VERSION 5.8 ;
BUSBITCHARS "[]" ;
DIVIDERCHAR "/" ;
MANUFACTURINGGRID 0.05 ;

UNITS
    DATABASE MICRONS 1000 ;
END UNITS

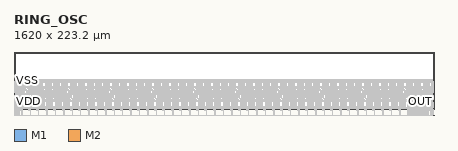
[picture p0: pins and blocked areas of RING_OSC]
MACRO RING_OSC
    CLASS BLOCK ;
    FOREIGN RING_OSC 0.0 0.0 ;
    ORIGIN 0.0 0.0 ;
    SIZE 1620.000 BY 223.200 ;

    PIN OUT
        DIRECTION OUTPUT ;
        USE SIGNAL ;
        PORT
            LAYER M1 ;
                RECT 1616.600 28.000 1620.000 31.400 ;
        END
    END OUT

    PIN OUTD
        DIRECTION OUTPUT ;
        USE SIGNAL ;
        PORT
            LAYER M1 ;
                RECT 1616.600 -26.600 1620.000 -23.200 ;
        END
    END OUTD

    PIN ENB
        DIRECTION INPUT ;
        USE SIGNAL ;
        PORT
            LAYER M2 ;
                RECT 11.800 -108.100 15.200 -104.700 ;
        END
    END ENB

    PIN VDD
        DIRECTION INOUT ;
        USE POWER ;
        PORT
            LAYER M1 ;
                RECT 0.000 -53.500 2.600 -50.900 ;
            LAYER M1 ;
                RECT 1617.400 -53.500 1620.000 -50.900 ;
            LAYER M1 ;
                RECT 0.000 55.700 2.600 58.300 ;
            LAYER M1 ;
                RECT 1617.400 55.700 1620.000 58.300 ;
        END
    END VDD

    PIN VSS
        DIRECTION INOUT ;
        USE GROUND ;
        PORT
            LAYER M1 ;
                RECT 0.000 -108.100 2.600 -105.500 ;
            LAYER M1 ;
                RECT 1617.400 -108.100 1620.000 -105.500 ;
            LAYER M1 ;
                RECT 0.000 1.100 2.600 3.700 ;
            LAYER M1 ;
                RECT 1617.400 1.100 1620.000 3.700 ;
            LAYER M1 ;
                RECT 0.000 110.300 2.600 112.900 ;
            LAYER M1 ;
                RECT 1617.400 110.300 1620.000 112.900 ;
        END
    END VSS

    OBS
        LAYER M1 ;
            POLYGON 2.600 -108.100  2.600 -105.500  1.000 -105.500  1.000 -102.900  4.400 -102.900  4.400 -105.500  11.800 -105.500  11.800 -90.100  14.400 -90.100  14.400 -105.500  18.000 -105.500  18.000 -73.100  20.600 -73.100  20.600 -105.500  49.300 -105.500  49.300 -99.300  51.900 -99.300  51.900 -105.500  81.700 -105.500  81.700 -99.300  84.300 -99.300  84.300 -105.500  114.100 -105.500  114.100 -99.300  116.700 -99.300  116.700 -105.500  146.500 -105.500  146.500 -99.300  149.100 -99.300  149.100 -105.500  178.900 -105.500  178.900 -99.300  181.500 -99.300  181.500 -105.500  211.300 -105.500  211.300 -99.300  213.900 -99.300  213.900 -105.500  243.700 -105.500  243.700 -99.300  246.300 -99.300  246.300 -105.500  276.100 -105.500  276.100 -99.300  278.700 -99.300  278.700 -105.500  308.500 -105.500  308.500 -99.300  311.100 -99.300  311.100 -105.500  340.900 -105.500  340.900 -99.300  343.500 -99.300  343.500 -105.500  373.300 -105.500  373.300 -99.300  375.900 -99.300  375.900 -105.500  405.700 -105.500  405.700 -99.300  408.300 -99.300  408.300 -105.500  438.100 -105.500  438.100 -99.300  440.700 -99.300  440.700 -105.500  470.500 -105.500  470.500 -99.300  473.100 -99.300  473.100 -105.500  502.900 -105.500  502.900 -99.300  505.500 -99.300  505.500 -105.500  535.300 -105.500  535.300 -99.300  537.900 -99.300  537.900 -105.500  567.700 -105.500  567.700 -99.300  570.300 -99.300  570.300 -105.500  600.100 -105.500  600.100 -99.300  602.700 -99.300  602.700 -105.500  632.500 -105.500  632.500 -99.300  635.100 -99.300  635.100 -105.500  664.900 -105.500  664.900 -99.300  667.500 -99.300  667.500 -105.500  697.300 -105.500  697.300 -99.300  699.900 -99.300  699.900 -105.500  729.700 -105.500  729.700 -99.300  732.300 -99.300  732.300 -105.500  762.100 -105.500  762.100 -99.300  764.700 -99.300  764.700 -105.500  794.500 -105.500  794.500 -99.300  797.100 -99.300  797.100 -105.500  826.900 -105.500  826.900 -99.300  829.500 -99.300  829.500 -105.500  859.300 -105.500  859.300 -99.300  861.900 -99.300  861.900 -105.500  891.700 -105.500  891.700 -99.300  894.300 -99.300  894.300 -105.500  924.100 -105.500  924.100 -99.300  926.700 -99.300  926.700 -105.500  956.500 -105.500  956.500 -99.300  959.100 -99.300  959.100 -105.500  988.900 -105.500  988.900 -99.300  991.500 -99.300  991.500 -105.500  1021.300 -105.500  1021.300 -99.300  1023.900 -99.300  1023.900 -105.500  1053.700 -105.500  1053.700 -99.300  1056.300 -99.300  1056.300 -105.500  1086.100 -105.500  1086.100 -99.300  1088.700 -99.300  1088.700 -105.500  1118.500 -105.500  1118.500 -99.300  1121.100 -99.300  1121.100 -105.500  1150.900 -105.500  1150.900 -99.300  1153.500 -99.300  1153.500 -105.500  1183.300 -105.500  1183.300 -99.300  1185.900 -99.300  1185.900 -105.500  1215.700 -105.500  1215.700 -99.300  1218.300 -99.300  1218.300 -105.500  1248.100 -105.500  1248.100 -99.300  1250.700 -99.300  1250.700 -105.500  1280.500 -105.500  1280.500 -99.300  1283.100 -99.300  1283.100 -105.500  1312.900 -105.500  1312.900 -99.300  1315.500 -99.300  1315.500 -105.500  1345.300 -105.500  1345.300 -99.300  1347.900 -99.300  1347.900 -105.500  1377.700 -105.500  1377.700 -99.300  1380.300 -99.300  1380.300 -105.500  1410.100 -105.500  1410.100 -99.300  1412.700 -99.300  1412.700 -105.500  1442.500 -105.500  1442.500 -99.300  1445.100 -99.300  1445.100 -105.500  1474.900 -105.500  1474.900 -99.300  1477.500 -99.300  1477.500 -105.500  1507.300 -105.500  1507.300 -99.300  1509.900 -99.300  1509.900 -105.500  1539.700 -105.500  1539.700 -99.300  1542.300 -99.300  1542.300 -105.500  1572.100 -105.500  1572.100 -99.300  1574.700 -99.300  1574.700 -105.500  1604.500 -105.500  1604.500 -99.300  1607.100 -99.300  1607.100 -105.500  1610.200 -105.500  1610.200 -102.900  1613.600 -102.900  1613.600 -105.500  1617.400 -105.500  1617.400 -108.100 ;
            POLYGON 11.800 -88.500  11.800 -53.500  9.800 -53.500  9.800 -56.100  6.400 -56.100  6.400 -53.500  2.600 -53.500  2.600 -50.900  6.400 -50.900  6.400 -48.300  9.800 -48.300  9.800 -50.900  11.800 -50.900  11.800 -32.900  14.400 -32.900  14.400 -50.900  18.000 -50.900  18.000 -15.900  20.600 -15.900  20.600 -50.900  22.300 -50.900  22.300 -37.900  24.900 -37.900  24.900 -50.900  54.700 -50.900  54.700 -37.900  57.300 -37.900  57.300 -50.900  87.100 -50.900  87.100 -37.900  89.700 -37.900  89.700 -50.900  119.500 -50.900  119.500 -37.900  122.100 -37.900  122.100 -50.900  151.900 -50.900  151.900 -37.900  154.500 -37.900  154.500 -50.900  184.300 -50.900  184.300 -37.900  186.900 -37.900  186.900 -50.900  216.700 -50.900  216.700 -37.900  219.300 -37.900  219.300 -50.900  249.100 -50.900  249.100 -37.900  251.700 -37.900  251.700 -50.900  281.500 -50.900  281.500 -37.900  284.100 -37.900  284.100 -50.900  313.900 -50.900  313.900 -37.900  316.500 -37.900  316.500 -50.900  346.300 -50.900  346.300 -37.900  348.900 -37.900  348.900 -50.900  378.700 -50.900  378.700 -37.900  381.300 -37.900  381.300 -50.900  411.100 -50.900  411.100 -37.900  413.700 -37.900  413.700 -50.900  443.500 -50.900  443.500 -37.900  446.100 -37.900  446.100 -50.900  475.900 -50.900  475.900 -37.900  478.500 -37.900  478.500 -50.900  508.300 -50.900  508.300 -37.900  510.900 -37.900  510.900 -50.900  540.700 -50.900  540.700 -37.900  543.300 -37.900  543.300 -50.900  573.100 -50.900  573.100 -37.900  575.700 -37.900  575.700 -50.900  605.500 -50.900  605.500 -37.900  608.100 -37.900  608.100 -50.900  637.900 -50.900  637.900 -37.900  640.500 -37.900  640.500 -50.900  670.300 -50.900  670.300 -37.900  672.900 -37.900  672.900 -50.900  702.700 -50.900  702.700 -37.900  705.300 -37.900  705.300 -50.900  735.100 -50.900  735.100 -37.900  737.700 -37.900  737.700 -50.900  767.500 -50.900  767.500 -37.900  770.100 -37.900  770.100 -50.900  799.900 -50.900  799.900 -37.900  802.500 -37.900  802.500 -50.900  832.300 -50.900  832.300 -37.900  834.900 -37.900  834.900 -50.900  864.700 -50.900  864.700 -37.900  867.300 -37.900  867.300 -50.900  897.100 -50.900  897.100 -37.900  899.700 -37.900  899.700 -50.900  929.500 -50.900  929.500 -37.900  932.100 -37.900  932.100 -50.900  961.900 -50.900  961.900 -37.900  964.500 -37.900  964.500 -50.900  994.300 -50.900  994.300 -37.900  996.900 -37.900  996.900 -50.900  1026.700 -50.900  1026.700 -37.900  1029.300 -37.900  1029.300 -50.900  1059.100 -50.900  1059.100 -37.900  1061.700 -37.900  1061.700 -50.900  1091.500 -50.900  1091.500 -37.900  1094.100 -37.900  1094.100 -50.900  1123.900 -50.900  1123.900 -37.900  1126.500 -37.900  1126.500 -50.900  1156.300 -50.900  1156.300 -37.900  1158.900 -37.900  1158.900 -50.900  1188.700 -50.900  1188.700 -37.900  1191.300 -37.900  1191.300 -50.900  1221.100 -50.900  1221.100 -37.900  1223.700 -37.900  1223.700 -50.900  1253.500 -50.900  1253.500 -37.900  1256.100 -37.900  1256.100 -50.900  1285.900 -50.900  1285.900 -37.900  1288.500 -37.900  1288.500 -50.900  1318.300 -50.900  1318.300 -37.900  1320.900 -37.900  1320.900 -50.900  1350.700 -50.900  1350.700 -37.900  1353.300 -37.900  1353.300 -50.900  1383.100 -50.900  1383.100 -37.900  1385.700 -37.900  1385.700 -50.900  1415.500 -50.900  1415.500 -37.900  1418.100 -37.900  1418.100 -50.900  1447.900 -50.900  1447.900 -37.900  1450.500 -37.900  1450.500 -50.900  1480.300 -50.900  1480.300 -37.900  1482.900 -37.900  1482.900 -50.900  1512.700 -50.900  1512.700 -37.900  1515.300 -37.900  1515.300 -50.900  1520.700 -50.900  1520.700 -37.900  1523.300 -37.900  1523.300 -50.900  1534.600 -50.900  1534.600 -32.900  1537.200 -32.900  1537.200 -50.900  1540.800 -50.900  1540.800 -15.900  1543.400 -15.900  1543.400 -50.900  1545.400 -50.900  1545.400 -32.900  1548.000 -32.900  1548.000 -50.900  1551.600 -50.900  1551.600 -15.900  1554.200 -15.900  1554.200 -50.900  1556.200 -50.900  1556.200 -32.900  1558.800 -32.900  1558.800 -50.900  1562.400 -50.900  1562.400 -15.900  1565.000 -15.900  1565.000 -50.900  1567.000 -50.900  1567.000 -32.900  1569.600 -32.900  1569.600 -50.900  1573.200 -50.900  1573.200 -15.900  1575.800 -15.900  1575.800 -50.900  1577.800 -50.900  1577.800 -32.900  1580.400 -32.900  1580.400 -50.900  1584.000 -50.900  1584.000 -15.900  1586.600 -15.900  1586.600 -50.900  1588.600 -50.900  1588.600 -32.900  1591.200 -32.900  1591.200 -50.900  1594.800 -50.900  1594.800 -15.900  1597.400 -15.900  1597.400 -50.900  1599.100 -50.900  1599.100 -37.900  1601.700 -37.900  1601.700 -50.900  1615.600 -50.900  1615.600 -48.300  1619.000 -48.300  1619.000 -50.900  1617.400 -50.900  1617.400 -53.500  1619.000 -53.500  1619.000 -56.100  1615.600 -56.100  1615.600 -53.500  1608.500 -53.500  1608.500 -66.500  1605.900 -66.500  1605.900 -53.500  1576.100 -53.500  1576.100 -66.500  1573.500 -66.500  1573.500 -53.500  1543.700 -53.500  1543.700 -66.500  1541.100 -66.500  1541.100 -53.500  1511.300 -53.500  1511.300 -66.500  1508.700 -66.500  1508.700 -53.500  1478.900 -53.500  1478.900 -66.500  1476.300 -66.500  1476.300 -53.500  1446.500 -53.500  1446.500 -66.500  1443.900 -66.500  1443.900 -53.500  1414.100 -53.500  1414.100 -66.500  1411.500 -66.500  1411.500 -53.500  1381.700 -53.500  1381.700 -66.500  1379.100 -66.500  1379.100 -53.500  1349.300 -53.500  1349.300 -66.500  1346.700 -66.500  1346.700 -53.500  1316.900 -53.500  1316.900 -66.500  1314.300 -66.500  1314.300 -53.500  1284.500 -53.500  1284.500 -66.500  1281.900 -66.500  1281.900 -53.500  1252.100 -53.500  1252.100 -66.500  1249.500 -66.500  1249.500 -53.500  1219.700 -53.500  1219.700 -66.500  1217.100 -66.500  1217.100 -53.500  1187.300 -53.500  1187.300 -66.500  1184.700 -66.500  1184.700 -53.500  1154.900 -53.500  1154.900 -66.500  1152.300 -66.500  1152.300 -53.500  1122.500 -53.500  1122.500 -66.500  1119.900 -66.500  1119.900 -53.500  1090.100 -53.500  1090.100 -66.500  1087.500 -66.500  1087.500 -53.500  1057.700 -53.500  1057.700 -66.500  1055.100 -66.500  1055.100 -53.500  1025.300 -53.500  1025.300 -66.500  1022.700 -66.500  1022.700 -53.500  992.900 -53.500  992.900 -66.500  990.300 -66.500  990.300 -53.500  960.500 -53.500  960.500 -66.500  957.900 -66.500  957.900 -53.500  928.100 -53.500  928.100 -66.500  925.500 -66.500  925.500 -53.500  895.700 -53.500  895.700 -66.500  893.100 -66.500  893.100 -53.500  863.300 -53.500  863.300 -66.500  860.700 -66.500  860.700 -53.500  830.900 -53.500  830.900 -66.500  828.300 -66.500  828.300 -53.500  798.500 -53.500  798.500 -66.500  795.900 -66.500  795.900 -53.500  766.100 -53.500  766.100 -66.500  763.500 -66.500  763.500 -53.500  733.700 -53.500  733.700 -66.500  731.100 -66.500  731.100 -53.500  701.300 -53.500  701.300 -66.500  698.700 -66.500  698.700 -53.500  668.900 -53.500  668.900 -66.500  666.300 -66.500  666.300 -53.500  636.500 -53.500  636.500 -66.500  633.900 -66.500  633.900 -53.500  604.100 -53.500  604.100 -66.500  601.500 -66.500  601.500 -53.500  571.700 -53.500  571.700 -66.500  569.100 -66.500  569.100 -53.500  539.300 -53.500  539.300 -66.500  536.700 -66.500  536.700 -53.500  506.900 -53.500  506.900 -66.500  504.300 -66.500  504.300 -53.500  474.500 -53.500  474.500 -66.500  471.900 -66.500  471.900 -53.500  442.100 -53.500  442.100 -66.500  439.500 -66.500  439.500 -53.500  409.700 -53.500  409.700 -66.500  407.100 -66.500  407.100 -53.500  377.300 -53.500  377.300 -66.500  374.700 -66.500  374.700 -53.500  344.900 -53.500  344.900 -66.500  342.300 -66.500  342.300 -53.500  312.500 -53.500  312.500 -66.500  309.900 -66.500  309.900 -53.500  280.100 -53.500  280.100 -66.500  277.500 -66.500  277.500 -53.500  247.700 -53.500  247.700 -66.500  245.100 -66.500  245.100 -53.500  215.300 -53.500  215.300 -66.500  212.700 -66.500  212.700 -53.500  182.900 -53.500  182.900 -66.500  180.300 -66.500  180.300 -53.500  150.500 -53.500  150.500 -66.500  147.900 -66.500  147.900 -53.500  118.100 -53.500  118.100 -66.500  115.500 -66.500  115.500 -53.500  85.700 -53.500  85.700 -66.500  83.100 -66.500  83.100 -53.500  53.300 -53.500  53.300 -66.500  50.700 -66.500  50.700 -53.500  20.600 -53.500  20.600 -71.500  18.000 -71.500  18.000 -53.500  14.400 -53.500  14.400 -88.500 ;
            POLYGON 11.800 -31.300  11.800 1.100  4.400 1.100  4.400 -1.500  1.000 -1.500  1.000 1.100  2.600 1.100  2.600 3.700  1.000 3.700  1.000 6.300  4.400 6.300  4.400 3.700  11.800 3.700  11.800 36.100  14.400 36.100  14.400 3.700  18.000 3.700  18.000 19.100  20.600 19.100  20.600 3.700  23.700 3.700  23.700 9.900  26.300 9.900  26.300 3.700  33.400 3.700  33.400 36.100  36.000 36.100  36.000 3.700  39.600 3.700  39.600 19.100  42.200 19.100  42.200 3.700  44.200 3.700  44.200 36.100  46.800 36.100  46.800 3.700  50.400 3.700  50.400 19.100  53.000 19.100  53.000 3.700  56.100 3.700  56.100 9.900  58.700 9.900  58.700 3.700  65.800 3.700  65.800 36.100  68.400 36.100  68.400 3.700  72.000 3.700  72.000 19.100  74.600 19.100  74.600 3.700  76.600 3.700  76.600 36.100  79.200 36.100  79.200 3.700  82.800 3.700  82.800 19.100  85.400 19.100  85.400 3.700  88.500 3.700  88.500 9.900  91.100 9.900  91.100 3.700  98.200 3.700  98.200 36.100  100.800 36.100  100.800 3.700  104.400 3.700  104.400 19.100  107.000 19.100  107.000 3.700  109.000 3.700  109.000 36.100  111.600 36.100  111.600 3.700  115.200 3.700  115.200 19.100  117.800 19.100  117.800 3.700  120.900 3.700  120.900 9.900  123.500 9.900  123.500 3.700  130.600 3.700  130.600 36.100  133.200 36.100  133.200 3.700  136.800 3.700  136.800 19.100  139.400 19.100  139.400 3.700  141.400 3.700  141.400 36.100  144.000 36.100  144.000 3.700  147.600 3.700  147.600 19.100  150.200 19.100  150.200 3.700  153.300 3.700  153.300 9.900  155.900 9.900  155.900 3.700  163.000 3.700  163.000 36.100  165.600 36.100  165.600 3.700  169.200 3.700  169.200 19.100  171.800 19.100  171.800 3.700  173.800 3.700  173.800 36.100  176.400 36.100  176.400 3.700  180.000 3.700  180.000 19.100  182.600 19.100  182.600 3.700  185.700 3.700  185.700 9.900  188.300 9.900  188.300 3.700  195.400 3.700  195.400 36.100  198.000 36.100  198.000 3.700  201.600 3.700  201.600 19.100  204.200 19.100  204.200 3.700  206.200 3.700  206.200 36.100  208.800 36.100  208.800 3.700  212.400 3.700  212.400 19.100  215.000 19.100  215.000 3.700  218.100 3.700  218.100 9.900  220.700 9.900  220.700 3.700  227.800 3.700  227.800 36.100  230.400 36.100  230.400 3.700  234.000 3.700  234.000 19.100  236.600 19.100  236.600 3.700  238.600 3.700  238.600 36.100  241.200 36.100  241.200 3.700  244.800 3.700  244.800 19.100  247.400 19.100  247.400 3.700  250.500 3.700  250.500 9.900  253.100 9.900  253.100 3.700  260.200 3.700  260.200 36.100  262.800 36.100  262.800 3.700  266.400 3.700  266.400 19.100  269.000 19.100  269.000 3.700  271.000 3.700  271.000 36.100  273.600 36.100  273.600 3.700  277.200 3.700  277.200 19.100  279.800 19.100  279.800 3.700  282.900 3.700  282.900 9.900  285.500 9.900  285.500 3.700  292.600 3.700  292.600 36.100  295.200 36.100  295.200 3.700  298.800 3.700  298.800 19.100  301.400 19.100  301.400 3.700  303.400 3.700  303.400 36.100  306.000 36.100  306.000 3.700  309.600 3.700  309.600 19.100  312.200 19.100  312.200 3.700  315.300 3.700  315.300 9.900  317.900 9.900  317.900 3.700  325.000 3.700  325.000 36.100  327.600 36.100  327.600 3.700  331.200 3.700  331.200 19.100  333.800 19.100  333.800 3.700  335.800 3.700  335.800 36.100  338.400 36.100  338.400 3.700  342.000 3.700  342.000 19.100  344.600 19.100  344.600 3.700  347.700 3.700  347.700 9.900  350.300 9.900  350.300 3.700  357.400 3.700  357.400 36.100  360.000 36.100  360.000 3.700  363.600 3.700  363.600 19.100  366.200 19.100  366.200 3.700  368.200 3.700  368.200 36.100  370.800 36.100  370.800 3.700  374.400 3.700  374.400 19.100  377.000 19.100  377.000 3.700  380.100 3.700  380.100 9.900  382.700 9.900  382.700 3.700  389.800 3.700  389.800 36.100  392.400 36.100  392.400 3.700  396.000 3.700  396.000 19.100  398.600 19.100  398.600 3.700  400.600 3.700  400.600 36.100  403.200 36.100  403.200 3.700  406.800 3.700  406.800 19.100  409.400 19.100  409.400 3.700  412.500 3.700  412.500 9.900  415.100 9.900  415.100 3.700  422.200 3.700  422.200 36.100  424.800 36.100  424.800 3.700  428.400 3.700  428.400 19.100  431.000 19.100  431.000 3.700  433.000 3.700  433.000 36.100  435.600 36.100  435.600 3.700  439.200 3.700  439.200 19.100  441.800 19.100  441.800 3.700  444.900 3.700  444.900 9.900  447.500 9.900  447.500 3.700  454.600 3.700  454.600 36.100  457.200 36.100  457.200 3.700  460.800 3.700  460.800 19.100  463.400 19.100  463.400 3.700  465.400 3.700  465.400 36.100  468.000 36.100  468.000 3.700  471.600 3.700  471.600 19.100  474.200 19.100  474.200 3.700  477.300 3.700  477.300 9.900  479.900 9.900  479.900 3.700  487.000 3.700  487.000 36.100  489.600 36.100  489.600 3.700  493.200 3.700  493.200 19.100  495.800 19.100  495.800 3.700  497.800 3.700  497.800 36.100  500.400 36.100  500.400 3.700  504.000 3.700  504.000 19.100  506.600 19.100  506.600 3.700  509.700 3.700  509.700 9.900  512.300 9.900  512.300 3.700  519.400 3.700  519.400 36.100  522.000 36.100  522.000 3.700  525.600 3.700  525.600 19.100  528.200 19.100  528.200 3.700  530.200 3.700  530.200 36.100  532.800 36.100  532.800 3.700  536.400 3.700  536.400 19.100  539.000 19.100  539.000 3.700  542.100 3.700  542.100 9.900  544.700 9.900  544.700 3.700  551.800 3.700  551.800 36.100  554.400 36.100  554.400 3.700  558.000 3.700  558.000 19.100  560.600 19.100  560.600 3.700  562.600 3.700  562.600 36.100  565.200 36.100  565.200 3.700  568.800 3.700  568.800 19.100  571.400 19.100  571.400 3.700  574.500 3.700  574.500 9.900  577.100 9.900  577.100 3.700  584.200 3.700  584.200 36.100  586.800 36.100  586.800 3.700  590.400 3.700  590.400 19.100  593.000 19.100  593.000 3.700  595.000 3.700  595.000 36.100  597.600 36.100  597.600 3.700  601.200 3.700  601.200 19.100  603.800 19.100  603.800 3.700  606.900 3.700  606.900 9.900  609.500 9.900  609.500 3.700  616.600 3.700  616.600 36.100  619.200 36.100  619.200 3.700  622.800 3.700  622.800 19.100  625.400 19.100  625.400 3.700  627.400 3.700  627.400 36.100  630.000 36.100  630.000 3.700  633.600 3.700  633.600 19.100  636.200 19.100  636.200 3.700  639.300 3.700  639.300 9.900  641.900 9.900  641.900 3.700  649.000 3.700  649.000 36.100  651.600 36.100  651.600 3.700  655.200 3.700  655.200 19.100  657.800 19.100  657.800 3.700  659.800 3.700  659.800 36.100  662.400 36.100  662.400 3.700  666.000 3.700  666.000 19.100  668.600 19.100  668.600 3.700  671.700 3.700  671.700 9.900  674.300 9.900  674.300 3.700  681.400 3.700  681.400 36.100  684.000 36.100  684.000 3.700  687.600 3.700  687.600 19.100  690.200 19.100  690.200 3.700  692.200 3.700  692.200 36.100  694.800 36.100  694.800 3.700  698.400 3.700  698.400 19.100  701.000 19.100  701.000 3.700  704.100 3.700  704.100 9.900  706.700 9.900  706.700 3.700  713.800 3.700  713.800 36.100  716.400 36.100  716.400 3.700  720.000 3.700  720.000 19.100  722.600 19.100  722.600 3.700  724.600 3.700  724.600 36.100  727.200 36.100  727.200 3.700  730.800 3.700  730.800 19.100  733.400 19.100  733.400 3.700  736.500 3.700  736.500 9.900  739.100 9.900  739.100 3.700  746.200 3.700  746.200 36.100  748.800 36.100  748.800 3.700  752.400 3.700  752.400 19.100  755.000 19.100  755.000 3.700  757.000 3.700  757.000 36.100  759.600 36.100  759.600 3.700  763.200 3.700  763.200 19.100  765.800 19.100  765.800 3.700  768.900 3.700  768.900 9.900  771.500 9.900  771.500 3.700  778.600 3.700  778.600 36.100  781.200 36.100  781.200 3.700  784.800 3.700  784.800 19.100  787.400 19.100  787.400 3.700  789.400 3.700  789.400 36.100  792.000 36.100  792.000 3.700  795.600 3.700  795.600 19.100  798.200 19.100  798.200 3.700  801.300 3.700  801.300 9.900  803.900 9.900  803.900 3.700  811.000 3.700  811.000 36.100  813.600 36.100  813.600 3.700  817.200 3.700  817.200 19.100  819.800 19.100  819.800 3.700  821.800 3.700  821.800 36.100  824.400 36.100  824.400 3.700  828.000 3.700  828.000 19.100  830.600 19.100  830.600 3.700  833.700 3.700  833.700 9.900  836.300 9.900  836.300 3.700  843.400 3.700  843.400 36.100  846.000 36.100  846.000 3.700  849.600 3.700  849.600 19.100  852.200 19.100  852.200 3.700  854.200 3.700  854.200 36.100  856.800 36.100  856.800 3.700  860.400 3.700  860.400 19.100  863.000 19.100  863.000 3.700  866.100 3.700  866.100 9.900  868.700 9.900  868.700 3.700  875.800 3.700  875.800 36.100  878.400 36.100  878.400 3.700  882.000 3.700  882.000 19.100  884.600 19.100  884.600 3.700  886.600 3.700  886.600 36.100  889.200 36.100  889.200 3.700  892.800 3.700  892.800 19.100  895.400 19.100  895.400 3.700  898.500 3.700  898.500 9.900  901.100 9.900  901.100 3.700  908.200 3.700  908.200 36.100  910.800 36.100  910.800 3.700  914.400 3.700  914.400 19.100  917.000 19.100  917.000 3.700  919.000 3.700  919.000 36.100  921.600 36.100  921.600 3.700  925.200 3.700  925.200 19.100  927.800 19.100  927.800 3.700  930.900 3.700  930.900 9.900  933.500 9.900  933.500 3.700  940.600 3.700  940.600 36.100  943.200 36.100  943.200 3.700  946.800 3.700  946.800 19.100  949.400 19.100  949.400 3.700  951.400 3.700  951.400 36.100  954.000 36.100  954.000 3.700  957.600 3.700  957.600 19.100  960.200 19.100  960.200 3.700  963.300 3.700  963.300 9.900  965.900 9.900  965.900 3.700  973.000 3.700  973.000 36.100  975.600 36.100  975.600 3.700  979.200 3.700  979.200 19.100  981.800 19.100  981.800 3.700  983.800 3.700  983.800 36.100  986.400 36.100  986.400 3.700  990.000 3.700  990.000 19.100  992.600 19.100  992.600 3.700  995.700 3.700  995.700 9.900  998.300 9.900  998.300 3.700  1005.400 3.700  1005.400 36.100  1008.000 36.100  1008.000 3.700  1011.600 3.700  1011.600 19.100  1014.200 19.100  1014.200 3.700  1016.200 3.700  1016.200 36.100  1018.800 36.100  1018.800 3.700  1022.400 3.700  1022.400 19.100  1025.000 19.100  1025.000 3.700  1028.100 3.700  1028.100 9.900  1030.700 9.900  1030.700 3.700  1037.800 3.700  1037.800 36.100  1040.400 36.100  1040.400 3.700  1044.000 3.700  1044.000 19.100  1046.600 19.100  1046.600 3.700  1048.600 3.700  1048.600 36.100  1051.200 36.100  1051.200 3.700  1054.800 3.700  1054.800 19.100  1057.400 19.100  1057.400 3.700  1060.500 3.700  1060.500 9.900  1063.100 9.900  1063.100 3.700  1070.200 3.700  1070.200 36.100  1072.800 36.100  1072.800 3.700  1076.400 3.700  1076.400 19.100  1079.000 19.100  1079.000 3.700  1081.000 3.700  1081.000 36.100  1083.600 36.100  1083.600 3.700  1087.200 3.700  1087.200 19.100  1089.800 19.100  1089.800 3.700  1092.900 3.700  1092.900 9.900  1095.500 9.900  1095.500 3.700  1102.600 3.700  1102.600 36.100  1105.200 36.100  1105.200 3.700  1108.800 3.700  1108.800 19.100  1111.400 19.100  1111.400 3.700  1113.400 3.700  1113.400 36.100  1116.000 36.100  1116.000 3.700  1119.600 3.700  1119.600 19.100  1122.200 19.100  1122.200 3.700  1125.300 3.700  1125.300 9.900  1127.900 9.900  1127.900 3.700  1135.000 3.700  1135.000 36.100  1137.600 36.100  1137.600 3.700  1141.200 3.700  1141.200 19.100  1143.800 19.100  1143.800 3.700  1145.800 3.700  1145.800 36.100  1148.400 36.100  1148.400 3.700  1152.000 3.700  1152.000 19.100  1154.600 19.100  1154.600 3.700  1157.700 3.700  1157.700 9.900  1160.300 9.900  1160.300 3.700  1167.400 3.700  1167.400 36.100  1170.000 36.100  1170.000 3.700  1173.600 3.700  1173.600 19.100  1176.200 19.100  1176.200 3.700  1178.200 3.700  1178.200 36.100  1180.800 36.100  1180.800 3.700  1184.400 3.700  1184.400 19.100  1187.000 19.100  1187.000 3.700  1190.100 3.700  1190.100 9.900  1192.700 9.900  1192.700 3.700  1199.800 3.700  1199.800 36.100  1202.400 36.100  1202.400 3.700  1206.000 3.700  1206.000 19.100  1208.600 19.100  1208.600 3.700  1210.600 3.700  1210.600 36.100  1213.200 36.100  1213.200 3.700  1216.800 3.700  1216.800 19.100  1219.400 19.100  1219.400 3.700  1222.500 3.700  1222.500 9.900  1225.100 9.900  1225.100 3.700  1232.200 3.700  1232.200 36.100  1234.800 36.100  1234.800 3.700  1238.400 3.700  1238.400 19.100  1241.000 19.100  1241.000 3.700  1243.000 3.700  1243.000 36.100  1245.600 36.100  1245.600 3.700  1249.200 3.700  1249.200 19.100  1251.800 19.100  1251.800 3.700  1254.900 3.700  1254.900 9.900  1257.500 9.900  1257.500 3.700  1264.600 3.700  1264.600 36.100  1267.200 36.100  1267.200 3.700  1270.800 3.700  1270.800 19.100  1273.400 19.100  1273.400 3.700  1275.400 3.700  1275.400 36.100  1278.000 36.100  1278.000 3.700  1281.600 3.700  1281.600 19.100  1284.200 19.100  1284.200 3.700  1287.300 3.700  1287.300 9.900  1289.900 9.900  1289.900 3.700  1297.000 3.700  1297.000 36.100  1299.600 36.100  1299.600 3.700  1303.200 3.700  1303.200 19.100  1305.800 19.100  1305.800 3.700  1307.800 3.700  1307.800 36.100  1310.400 36.100  1310.400 3.700  1314.000 3.700  1314.000 19.100  1316.600 19.100  1316.600 3.700  1319.700 3.700  1319.700 9.900  1322.300 9.900  1322.300 3.700  1329.400 3.700  1329.400 36.100  1332.000 36.100  1332.000 3.700  1335.600 3.700  1335.600 19.100  1338.200 19.100  1338.200 3.700  1340.200 3.700  1340.200 36.100  1342.800 36.100  1342.800 3.700  1346.400 3.700  1346.400 19.100  1349.000 19.100  1349.000 3.700  1352.100 3.700  1352.100 9.900  1354.700 9.900  1354.700 3.700  1361.800 3.700  1361.800 36.100  1364.400 36.100  1364.400 3.700  1368.000 3.700  1368.000 19.100  1370.600 19.100  1370.600 3.700  1372.600 3.700  1372.600 36.100  1375.200 36.100  1375.200 3.700  1378.800 3.700  1378.800 19.100  1381.400 19.100  1381.400 3.700  1384.500 3.700  1384.500 9.900  1387.100 9.900  1387.100 3.700  1394.200 3.700  1394.200 36.100  1396.800 36.100  1396.800 3.700  1400.400 3.700  1400.400 19.100  1403.000 19.100  1403.000 3.700  1405.000 3.700  1405.000 36.100  1407.600 36.100  1407.600 3.700  1411.200 3.700  1411.200 19.100  1413.800 19.100  1413.800 3.700  1416.900 3.700  1416.900 9.900  1419.500 9.900  1419.500 3.700  1426.600 3.700  1426.600 36.100  1429.200 36.100  1429.200 3.700  1432.800 3.700  1432.800 19.100  1435.400 19.100  1435.400 3.700  1437.400 3.700  1437.400 36.100  1440.000 36.100  1440.000 3.700  1443.600 3.700  1443.600 19.100  1446.200 19.100  1446.200 3.700  1449.300 3.700  1449.300 9.900  1451.900 9.900  1451.900 3.700  1459.000 3.700  1459.000 36.100  1461.600 36.100  1461.600 3.700  1465.200 3.700  1465.200 19.100  1467.800 19.100  1467.800 3.700  1469.800 3.700  1469.800 36.100  1472.400 36.100  1472.400 3.700  1476.000 3.700  1476.000 19.100  1478.600 19.100  1478.600 3.700  1481.700 3.700  1481.700 9.900  1484.300 9.900  1484.300 3.700  1491.400 3.700  1491.400 36.100  1494.000 36.100  1494.000 3.700  1497.600 3.700  1497.600 19.100  1500.200 19.100  1500.200 3.700  1502.200 3.700  1502.200 36.100  1504.800 36.100  1504.800 3.700  1508.400 3.700  1508.400 19.100  1511.000 19.100  1511.000 3.700  1517.300 3.700  1517.300 19.600  1519.900 19.600  1519.900 11.100  1527.500 11.100  1527.500 7.700  1519.900 7.700  1519.900 3.700  1534.600 3.700  1534.600 36.100  1537.200 36.100  1537.200 3.700  1540.800 3.700  1540.800 19.100  1543.400 19.100  1543.400 3.700  1545.400 3.700  1545.400 36.100  1548.000 36.100  1548.000 3.700  1551.600 3.700  1551.600 19.100  1554.200 19.100  1554.200 3.700  1556.200 3.700  1556.200 36.100  1558.800 36.100  1558.800 3.700  1562.400 3.700  1562.400 19.100  1565.000 19.100  1565.000 3.700  1567.000 3.700  1567.000 36.100  1569.600 36.100  1569.600 3.700  1573.200 3.700  1573.200 19.100  1575.800 19.100  1575.800 3.700  1577.800 3.700  1577.800 36.100  1580.400 36.100  1580.400 3.700  1584.000 3.700  1584.000 19.100  1586.600 19.100  1586.600 3.700  1588.600 3.700  1588.600 36.100  1591.200 36.100  1591.200 3.700  1594.800 3.700  1594.800 19.100  1597.400 19.100  1597.400 3.700  1600.500 3.700  1600.500 9.900  1603.100 9.900  1603.100 3.700  1610.200 3.700  1610.200 6.300  1613.600 6.300  1613.600 3.700  1617.400 3.700  1617.400 1.100  1613.600 1.100  1613.600 -1.500  1610.200 -1.500  1610.200 1.100  1603.100 1.100  1603.100 -5.100  1600.500 -5.100  1600.500 1.100  1597.400 1.100  1597.400 -14.300  1594.800 -14.300  1594.800 1.100  1591.200 1.100  1591.200 -31.300  1588.600 -31.300  1588.600 1.100  1586.600 1.100  1586.600 -14.300  1584.000 -14.300  1584.000 1.100  1580.400 1.100  1580.400 -31.300  1577.800 -31.300  1577.800 1.100  1575.800 1.100  1575.800 -14.300  1573.200 -14.300  1573.200 1.100  1569.600 1.100  1569.600 -31.300  1567.000 -31.300  1567.000 1.100  1565.000 1.100  1565.000 -14.300  1562.400 -14.300  1562.400 1.100  1558.800 1.100  1558.800 -31.300  1556.200 -31.300  1556.200 1.100  1554.200 1.100  1554.200 -14.300  1551.600 -14.300  1551.600 1.100  1548.000 1.100  1548.000 -31.300  1545.400 -31.300  1545.400 1.100  1543.400 1.100  1543.400 -14.300  1540.800 -14.300  1540.800 1.100  1537.200 1.100  1537.200 -31.300  1534.600 -31.300  1534.600 1.100  1519.900 1.100  1519.900 -2.900  1527.500 -2.900  1527.500 -6.300  1519.900 -6.300  1519.900 -14.800  1517.300 -14.800  1517.300 1.100  1484.300 1.100  1484.300 -5.100  1481.700 -5.100  1481.700 1.100  1451.900 1.100  1451.900 -5.100  1449.300 -5.100  1449.300 1.100  1419.500 1.100  1419.500 -5.100  1416.900 -5.100  1416.900 1.100  1387.100 1.100  1387.100 -5.100  1384.500 -5.100  1384.500 1.100  1354.700 1.100  1354.700 -5.100  1352.100 -5.100  1352.100 1.100  1322.300 1.100  1322.300 -5.100  1319.700 -5.100  1319.700 1.100  1289.900 1.100  1289.900 -5.100  1287.300 -5.100  1287.300 1.100  1257.500 1.100  1257.500 -5.100  1254.900 -5.100  1254.900 1.100  1225.100 1.100  1225.100 -5.100  1222.500 -5.100  1222.500 1.100  1192.700 1.100  1192.700 -5.100  1190.100 -5.100  1190.100 1.100  1160.300 1.100  1160.300 -5.100  1157.700 -5.100  1157.700 1.100  1127.900 1.100  1127.900 -5.100  1125.300 -5.100  1125.300 1.100  1095.500 1.100  1095.500 -5.100  1092.900 -5.100  1092.900 1.100  1063.100 1.100  1063.100 -5.100  1060.500 -5.100  1060.500 1.100  1030.700 1.100  1030.700 -5.100  1028.100 -5.100  1028.100 1.100  998.300 1.100  998.300 -5.100  995.700 -5.100  995.700 1.100  965.900 1.100  965.900 -5.100  963.300 -5.100  963.300 1.100  933.500 1.100  933.500 -5.100  930.900 -5.100  930.900 1.100  901.100 1.100  901.100 -5.100  898.500 -5.100  898.500 1.100  868.700 1.100  868.700 -5.100  866.100 -5.100  866.100 1.100  836.300 1.100  836.300 -5.100  833.700 -5.100  833.700 1.100  803.900 1.100  803.900 -5.100  801.300 -5.100  801.300 1.100  771.500 1.100  771.500 -5.100  768.900 -5.100  768.900 1.100  739.100 1.100  739.100 -5.100  736.500 -5.100  736.500 1.100  706.700 1.100  706.700 -5.100  704.100 -5.100  704.100 1.100  674.300 1.100  674.300 -5.100  671.700 -5.100  671.700 1.100  641.900 1.100  641.900 -5.100  639.300 -5.100  639.300 1.100  609.500 1.100  609.500 -5.100  606.900 -5.100  606.900 1.100  577.100 1.100  577.100 -5.100  574.500 -5.100  574.500 1.100  544.700 1.100  544.700 -5.100  542.100 -5.100  542.100 1.100  512.300 1.100  512.300 -5.100  509.700 -5.100  509.700 1.100  479.900 1.100  479.900 -5.100  477.300 -5.100  477.300 1.100  447.500 1.100  447.500 -5.100  444.900 -5.100  444.900 1.100  415.100 1.100  415.100 -5.100  412.500 -5.100  412.500 1.100  382.700 1.100  382.700 -5.100  380.100 -5.100  380.100 1.100  350.300 1.100  350.300 -5.100  347.700 -5.100  347.700 1.100  317.900 1.100  317.900 -5.100  315.300 -5.100  315.300 1.100  285.500 1.100  285.500 -5.100  282.900 -5.100  282.900 1.100  253.100 1.100  253.100 -5.100  250.500 -5.100  250.500 1.100  220.700 1.100  220.700 -5.100  218.100 -5.100  218.100 1.100  188.300 1.100  188.300 -5.100  185.700 -5.100  185.700 1.100  155.900 1.100  155.900 -5.100  153.300 -5.100  153.300 1.100  123.500 1.100  123.500 -5.100  120.900 -5.100  120.900 1.100  91.100 1.100  91.100 -5.100  88.500 -5.100  88.500 1.100  58.700 1.100  58.700 -5.100  56.100 -5.100  56.100 1.100  26.300 1.100  26.300 -5.100  23.700 -5.100  23.700 1.100  20.600 1.100  20.600 -14.300  18.000 -14.300  18.000 1.100  14.400 1.100  14.400 -31.300 ;
            POLYGON 18.000 20.700  18.000 55.700  14.400 55.700  14.400 37.700  11.800 37.700  11.800 55.700  9.800 55.700  9.800 53.100  6.400 53.100  6.400 55.700  2.600 55.700  2.600 58.300  6.400 58.300  6.400 60.900  9.800 60.900  9.800 58.300  11.800 58.300  11.800 93.300  14.400 93.300  14.400 58.300  18.000 58.300  18.000 76.300  20.600 76.300  20.600 58.300  22.600 58.300  22.600 93.300  25.200 93.300  25.200 58.300  28.800 58.300  28.800 76.300  31.400 76.300  31.400 58.300  33.400 58.300  33.400 93.300  36.000 93.300  36.000 58.300  39.600 58.300  39.600 76.300  42.200 76.300  42.200 58.300  50.700 58.300  50.700 71.300  53.300 71.300  53.300 58.300  55.000 58.300  55.000 93.300  57.600 93.300  57.600 58.300  61.200 58.300  61.200 76.300  63.800 76.300  63.800 58.300  65.800 58.300  65.800 93.300  68.400 93.300  68.400 58.300  72.000 58.300  72.000 76.300  74.600 76.300  74.600 58.300  83.100 58.300  83.100 71.300  85.700 71.300  85.700 58.300  87.400 58.300  87.400 93.300  90.000 93.300  90.000 58.300  93.600 58.300  93.600 76.300  96.200 76.300  96.200 58.300  98.200 58.300  98.200 93.300  100.800 93.300  100.800 58.300  104.400 58.300  104.400 76.300  107.000 76.300  107.000 58.300  115.500 58.300  115.500 71.300  118.100 71.300  118.100 58.300  119.800 58.300  119.800 93.300  122.400 93.300  122.400 58.300  126.000 58.300  126.000 76.300  128.600 76.300  128.600 58.300  130.600 58.300  130.600 93.300  133.200 93.300  133.200 58.300  136.800 58.300  136.800 76.300  139.400 76.300  139.400 58.300  147.900 58.300  147.900 71.300  150.500 71.300  150.500 58.300  152.200 58.300  152.200 93.300  154.800 93.300  154.800 58.300  158.400 58.300  158.400 76.300  161.000 76.300  161.000 58.300  163.000 58.300  163.000 93.300  165.600 93.300  165.600 58.300  169.200 58.300  169.200 76.300  171.800 76.300  171.800 58.300  180.300 58.300  180.300 71.300  182.900 71.300  182.900 58.300  184.600 58.300  184.600 93.300  187.200 93.300  187.200 58.300  190.800 58.300  190.800 76.300  193.400 76.300  193.400 58.300  195.400 58.300  195.400 93.300  198.000 93.300  198.000 58.300  201.600 58.300  201.600 76.300  204.200 76.300  204.200 58.300  212.700 58.300  212.700 71.300  215.300 71.300  215.300 58.300  217.000 58.300  217.000 93.300  219.600 93.300  219.600 58.300  223.200 58.300  223.200 76.300  225.800 76.300  225.800 58.300  227.800 58.300  227.800 93.300  230.400 93.300  230.400 58.300  234.000 58.300  234.000 76.300  236.600 76.300  236.600 58.300  245.100 58.300  245.100 71.300  247.700 71.300  247.700 58.300  249.400 58.300  249.400 93.300  252.000 93.300  252.000 58.300  255.600 58.300  255.600 76.300  258.200 76.300  258.200 58.300  260.200 58.300  260.200 93.300  262.800 93.300  262.800 58.300  266.400 58.300  266.400 76.300  269.000 76.300  269.000 58.300  277.500 58.300  277.500 71.300  280.100 71.300  280.100 58.300  281.800 58.300  281.800 93.300  284.400 93.300  284.400 58.300  288.000 58.300  288.000 76.300  290.600 76.300  290.600 58.300  292.600 58.300  292.600 93.300  295.200 93.300  295.200 58.300  298.800 58.300  298.800 76.300  301.400 76.300  301.400 58.300  309.900 58.300  309.900 71.300  312.500 71.300  312.500 58.300  314.200 58.300  314.200 93.300  316.800 93.300  316.800 58.300  320.400 58.300  320.400 76.300  323.000 76.300  323.000 58.300  325.000 58.300  325.000 93.300  327.600 93.300  327.600 58.300  331.200 58.300  331.200 76.300  333.800 76.300  333.800 58.300  342.300 58.300  342.300 71.300  344.900 71.300  344.900 58.300  346.600 58.300  346.600 93.300  349.200 93.300  349.200 58.300  352.800 58.300  352.800 76.300  355.400 76.300  355.400 58.300  357.400 58.300  357.400 93.300  360.000 93.300  360.000 58.300  363.600 58.300  363.600 76.300  366.200 76.300  366.200 58.300  374.700 58.300  374.700 71.300  377.300 71.300  377.300 58.300  379.000 58.300  379.000 93.300  381.600 93.300  381.600 58.300  385.200 58.300  385.200 76.300  387.800 76.300  387.800 58.300  389.800 58.300  389.800 93.300  392.400 93.300  392.400 58.300  396.000 58.300  396.000 76.300  398.600 76.300  398.600 58.300  407.100 58.300  407.100 71.300  409.700 71.300  409.700 58.300  411.400 58.300  411.400 93.300  414.000 93.300  414.000 58.300  417.600 58.300  417.600 76.300  420.200 76.300  420.200 58.300  422.200 58.300  422.200 93.300  424.800 93.300  424.800 58.300  428.400 58.300  428.400 76.300  431.000 76.300  431.000 58.300  439.500 58.300  439.500 71.300  442.100 71.300  442.100 58.300  443.800 58.300  443.800 93.300  446.400 93.300  446.400 58.300  450.000 58.300  450.000 76.300  452.600 76.300  452.600 58.300  454.600 58.300  454.600 93.300  457.200 93.300  457.200 58.300  460.800 58.300  460.800 76.300  463.400 76.300  463.400 58.300  471.900 58.300  471.900 71.300  474.500 71.300  474.500 58.300  476.200 58.300  476.200 93.300  478.800 93.300  478.800 58.300  482.400 58.300  482.400 76.300  485.000 76.300  485.000 58.300  487.000 58.300  487.000 93.300  489.600 93.300  489.600 58.300  493.200 58.300  493.200 76.300  495.800 76.300  495.800 58.300  504.300 58.300  504.300 71.300  506.900 71.300  506.900 58.300  508.600 58.300  508.600 93.300  511.200 93.300  511.200 58.300  514.800 58.300  514.800 76.300  517.400 76.300  517.400 58.300  519.400 58.300  519.400 93.300  522.000 93.300  522.000 58.300  525.600 58.300  525.600 76.300  528.200 76.300  528.200 58.300  536.700 58.300  536.700 71.300  539.300 71.300  539.300 58.300  541.000 58.300  541.000 93.300  543.600 93.300  543.600 58.300  547.200 58.300  547.200 76.300  549.800 76.300  549.800 58.300  551.800 58.300  551.800 93.300  554.400 93.300  554.400 58.300  558.000 58.300  558.000 76.300  560.600 76.300  560.600 58.300  569.100 58.300  569.100 71.300  571.700 71.300  571.700 58.300  573.400 58.300  573.400 93.300  576.000 93.300  576.000 58.300  579.600 58.300  579.600 76.300  582.200 76.300  582.200 58.300  584.200 58.300  584.200 93.300  586.800 93.300  586.800 58.300  590.400 58.300  590.400 76.300  593.000 76.300  593.000 58.300  601.500 58.300  601.500 71.300  604.100 71.300  604.100 58.300  605.800 58.300  605.800 93.300  608.400 93.300  608.400 58.300  612.000 58.300  612.000 76.300  614.600 76.300  614.600 58.300  616.600 58.300  616.600 93.300  619.200 93.300  619.200 58.300  622.800 58.300  622.800 76.300  625.400 76.300  625.400 58.300  633.900 58.300  633.900 71.300  636.500 71.300  636.500 58.300  638.200 58.300  638.200 93.300  640.800 93.300  640.800 58.300  644.400 58.300  644.400 76.300  647.000 76.300  647.000 58.300  649.000 58.300  649.000 93.300  651.600 93.300  651.600 58.300  655.200 58.300  655.200 76.300  657.800 76.300  657.800 58.300  666.300 58.300  666.300 71.300  668.900 71.300  668.900 58.300  670.600 58.300  670.600 93.300  673.200 93.300  673.200 58.300  676.800 58.300  676.800 76.300  679.400 76.300  679.400 58.300  681.400 58.300  681.400 93.300  684.000 93.300  684.000 58.300  687.600 58.300  687.600 76.300  690.200 76.300  690.200 58.300  698.700 58.300  698.700 71.300  701.300 71.300  701.300 58.300  703.000 58.300  703.000 93.300  705.600 93.300  705.600 58.300  709.200 58.300  709.200 76.300  711.800 76.300  711.800 58.300  713.800 58.300  713.800 93.300  716.400 93.300  716.400 58.300  720.000 58.300  720.000 76.300  722.600 76.300  722.600 58.300  731.100 58.300  731.100 71.300  733.700 71.300  733.700 58.300  735.400 58.300  735.400 93.300  738.000 93.300  738.000 58.300  741.600 58.300  741.600 76.300  744.200 76.300  744.200 58.300  746.200 58.300  746.200 93.300  748.800 93.300  748.800 58.300  752.400 58.300  752.400 76.300  755.000 76.300  755.000 58.300  763.500 58.300  763.500 71.300  766.100 71.300  766.100 58.300  767.800 58.300  767.800 93.300  770.400 93.300  770.400 58.300  774.000 58.300  774.000 76.300  776.600 76.300  776.600 58.300  778.600 58.300  778.600 93.300  781.200 93.300  781.200 58.300  784.800 58.300  784.800 76.300  787.400 76.300  787.400 58.300  795.900 58.300  795.900 71.300  798.500 71.300  798.500 58.300  800.200 58.300  800.200 93.300  802.800 93.300  802.800 58.300  806.400 58.300  806.400 76.300  809.000 76.300  809.000 58.300  811.000 58.300  811.000 93.300  813.600 93.300  813.600 58.300  817.200 58.300  817.200 76.300  819.800 76.300  819.800 58.300  828.300 58.300  828.300 71.300  830.900 71.300  830.900 58.300  832.600 58.300  832.600 93.300  835.200 93.300  835.200 58.300  838.800 58.300  838.800 76.300  841.400 76.300  841.400 58.300  843.400 58.300  843.400 93.300  846.000 93.300  846.000 58.300  849.600 58.300  849.600 76.300  852.200 76.300  852.200 58.300  860.700 58.300  860.700 71.300  863.300 71.300  863.300 58.300  865.000 58.300  865.000 93.300  867.600 93.300  867.600 58.300  871.200 58.300  871.200 76.300  873.800 76.300  873.800 58.300  875.800 58.300  875.800 93.300  878.400 93.300  878.400 58.300  882.000 58.300  882.000 76.300  884.600 76.300  884.600 58.300  893.100 58.300  893.100 71.300  895.700 71.300  895.700 58.300  897.400 58.300  897.400 93.300  900.000 93.300  900.000 58.300  903.600 58.300  903.600 76.300  906.200 76.300  906.200 58.300  908.200 58.300  908.200 93.300  910.800 93.300  910.800 58.300  914.400 58.300  914.400 76.300  917.000 76.300  917.000 58.300  925.500 58.300  925.500 71.300  928.100 71.300  928.100 58.300  929.800 58.300  929.800 93.300  932.400 93.300  932.400 58.300  936.000 58.300  936.000 76.300  938.600 76.300  938.600 58.300  940.600 58.300  940.600 93.300  943.200 93.300  943.200 58.300  946.800 58.300  946.800 76.300  949.400 76.300  949.400 58.300  957.900 58.300  957.900 71.300  960.500 71.300  960.500 58.300  962.200 58.300  962.200 93.300  964.800 93.300  964.800 58.300  968.400 58.300  968.400 76.300  971.000 76.300  971.000 58.300  973.000 58.300  973.000 93.300  975.600 93.300  975.600 58.300  979.200 58.300  979.200 76.300  981.800 76.300  981.800 58.300  990.300 58.300  990.300 71.300  992.900 71.300  992.900 58.300  994.600 58.300  994.600 93.300  997.200 93.300  997.200 58.300  1000.800 58.300  1000.800 76.300  1003.400 76.300  1003.400 58.300  1005.400 58.300  1005.400 93.300  1008.000 93.300  1008.000 58.300  1011.600 58.300  1011.600 76.300  1014.200 76.300  1014.200 58.300  1022.700 58.300  1022.700 71.300  1025.300 71.300  1025.300 58.300  1027.000 58.300  1027.000 93.300  1029.600 93.300  1029.600 58.300  1033.200 58.300  1033.200 76.300  1035.800 76.300  1035.800 58.300  1037.800 58.300  1037.800 93.300  1040.400 93.300  1040.400 58.300  1044.000 58.300  1044.000 76.300  1046.600 76.300  1046.600 58.300  1055.100 58.300  1055.100 71.300  1057.700 71.300  1057.700 58.300  1059.400 58.300  1059.400 93.300  1062.000 93.300  1062.000 58.300  1065.600 58.300  1065.600 76.300  1068.200 76.300  1068.200 58.300  1070.200 58.300  1070.200 93.300  1072.800 93.300  1072.800 58.300  1076.400 58.300  1076.400 76.300  1079.000 76.300  1079.000 58.300  1087.500 58.300  1087.500 71.300  1090.100 71.300  1090.100 58.300  1091.800 58.300  1091.800 93.300  1094.400 93.300  1094.400 58.300  1098.000 58.300  1098.000 76.300  1100.600 76.300  1100.600 58.300  1102.600 58.300  1102.600 93.300  1105.200 93.300  1105.200 58.300  1108.800 58.300  1108.800 76.300  1111.400 76.300  1111.400 58.300  1119.900 58.300  1119.900 71.300  1122.500 71.300  1122.500 58.300  1124.200 58.300  1124.200 93.300  1126.800 93.300  1126.800 58.300  1130.400 58.300  1130.400 76.300  1133.000 76.300  1133.000 58.300  1135.000 58.300  1135.000 93.300  1137.600 93.300  1137.600 58.300  1141.200 58.300  1141.200 76.300  1143.800 76.300  1143.800 58.300  1152.300 58.300  1152.300 71.300  1154.900 71.300  1154.900 58.300  1156.600 58.300  1156.600 93.300  1159.200 93.300  1159.200 58.300  1162.800 58.300  1162.800 76.300  1165.400 76.300  1165.400 58.300  1167.400 58.300  1167.400 93.300  1170.000 93.300  1170.000 58.300  1173.600 58.300  1173.600 76.300  1176.200 76.300  1176.200 58.300  1184.700 58.300  1184.700 71.300  1187.300 71.300  1187.300 58.300  1189.000 58.300  1189.000 93.300  1191.600 93.300  1191.600 58.300  1195.200 58.300  1195.200 76.300  1197.800 76.300  1197.800 58.300  1199.800 58.300  1199.800 93.300  1202.400 93.300  1202.400 58.300  1206.000 58.300  1206.000 76.300  1208.600 76.300  1208.600 58.300  1217.100 58.300  1217.100 71.300  1219.700 71.300  1219.700 58.300  1221.400 58.300  1221.400 93.300  1224.000 93.300  1224.000 58.300  1227.600 58.300  1227.600 76.300  1230.200 76.300  1230.200 58.300  1232.200 58.300  1232.200 93.300  1234.800 93.300  1234.800 58.300  1238.400 58.300  1238.400 76.300  1241.000 76.300  1241.000 58.300  1249.500 58.300  1249.500 71.300  1252.100 71.300  1252.100 58.300  1253.800 58.300  1253.800 93.300  1256.400 93.300  1256.400 58.300  1260.000 58.300  1260.000 76.300  1262.600 76.300  1262.600 58.300  1264.600 58.300  1264.600 93.300  1267.200 93.300  1267.200 58.300  1270.800 58.300  1270.800 76.300  1273.400 76.300  1273.400 58.300  1281.900 58.300  1281.900 71.300  1284.500 71.300  1284.500 58.300  1286.200 58.300  1286.200 93.300  1288.800 93.300  1288.800 58.300  1292.400 58.300  1292.400 76.300  1295.000 76.300  1295.000 58.300  1297.000 58.300  1297.000 93.300  1299.600 93.300  1299.600 58.300  1303.200 58.300  1303.200 76.300  1305.800 76.300  1305.800 58.300  1314.300 58.300  1314.300 71.300  1316.900 71.300  1316.900 58.300  1318.600 58.300  1318.600 93.300  1321.200 93.300  1321.200 58.300  1324.800 58.300  1324.800 76.300  1327.400 76.300  1327.400 58.300  1329.400 58.300  1329.400 93.300  1332.000 93.300  1332.000 58.300  1335.600 58.300  1335.600 76.300  1338.200 76.300  1338.200 58.300  1346.700 58.300  1346.700 71.300  1349.300 71.300  1349.300 58.300  1351.000 58.300  1351.000 93.300  1353.600 93.300  1353.600 58.300  1357.200 58.300  1357.200 76.300  1359.800 76.300  1359.800 58.300  1361.800 58.300  1361.800 93.300  1364.400 93.300  1364.400 58.300  1368.000 58.300  1368.000 76.300  1370.600 76.300  1370.600 58.300  1379.100 58.300  1379.100 71.300  1381.700 71.300  1381.700 58.300  1383.400 58.300  1383.400 93.300  1386.000 93.300  1386.000 58.300  1389.600 58.300  1389.600 76.300  1392.200 76.300  1392.200 58.300  1394.200 58.300  1394.200 93.300  1396.800 93.300  1396.800 58.300  1400.400 58.300  1400.400 76.300  1403.000 76.300  1403.000 58.300  1411.500 58.300  1411.500 71.300  1414.100 71.300  1414.100 58.300  1415.800 58.300  1415.800 93.300  1418.400 93.300  1418.400 58.300  1422.000 58.300  1422.000 76.300  1424.600 76.300  1424.600 58.300  1426.600 58.300  1426.600 93.300  1429.200 93.300  1429.200 58.300  1432.800 58.300  1432.800 76.300  1435.400 76.300  1435.400 58.300  1443.900 58.300  1443.900 71.300  1446.500 71.300  1446.500 58.300  1448.200 58.300  1448.200 93.300  1450.800 93.300  1450.800 58.300  1454.400 58.300  1454.400 76.300  1457.000 76.300  1457.000 58.300  1459.000 58.300  1459.000 93.300  1461.600 93.300  1461.600 58.300  1465.200 58.300  1465.200 76.300  1467.800 76.300  1467.800 58.300  1476.300 58.300  1476.300 71.300  1478.900 71.300  1478.900 58.300  1480.600 58.300  1480.600 93.300  1483.200 93.300  1483.200 58.300  1486.800 58.300  1486.800 76.300  1489.400 76.300  1489.400 58.300  1491.400 58.300  1491.400 93.300  1494.000 93.300  1494.000 58.300  1497.600 58.300  1497.600 76.300  1500.200 76.300  1500.200 58.300  1508.700 58.300  1508.700 71.300  1511.300 71.300  1511.300 58.300  1513.000 58.300  1513.000 93.300  1515.600 93.300  1515.600 58.300  1519.200 58.300  1519.200 76.300  1521.800 76.300  1521.800 58.300  1523.800 58.300  1523.800 93.300  1526.400 93.300  1526.400 58.300  1530.000 58.300  1530.000 76.300  1532.600 76.300  1532.600 58.300  1541.100 58.300  1541.100 71.300  1543.700 71.300  1543.700 58.300  1545.400 58.300  1545.400 93.300  1548.000 93.300  1548.000 58.300  1551.600 58.300  1551.600 76.300  1554.200 76.300  1554.200 58.300  1556.200 58.300  1556.200 93.300  1558.800 93.300  1558.800 58.300  1562.400 58.300  1562.400 76.300  1565.000 76.300  1565.000 58.300  1573.500 58.300  1573.500 71.300  1576.100 71.300  1576.100 58.300  1577.800 58.300  1577.800 93.300  1580.400 93.300  1580.400 58.300  1584.000 58.300  1584.000 76.300  1586.600 76.300  1586.600 58.300  1588.600 58.300  1588.600 93.300  1591.200 93.300  1591.200 58.300  1594.800 58.300  1594.800 76.300  1597.400 76.300  1597.400 58.300  1605.900 58.300  1605.900 71.300  1608.500 71.300  1608.500 58.300  1615.600 58.300  1615.600 60.900  1619.000 60.900  1619.000 58.300  1617.400 58.300  1617.400 55.700  1619.000 55.700  1619.000 53.100  1615.600 53.100  1615.600 55.700  1601.700 55.700  1601.700 42.700  1599.100 42.700  1599.100 55.700  1597.400 55.700  1597.400 20.700  1594.800 20.700  1594.800 55.700  1591.200 55.700  1591.200 37.700  1588.600 37.700  1588.600 55.700  1586.600 55.700  1586.600 20.700  1584.000 20.700  1584.000 55.700  1580.400 55.700  1580.400 37.700  1577.800 37.700  1577.800 55.700  1575.800 55.700  1575.800 20.700  1573.200 20.700  1573.200 55.700  1569.600 55.700  1569.600 37.700  1567.000 37.700  1567.000 55.700  1565.000 55.700  1565.000 20.700  1562.400 20.700  1562.400 55.700  1558.800 55.700  1558.800 37.700  1556.200 37.700  1556.200 55.700  1554.200 55.700  1554.200 20.700  1551.600 20.700  1551.600 55.700  1548.000 55.700  1548.000 37.700  1545.400 37.700  1545.400 55.700  1543.400 55.700  1543.400 20.700  1540.800 20.700  1540.800 55.700  1537.200 55.700  1537.200 37.700  1534.600 37.700  1534.600 55.700  1523.300 55.700  1523.300 42.700  1520.700 42.700  1520.700 55.700  1515.300 55.700  1515.300 42.700  1512.700 42.700  1512.700 55.700  1511.000 55.700  1511.000 20.700  1508.400 20.700  1508.400 55.700  1504.800 55.700  1504.800 37.700  1502.200 37.700  1502.200 55.700  1500.200 55.700  1500.200 20.700  1497.600 20.700  1497.600 55.700  1494.000 55.700  1494.000 37.700  1491.400 37.700  1491.400 55.700  1482.900 55.700  1482.900 42.700  1480.300 42.700  1480.300 55.700  1478.600 55.700  1478.600 20.700  1476.000 20.700  1476.000 55.700  1472.400 55.700  1472.400 37.700  1469.800 37.700  1469.800 55.700  1467.800 55.700  1467.800 20.700  1465.200 20.700  1465.200 55.700  1461.600 55.700  1461.600 37.700  1459.000 37.700  1459.000 55.700  1450.500 55.700  1450.500 42.700  1447.900 42.700  1447.900 55.700  1446.200 55.700  1446.200 20.700  1443.600 20.700  1443.600 55.700  1440.000 55.700  1440.000 37.700  1437.400 37.700  1437.400 55.700  1435.400 55.700  1435.400 20.700  1432.800 20.700  1432.800 55.700  1429.200 55.700  1429.200 37.700  1426.600 37.700  1426.600 55.700  1418.100 55.700  1418.100 42.700  1415.500 42.700  1415.500 55.700  1413.800 55.700  1413.800 20.700  1411.200 20.700  1411.200 55.700  1407.600 55.700  1407.600 37.700  1405.000 37.700  1405.000 55.700  1403.000 55.700  1403.000 20.700  1400.400 20.700  1400.400 55.700  1396.800 55.700  1396.800 37.700  1394.200 37.700  1394.200 55.700  1385.700 55.700  1385.700 42.700  1383.100 42.700  1383.100 55.700  1381.400 55.700  1381.400 20.700  1378.800 20.700  1378.800 55.700  1375.200 55.700  1375.200 37.700  1372.600 37.700  1372.600 55.700  1370.600 55.700  1370.600 20.700  1368.000 20.700  1368.000 55.700  1364.400 55.700  1364.400 37.700  1361.800 37.700  1361.800 55.700  1353.300 55.700  1353.300 42.700  1350.700 42.700  1350.700 55.700  1349.000 55.700  1349.000 20.700  1346.400 20.700  1346.400 55.700  1342.800 55.700  1342.800 37.700  1340.200 37.700  1340.200 55.700  1338.200 55.700  1338.200 20.700  1335.600 20.700  1335.600 55.700  1332.000 55.700  1332.000 37.700  1329.400 37.700  1329.400 55.700  1320.900 55.700  1320.900 42.700  1318.300 42.700  1318.300 55.700  1316.600 55.700  1316.600 20.700  1314.000 20.700  1314.000 55.700  1310.400 55.700  1310.400 37.700  1307.800 37.700  1307.800 55.700  1305.800 55.700  1305.800 20.700  1303.200 20.700  1303.200 55.700  1299.600 55.700  1299.600 37.700  1297.000 37.700  1297.000 55.700  1288.500 55.700  1288.500 42.700  1285.900 42.700  1285.900 55.700  1284.200 55.700  1284.200 20.700  1281.600 20.700  1281.600 55.700  1278.000 55.700  1278.000 37.700  1275.400 37.700  1275.400 55.700  1273.400 55.700  1273.400 20.700  1270.800 20.700  1270.800 55.700  1267.200 55.700  1267.200 37.700  1264.600 37.700  1264.600 55.700  1256.100 55.700  1256.100 42.700  1253.500 42.700  1253.500 55.700  1251.800 55.700  1251.800 20.700  1249.200 20.700  1249.200 55.700  1245.600 55.700  1245.600 37.700  1243.000 37.700  1243.000 55.700  1241.000 55.700  1241.000 20.700  1238.400 20.700  1238.400 55.700  1234.800 55.700  1234.800 37.700  1232.200 37.700  1232.200 55.700  1223.700 55.700  1223.700 42.700  1221.100 42.700  1221.100 55.700  1219.400 55.700  1219.400 20.700  1216.800 20.700  1216.800 55.700  1213.200 55.700  1213.200 37.700  1210.600 37.700  1210.600 55.700  1208.600 55.700  1208.600 20.700  1206.000 20.700  1206.000 55.700  1202.400 55.700  1202.400 37.700  1199.800 37.700  1199.800 55.700  1191.300 55.700  1191.300 42.700  1188.700 42.700  1188.700 55.700  1187.000 55.700  1187.000 20.700  1184.400 20.700  1184.400 55.700  1180.800 55.700  1180.800 37.700  1178.200 37.700  1178.200 55.700  1176.200 55.700  1176.200 20.700  1173.600 20.700  1173.600 55.700  1170.000 55.700  1170.000 37.700  1167.400 37.700  1167.400 55.700  1158.900 55.700  1158.900 42.700  1156.300 42.700  1156.300 55.700  1154.600 55.700  1154.600 20.700  1152.000 20.700  1152.000 55.700  1148.400 55.700  1148.400 37.700  1145.800 37.700  1145.800 55.700  1143.800 55.700  1143.800 20.700  1141.200 20.700  1141.200 55.700  1137.600 55.700  1137.600 37.700  1135.000 37.700  1135.000 55.700  1126.500 55.700  1126.500 42.700  1123.900 42.700  1123.900 55.700  1122.200 55.700  1122.200 20.700  1119.600 20.700  1119.600 55.700  1116.000 55.700  1116.000 37.700  1113.400 37.700  1113.400 55.700  1111.400 55.700  1111.400 20.700  1108.800 20.700  1108.800 55.700  1105.200 55.700  1105.200 37.700  1102.600 37.700  1102.600 55.700  1094.100 55.700  1094.100 42.700  1091.500 42.700  1091.500 55.700  1089.800 55.700  1089.800 20.700  1087.200 20.700  1087.200 55.700  1083.600 55.700  1083.600 37.700  1081.000 37.700  1081.000 55.700  1079.000 55.700  1079.000 20.700  1076.400 20.700  1076.400 55.700  1072.800 55.700  1072.800 37.700  1070.200 37.700  1070.200 55.700  1061.700 55.700  1061.700 42.700  1059.100 42.700  1059.100 55.700  1057.400 55.700  1057.400 20.700  1054.800 20.700  1054.800 55.700  1051.200 55.700  1051.200 37.700  1048.600 37.700  1048.600 55.700  1046.600 55.700  1046.600 20.700  1044.000 20.700  1044.000 55.700  1040.400 55.700  1040.400 37.700  1037.800 37.700  1037.800 55.700  1029.300 55.700  1029.300 42.700  1026.700 42.700  1026.700 55.700  1025.000 55.700  1025.000 20.700  1022.400 20.700  1022.400 55.700  1018.800 55.700  1018.800 37.700  1016.200 37.700  1016.200 55.700  1014.200 55.700  1014.200 20.700  1011.600 20.700  1011.600 55.700  1008.000 55.700  1008.000 37.700  1005.400 37.700  1005.400 55.700  996.900 55.700  996.900 42.700  994.300 42.700  994.300 55.700  992.600 55.700  992.600 20.700  990.000 20.700  990.000 55.700  986.400 55.700  986.400 37.700  983.800 37.700  983.800 55.700  981.800 55.700  981.800 20.700  979.200 20.700  979.200 55.700  975.600 55.700  975.600 37.700  973.000 37.700  973.000 55.700  964.500 55.700  964.500 42.700  961.900 42.700  961.900 55.700  960.200 55.700  960.200 20.700  957.600 20.700  957.600 55.700  954.000 55.700  954.000 37.700  951.400 37.700  951.400 55.700  949.400 55.700  949.400 20.700  946.800 20.700  946.800 55.700  943.200 55.700  943.200 37.700  940.600 37.700  940.600 55.700  932.100 55.700  932.100 42.700  929.500 42.700  929.500 55.700  927.800 55.700  927.800 20.700  925.200 20.700  925.200 55.700  921.600 55.700  921.600 37.700  919.000 37.700  919.000 55.700  917.000 55.700  917.000 20.700  914.400 20.700  914.400 55.700  910.800 55.700  910.800 37.700  908.200 37.700  908.200 55.700  899.700 55.700  899.700 42.700  897.100 42.700  897.100 55.700  895.400 55.700  895.400 20.700  892.800 20.700  892.800 55.700  889.200 55.700  889.200 37.700  886.600 37.700  886.600 55.700  884.600 55.700  884.600 20.700  882.000 20.700  882.000 55.700  878.400 55.700  878.400 37.700  875.800 37.700  875.800 55.700  867.300 55.700  867.300 42.700  864.700 42.700  864.700 55.700  863.000 55.700  863.000 20.700  860.400 20.700  860.400 55.700  856.800 55.700  856.800 37.700  854.200 37.700  854.200 55.700  852.200 55.700  852.200 20.700  849.600 20.700  849.600 55.700  846.000 55.700  846.000 37.700  843.400 37.700  843.400 55.700  834.900 55.700  834.900 42.700  832.300 42.700  832.300 55.700  830.600 55.700  830.600 20.700  828.000 20.700  828.000 55.700  824.400 55.700  824.400 37.700  821.800 37.700  821.800 55.700  819.800 55.700  819.800 20.700  817.200 20.700  817.200 55.700  813.600 55.700  813.600 37.700  811.000 37.700  811.000 55.700  802.500 55.700  802.500 42.700  799.900 42.700  799.900 55.700  798.200 55.700  798.200 20.700  795.600 20.700  795.600 55.700  792.000 55.700  792.000 37.700  789.400 37.700  789.400 55.700  787.400 55.700  787.400 20.700  784.800 20.700  784.800 55.700  781.200 55.700  781.200 37.700  778.600 37.700  778.600 55.700  770.100 55.700  770.100 42.700  767.500 42.700  767.500 55.700  765.800 55.700  765.800 20.700  763.200 20.700  763.200 55.700  759.600 55.700  759.600 37.700  757.000 37.700  757.000 55.700  755.000 55.700  755.000 20.700  752.400 20.700  752.400 55.700  748.800 55.700  748.800 37.700  746.200 37.700  746.200 55.700  737.700 55.700  737.700 42.700  735.100 42.700  735.100 55.700  733.400 55.700  733.400 20.700  730.800 20.700  730.800 55.700  727.200 55.700  727.200 37.700  724.600 37.700  724.600 55.700  722.600 55.700  722.600 20.700  720.000 20.700  720.000 55.700  716.400 55.700  716.400 37.700  713.800 37.700  713.800 55.700  705.300 55.700  705.300 42.700  702.700 42.700  702.700 55.700  701.000 55.700  701.000 20.700  698.400 20.700  698.400 55.700  694.800 55.700  694.800 37.700  692.200 37.700  692.200 55.700  690.200 55.700  690.200 20.700  687.600 20.700  687.600 55.700  684.000 55.700  684.000 37.700  681.400 37.700  681.400 55.700  672.900 55.700  672.900 42.700  670.300 42.700  670.300 55.700  668.600 55.700  668.600 20.700  666.000 20.700  666.000 55.700  662.400 55.700  662.400 37.700  659.800 37.700  659.800 55.700  657.800 55.700  657.800 20.700  655.200 20.700  655.200 55.700  651.600 55.700  651.600 37.700  649.000 37.700  649.000 55.700  640.500 55.700  640.500 42.700  637.900 42.700  637.900 55.700  636.200 55.700  636.200 20.700  633.600 20.700  633.600 55.700  630.000 55.700  630.000 37.700  627.400 37.700  627.400 55.700  625.400 55.700  625.400 20.700  622.800 20.700  622.800 55.700  619.200 55.700  619.200 37.700  616.600 37.700  616.600 55.700  608.100 55.700  608.100 42.700  605.500 42.700  605.500 55.700  603.800 55.700  603.800 20.700  601.200 20.700  601.200 55.700  597.600 55.700  597.600 37.700  595.000 37.700  595.000 55.700  593.000 55.700  593.000 20.700  590.400 20.700  590.400 55.700  586.800 55.700  586.800 37.700  584.200 37.700  584.200 55.700  575.700 55.700  575.700 42.700  573.100 42.700  573.100 55.700  571.400 55.700  571.400 20.700  568.800 20.700  568.800 55.700  565.200 55.700  565.200 37.700  562.600 37.700  562.600 55.700  560.600 55.700  560.600 20.700  558.000 20.700  558.000 55.700  554.400 55.700  554.400 37.700  551.800 37.700  551.800 55.700  543.300 55.700  543.300 42.700  540.700 42.700  540.700 55.700  539.000 55.700  539.000 20.700  536.400 20.700  536.400 55.700  532.800 55.700  532.800 37.700  530.200 37.700  530.200 55.700  528.200 55.700  528.200 20.700  525.600 20.700  525.600 55.700  522.000 55.700  522.000 37.700  519.400 37.700  519.400 55.700  510.900 55.700  510.900 42.700  508.300 42.700  508.300 55.700  506.600 55.700  506.600 20.700  504.000 20.700  504.000 55.700  500.400 55.700  500.400 37.700  497.800 37.700  497.800 55.700  495.800 55.700  495.800 20.700  493.200 20.700  493.200 55.700  489.600 55.700  489.600 37.700  487.000 37.700  487.000 55.700  478.500 55.700  478.500 42.700  475.900 42.700  475.900 55.700  474.200 55.700  474.200 20.700  471.600 20.700  471.600 55.700  468.000 55.700  468.000 37.700  465.400 37.700  465.400 55.700  463.400 55.700  463.400 20.700  460.800 20.700  460.800 55.700  457.200 55.700  457.200 37.700  454.600 37.700  454.600 55.700  446.100 55.700  446.100 42.700  443.500 42.700  443.500 55.700  441.800 55.700  441.800 20.700  439.200 20.700  439.200 55.700  435.600 55.700  435.600 37.700  433.000 37.700  433.000 55.700  431.000 55.700  431.000 20.700  428.400 20.700  428.400 55.700  424.800 55.700  424.800 37.700  422.200 37.700  422.200 55.700  413.700 55.700  413.700 42.700  411.100 42.700  411.100 55.700  409.400 55.700  409.400 20.700  406.800 20.700  406.800 55.700  403.200 55.700  403.200 37.700  400.600 37.700  400.600 55.700  398.600 55.700  398.600 20.700  396.000 20.700  396.000 55.700  392.400 55.700  392.400 37.700  389.800 37.700  389.800 55.700  381.300 55.700  381.300 42.700  378.700 42.700  378.700 55.700  377.000 55.700  377.000 20.700  374.400 20.700  374.400 55.700  370.800 55.700  370.800 37.700  368.200 37.700  368.200 55.700  366.200 55.700  366.200 20.700  363.600 20.700  363.600 55.700  360.000 55.700  360.000 37.700  357.400 37.700  357.400 55.700  348.900 55.700  348.900 42.700  346.300 42.700  346.300 55.700  344.600 55.700  344.600 20.700  342.000 20.700  342.000 55.700  338.400 55.700  338.400 37.700  335.800 37.700  335.800 55.700  333.800 55.700  333.800 20.700  331.200 20.700  331.200 55.700  327.600 55.700  327.600 37.700  325.000 37.700  325.000 55.700  316.500 55.700  316.500 42.700  313.900 42.700  313.900 55.700  312.200 55.700  312.200 20.700  309.600 20.700  309.600 55.700  306.000 55.700  306.000 37.700  303.400 37.700  303.400 55.700  301.400 55.700  301.400 20.700  298.800 20.700  298.800 55.700  295.200 55.700  295.200 37.700  292.600 37.700  292.600 55.700  284.100 55.700  284.100 42.700  281.500 42.700  281.500 55.700  279.800 55.700  279.800 20.700  277.200 20.700  277.200 55.700  273.600 55.700  273.600 37.700  271.000 37.700  271.000 55.700  269.000 55.700  269.000 20.700  266.400 20.700  266.400 55.700  262.800 55.700  262.800 37.700  260.200 37.700  260.200 55.700  251.700 55.700  251.700 42.700  249.100 42.700  249.100 55.700  247.400 55.700  247.400 20.700  244.800 20.700  244.800 55.700  241.200 55.700  241.200 37.700  238.600 37.700  238.600 55.700  236.600 55.700  236.600 20.700  234.000 20.700  234.000 55.700  230.400 55.700  230.400 37.700  227.800 37.700  227.800 55.700  219.300 55.700  219.300 42.700  216.700 42.700  216.700 55.700  215.000 55.700  215.000 20.700  212.400 20.700  212.400 55.700  208.800 55.700  208.800 37.700  206.200 37.700  206.200 55.700  204.200 55.700  204.200 20.700  201.600 20.700  201.600 55.700  198.000 55.700  198.000 37.700  195.400 37.700  195.400 55.700  186.900 55.700  186.900 42.700  184.300 42.700  184.300 55.700  182.600 55.700  182.600 20.700  180.000 20.700  180.000 55.700  176.400 55.700  176.400 37.700  173.800 37.700  173.800 55.700  171.800 55.700  171.800 20.700  169.200 20.700  169.200 55.700  165.600 55.700  165.600 37.700  163.000 37.700  163.000 55.700  154.500 55.700  154.500 42.700  151.900 42.700  151.900 55.700  150.200 55.700  150.200 20.700  147.600 20.700  147.600 55.700  144.000 55.700  144.000 37.700  141.400 37.700  141.400 55.700  139.400 55.700  139.400 20.700  136.800 20.700  136.800 55.700  133.200 55.700  133.200 37.700  130.600 37.700  130.600 55.700  122.100 55.700  122.100 42.700  119.500 42.700  119.500 55.700  117.800 55.700  117.800 20.700  115.200 20.700  115.200 55.700  111.600 55.700  111.600 37.700  109.000 37.700  109.000 55.700  107.000 55.700  107.000 20.700  104.400 20.700  104.400 55.700  100.800 55.700  100.800 37.700  98.200 37.700  98.200 55.700  89.700 55.700  89.700 42.700  87.100 42.700  87.100 55.700  85.400 55.700  85.400 20.700  82.800 20.700  82.800 55.700  79.200 55.700  79.200 37.700  76.600 37.700  76.600 55.700  74.600 55.700  74.600 20.700  72.000 20.700  72.000 55.700  68.400 55.700  68.400 37.700  65.800 37.700  65.800 55.700  57.300 55.700  57.300 42.700  54.700 42.700  54.700 55.700  53.000 55.700  53.000 20.700  50.400 20.700  50.400 55.700  46.800 55.700  46.800 37.700  44.200 37.700  44.200 55.700  42.200 55.700  42.200 20.700  39.600 20.700  39.600 55.700  36.000 55.700  36.000 37.700  33.400 37.700  33.400 55.700  24.900 55.700  24.900 42.700  22.300 42.700  22.300 55.700  20.600 55.700  20.600 20.700 ;
            POLYGON 18.000 77.900  18.000 110.300  14.400 110.300  14.400 94.900  11.800 94.900  11.800 110.300  4.400 110.300  4.400 107.700  1.000 107.700  1.000 110.300  2.600 110.300  2.600 112.900  1617.400 112.900  1617.400 110.300  1613.600 110.300  1613.600 107.700  1610.200 107.700  1610.200 110.300  1607.100 110.300  1607.100 104.100  1604.500 104.100  1604.500 110.300  1597.400 110.300  1597.400 77.900  1594.800 77.900  1594.800 110.300  1591.200 110.300  1591.200 94.900  1588.600 94.900  1588.600 110.300  1586.600 110.300  1586.600 77.900  1584.000 77.900  1584.000 110.300  1580.400 110.300  1580.400 94.900  1577.800 94.900  1577.800 110.300  1574.700 110.300  1574.700 104.100  1572.100 104.100  1572.100 110.300  1565.000 110.300  1565.000 77.900  1562.400 77.900  1562.400 110.300  1558.800 110.300  1558.800 94.900  1556.200 94.900  1556.200 110.300  1554.200 110.300  1554.200 77.900  1551.600 77.900  1551.600 110.300  1548.000 110.300  1548.000 94.900  1545.400 94.900  1545.400 110.300  1542.300 110.300  1542.300 104.100  1539.700 104.100  1539.700 110.300  1532.600 110.300  1532.600 77.900  1530.000 77.900  1530.000 110.300  1526.400 110.300  1526.400 94.900  1523.800 94.900  1523.800 110.300  1521.800 110.300  1521.800 77.900  1519.200 77.900  1519.200 110.300  1515.600 110.300  1515.600 94.900  1513.000 94.900  1513.000 110.300  1509.900 110.300  1509.900 104.100  1507.300 104.100  1507.300 110.300  1500.200 110.300  1500.200 77.900  1497.600 77.900  1497.600 110.300  1494.000 110.300  1494.000 94.900  1491.400 94.900  1491.400 110.300  1489.400 110.300  1489.400 77.900  1486.800 77.900  1486.800 110.300  1483.200 110.300  1483.200 94.900  1480.600 94.900  1480.600 110.300  1477.500 110.300  1477.500 104.100  1474.900 104.100  1474.900 110.300  1467.800 110.300  1467.800 77.900  1465.200 77.900  1465.200 110.300  1461.600 110.300  1461.600 94.900  1459.000 94.900  1459.000 110.300  1457.000 110.300  1457.000 77.900  1454.400 77.900  1454.400 110.300  1450.800 110.300  1450.800 94.900  1448.200 94.900  1448.200 110.300  1445.100 110.300  1445.100 104.100  1442.500 104.100  1442.500 110.300  1435.400 110.300  1435.400 77.900  1432.800 77.900  1432.800 110.300  1429.200 110.300  1429.200 94.900  1426.600 94.900  1426.600 110.300  1424.600 110.300  1424.600 77.900  1422.000 77.900  1422.000 110.300  1418.400 110.300  1418.400 94.900  1415.800 94.900  1415.800 110.300  1412.700 110.300  1412.700 104.100  1410.100 104.100  1410.100 110.300  1403.000 110.300  1403.000 77.900  1400.400 77.900  1400.400 110.300  1396.800 110.300  1396.800 94.900  1394.200 94.900  1394.200 110.300  1392.200 110.300  1392.200 77.900  1389.600 77.900  1389.600 110.300  1386.000 110.300  1386.000 94.900  1383.400 94.900  1383.400 110.300  1380.300 110.300  1380.300 104.100  1377.700 104.100  1377.700 110.300  1370.600 110.300  1370.600 77.900  1368.000 77.900  1368.000 110.300  1364.400 110.300  1364.400 94.900  1361.800 94.900  1361.800 110.300  1359.800 110.300  1359.800 77.900  1357.200 77.900  1357.200 110.300  1353.600 110.300  1353.600 94.900  1351.000 94.900  1351.000 110.300  1347.900 110.300  1347.900 104.100  1345.300 104.100  1345.300 110.300  1338.200 110.300  1338.200 77.900  1335.600 77.900  1335.600 110.300  1332.000 110.300  1332.000 94.900  1329.400 94.900  1329.400 110.300  1327.400 110.300  1327.400 77.900  1324.800 77.900  1324.800 110.300  1321.200 110.300  1321.200 94.900  1318.600 94.900  1318.600 110.300  1315.500 110.300  1315.500 104.100  1312.900 104.100  1312.900 110.300  1305.800 110.300  1305.800 77.900  1303.200 77.900  1303.200 110.300  1299.600 110.300  1299.600 94.900  1297.000 94.900  1297.000 110.300  1295.000 110.300  1295.000 77.900  1292.400 77.900  1292.400 110.300  1288.800 110.300  1288.800 94.900  1286.200 94.900  1286.200 110.300  1283.100 110.300  1283.100 104.100  1280.500 104.100  1280.500 110.300  1273.400 110.300  1273.400 77.900  1270.800 77.900  1270.800 110.300  1267.200 110.300  1267.200 94.900  1264.600 94.900  1264.600 110.300  1262.600 110.300  1262.600 77.900  1260.000 77.900  1260.000 110.300  1256.400 110.300  1256.400 94.900  1253.800 94.900  1253.800 110.300  1250.700 110.300  1250.700 104.100  1248.100 104.100  1248.100 110.300  1241.000 110.300  1241.000 77.900  1238.400 77.900  1238.400 110.300  1234.800 110.300  1234.800 94.900  1232.200 94.900  1232.200 110.300  1230.200 110.300  1230.200 77.900  1227.600 77.900  1227.600 110.300  1224.000 110.300  1224.000 94.900  1221.400 94.900  1221.400 110.300  1218.300 110.300  1218.300 104.100  1215.700 104.100  1215.700 110.300  1208.600 110.300  1208.600 77.900  1206.000 77.900  1206.000 110.300  1202.400 110.300  1202.400 94.900  1199.800 94.900  1199.800 110.300  1197.800 110.300  1197.800 77.900  1195.200 77.900  1195.200 110.300  1191.600 110.300  1191.600 94.900  1189.000 94.900  1189.000 110.300  1185.900 110.300  1185.900 104.100  1183.300 104.100  1183.300 110.300  1176.200 110.300  1176.200 77.900  1173.600 77.900  1173.600 110.300  1170.000 110.300  1170.000 94.900  1167.400 94.900  1167.400 110.300  1165.400 110.300  1165.400 77.900  1162.800 77.900  1162.800 110.300  1159.200 110.300  1159.200 94.900  1156.600 94.900  1156.600 110.300  1153.500 110.300  1153.500 104.100  1150.900 104.100  1150.900 110.300  1143.800 110.300  1143.800 77.900  1141.200 77.900  1141.200 110.300  1137.600 110.300  1137.600 94.900  1135.000 94.900  1135.000 110.300  1133.000 110.300  1133.000 77.900  1130.400 77.900  1130.400 110.300  1126.800 110.300  1126.800 94.900  1124.200 94.900  1124.200 110.300  1121.100 110.300  1121.100 104.100  1118.500 104.100  1118.500 110.300  1111.400 110.300  1111.400 77.900  1108.800 77.900  1108.800 110.300  1105.200 110.300  1105.200 94.900  1102.600 94.900  1102.600 110.300  1100.600 110.300  1100.600 77.900  1098.000 77.900  1098.000 110.300  1094.400 110.300  1094.400 94.900  1091.800 94.900  1091.800 110.300  1088.700 110.300  1088.700 104.100  1086.100 104.100  1086.100 110.300  1079.000 110.300  1079.000 77.900  1076.400 77.900  1076.400 110.300  1072.800 110.300  1072.800 94.900  1070.200 94.900  1070.200 110.300  1068.200 110.300  1068.200 77.900  1065.600 77.900  1065.600 110.300  1062.000 110.300  1062.000 94.900  1059.400 94.900  1059.400 110.300  1056.300 110.300  1056.300 104.100  1053.700 104.100  1053.700 110.300  1046.600 110.300  1046.600 77.900  1044.000 77.900  1044.000 110.300  1040.400 110.300  1040.400 94.900  1037.800 94.900  1037.800 110.300  1035.800 110.300  1035.800 77.900  1033.200 77.900  1033.200 110.300  1029.600 110.300  1029.600 94.900  1027.000 94.900  1027.000 110.300  1023.900 110.300  1023.900 104.100  1021.300 104.100  1021.300 110.300  1014.200 110.300  1014.200 77.900  1011.600 77.900  1011.600 110.300  1008.000 110.300  1008.000 94.900  1005.400 94.900  1005.400 110.300  1003.400 110.300  1003.400 77.900  1000.800 77.900  1000.800 110.300  997.200 110.300  997.200 94.900  994.600 94.900  994.600 110.300  991.500 110.300  991.500 104.100  988.900 104.100  988.900 110.300  981.800 110.300  981.800 77.900  979.200 77.900  979.200 110.300  975.600 110.300  975.600 94.900  973.000 94.900  973.000 110.300  971.000 110.300  971.000 77.900  968.400 77.900  968.400 110.300  964.800 110.300  964.800 94.900  962.200 94.900  962.200 110.300  959.100 110.300  959.100 104.100  956.500 104.100  956.500 110.300  949.400 110.300  949.400 77.900  946.800 77.900  946.800 110.300  943.200 110.300  943.200 94.900  940.600 94.900  940.600 110.300  938.600 110.300  938.600 77.900  936.000 77.900  936.000 110.300  932.400 110.300  932.400 94.900  929.800 94.900  929.800 110.300  926.700 110.300  926.700 104.100  924.100 104.100  924.100 110.300  917.000 110.300  917.000 77.900  914.400 77.900  914.400 110.300  910.800 110.300  910.800 94.900  908.200 94.900  908.200 110.300  906.200 110.300  906.200 77.900  903.600 77.900  903.600 110.300  900.000 110.300  900.000 94.900  897.400 94.900  897.400 110.300  894.300 110.300  894.300 104.100  891.700 104.100  891.700 110.300  884.600 110.300  884.600 77.900  882.000 77.900  882.000 110.300  878.400 110.300  878.400 94.900  875.800 94.900  875.800 110.300  873.800 110.300  873.800 77.900  871.200 77.900  871.200 110.300  867.600 110.300  867.600 94.900  865.000 94.900  865.000 110.300  861.900 110.300  861.900 104.100  859.300 104.100  859.300 110.300  852.200 110.300  852.200 77.900  849.600 77.900  849.600 110.300  846.000 110.300  846.000 94.900  843.400 94.900  843.400 110.300  841.400 110.300  841.400 77.900  838.800 77.900  838.800 110.300  835.200 110.300  835.200 94.900  832.600 94.900  832.600 110.300  829.500 110.300  829.500 104.100  826.900 104.100  826.900 110.300  819.800 110.300  819.800 77.900  817.200 77.900  817.200 110.300  813.600 110.300  813.600 94.900  811.000 94.900  811.000 110.300  809.000 110.300  809.000 77.900  806.400 77.900  806.400 110.300  802.800 110.300  802.800 94.900  800.200 94.900  800.200 110.300  797.100 110.300  797.100 104.100  794.500 104.100  794.500 110.300  787.400 110.300  787.400 77.900  784.800 77.900  784.800 110.300  781.200 110.300  781.200 94.900  778.600 94.900  778.600 110.300  776.600 110.300  776.600 77.900  774.000 77.900  774.000 110.300  770.400 110.300  770.400 94.900  767.800 94.900  767.800 110.300  764.700 110.300  764.700 104.100  762.100 104.100  762.100 110.300  755.000 110.300  755.000 77.900  752.400 77.900  752.400 110.300  748.800 110.300  748.800 94.900  746.200 94.900  746.200 110.300  744.200 110.300  744.200 77.900  741.600 77.900  741.600 110.300  738.000 110.300  738.000 94.900  735.400 94.900  735.400 110.300  732.300 110.300  732.300 104.100  729.700 104.100  729.700 110.300  722.600 110.300  722.600 77.900  720.000 77.900  720.000 110.300  716.400 110.300  716.400 94.900  713.800 94.900  713.800 110.300  711.800 110.300  711.800 77.900  709.200 77.900  709.200 110.300  705.600 110.300  705.600 94.900  703.000 94.900  703.000 110.300  699.900 110.300  699.900 104.100  697.300 104.100  697.300 110.300  690.200 110.300  690.200 77.900  687.600 77.900  687.600 110.300  684.000 110.300  684.000 94.900  681.400 94.900  681.400 110.300  679.400 110.300  679.400 77.900  676.800 77.900  676.800 110.300  673.200 110.300  673.200 94.900  670.600 94.900  670.600 110.300  667.500 110.300  667.500 104.100  664.900 104.100  664.900 110.300  657.800 110.300  657.800 77.900  655.200 77.900  655.200 110.300  651.600 110.300  651.600 94.900  649.000 94.900  649.000 110.300  647.000 110.300  647.000 77.900  644.400 77.900  644.400 110.300  640.800 110.300  640.800 94.900  638.200 94.900  638.200 110.300  635.100 110.300  635.100 104.100  632.500 104.100  632.500 110.300  625.400 110.300  625.400 77.900  622.800 77.900  622.800 110.300  619.200 110.300  619.200 94.900  616.600 94.900  616.600 110.300  614.600 110.300  614.600 77.900  612.000 77.900  612.000 110.300  608.400 110.300  608.400 94.900  605.800 94.900  605.800 110.300  602.700 110.300  602.700 104.100  600.100 104.100  600.100 110.300  593.000 110.300  593.000 77.900  590.400 77.900  590.400 110.300  586.800 110.300  586.800 94.900  584.200 94.900  584.200 110.300  582.200 110.300  582.200 77.900  579.600 77.900  579.600 110.300  576.000 110.300  576.000 94.900  573.400 94.900  573.400 110.300  570.300 110.300  570.300 104.100  567.700 104.100  567.700 110.300  560.600 110.300  560.600 77.900  558.000 77.900  558.000 110.300  554.400 110.300  554.400 94.900  551.800 94.900  551.800 110.300  549.800 110.300  549.800 77.900  547.200 77.900  547.200 110.300  543.600 110.300  543.600 94.900  541.000 94.900  541.000 110.300  537.900 110.300  537.900 104.100  535.300 104.100  535.300 110.300  528.200 110.300  528.200 77.900  525.600 77.900  525.600 110.300  522.000 110.300  522.000 94.900  519.400 94.900  519.400 110.300  517.400 110.300  517.400 77.900  514.800 77.900  514.800 110.300  511.200 110.300  511.200 94.900  508.600 94.900  508.600 110.300  505.500 110.300  505.500 104.100  502.900 104.100  502.900 110.300  495.800 110.300  495.800 77.900  493.200 77.900  493.200 110.300  489.600 110.300  489.600 94.900  487.000 94.900  487.000 110.300  485.000 110.300  485.000 77.900  482.400 77.900  482.400 110.300  478.800 110.300  478.800 94.900  476.200 94.900  476.200 110.300  473.100 110.300  473.100 104.100  470.500 104.100  470.500 110.300  463.400 110.300  463.400 77.900  460.800 77.900  460.800 110.300  457.200 110.300  457.200 94.900  454.600 94.900  454.600 110.300  452.600 110.300  452.600 77.900  450.000 77.900  450.000 110.300  446.400 110.300  446.400 94.900  443.800 94.900  443.800 110.300  440.700 110.300  440.700 104.100  438.100 104.100  438.100 110.300  431.000 110.300  431.000 77.900  428.400 77.900  428.400 110.300  424.800 110.300  424.800 94.900  422.200 94.900  422.200 110.300  420.200 110.300  420.200 77.900  417.600 77.900  417.600 110.300  414.000 110.300  414.000 94.900  411.400 94.900  411.400 110.300  408.300 110.300  408.300 104.100  405.700 104.100  405.700 110.300  398.600 110.300  398.600 77.900  396.000 77.900  396.000 110.300  392.400 110.300  392.400 94.900  389.800 94.900  389.800 110.300  387.800 110.300  387.800 77.900  385.200 77.900  385.200 110.300  381.600 110.300  381.600 94.900  379.000 94.900  379.000 110.300  375.900 110.300  375.900 104.100  373.300 104.100  373.300 110.300  366.200 110.300  366.200 77.900  363.600 77.900  363.600 110.300  360.000 110.300  360.000 94.900  357.400 94.900  357.400 110.300  355.400 110.300  355.400 77.900  352.800 77.900  352.800 110.300  349.200 110.300  349.200 94.900  346.600 94.900  346.600 110.300  343.500 110.300  343.500 104.100  340.900 104.100  340.900 110.300  333.800 110.300  333.800 77.900  331.200 77.900  331.200 110.300  327.600 110.300  327.600 94.900  325.000 94.900  325.000 110.300  323.000 110.300  323.000 77.900  320.400 77.900  320.400 110.300  316.800 110.300  316.800 94.900  314.200 94.900  314.200 110.300  311.100 110.300  311.100 104.100  308.500 104.100  308.500 110.300  301.400 110.300  301.400 77.900  298.800 77.900  298.800 110.300  295.200 110.300  295.200 94.900  292.600 94.900  292.600 110.300  290.600 110.300  290.600 77.900  288.000 77.900  288.000 110.300  284.400 110.300  284.400 94.900  281.800 94.900  281.800 110.300  278.700 110.300  278.700 104.100  276.100 104.100  276.100 110.300  269.000 110.300  269.000 77.900  266.400 77.900  266.400 110.300  262.800 110.300  262.800 94.900  260.200 94.900  260.200 110.300  258.200 110.300  258.200 77.900  255.600 77.900  255.600 110.300  252.000 110.300  252.000 94.900  249.400 94.900  249.400 110.300  246.300 110.300  246.300 104.100  243.700 104.100  243.700 110.300  236.600 110.300  236.600 77.900  234.000 77.900  234.000 110.300  230.400 110.300  230.400 94.900  227.800 94.900  227.800 110.300  225.800 110.300  225.800 77.900  223.200 77.900  223.200 110.300  219.600 110.300  219.600 94.900  217.000 94.900  217.000 110.300  213.900 110.300  213.900 104.100  211.300 104.100  211.300 110.300  204.200 110.300  204.200 77.900  201.600 77.900  201.600 110.300  198.000 110.300  198.000 94.900  195.400 94.900  195.400 110.300  193.400 110.300  193.400 77.900  190.800 77.900  190.800 110.300  187.200 110.300  187.200 94.900  184.600 94.900  184.600 110.300  181.500 110.300  181.500 104.100  178.900 104.100  178.900 110.300  171.800 110.300  171.800 77.900  169.200 77.900  169.200 110.300  165.600 110.300  165.600 94.900  163.000 94.900  163.000 110.300  161.000 110.300  161.000 77.900  158.400 77.900  158.400 110.300  154.800 110.300  154.800 94.900  152.200 94.900  152.200 110.300  149.100 110.300  149.100 104.100  146.500 104.100  146.500 110.300  139.400 110.300  139.400 77.900  136.800 77.900  136.800 110.300  133.200 110.300  133.200 94.900  130.600 94.900  130.600 110.300  128.600 110.300  128.600 77.900  126.000 77.900  126.000 110.300  122.400 110.300  122.400 94.900  119.800 94.900  119.800 110.300  116.700 110.300  116.700 104.100  114.100 104.100  114.100 110.300  107.000 110.300  107.000 77.900  104.400 77.900  104.400 110.300  100.800 110.300  100.800 94.900  98.200 94.900  98.200 110.300  96.200 110.300  96.200 77.900  93.600 77.900  93.600 110.300  90.000 110.300  90.000 94.900  87.400 94.900  87.400 110.300  84.300 110.300  84.300 104.100  81.700 104.100  81.700 110.300  74.600 110.300  74.600 77.900  72.000 77.900  72.000 110.300  68.400 110.300  68.400 94.900  65.800 94.900  65.800 110.300  63.800 110.300  63.800 77.900  61.200 77.900  61.200 110.300  57.600 110.300  57.600 94.900  55.000 94.900  55.000 110.300  51.900 110.300  51.900 104.100  49.300 104.100  49.300 110.300  42.200 110.300  42.200 77.900  39.600 77.900  39.600 110.300  36.000 110.300  36.000 94.900  33.400 94.900  33.400 110.300  31.400 110.300  31.400 77.900  28.800 77.900  28.800 110.300  25.200 110.300  25.200 94.900  22.600 94.900  22.600 110.300  20.600 110.300  20.600 77.900 ;
            POLYGON 1210.600 -102.700  1210.600 -56.300  1215.700 -56.300  1215.700 -69.700  1212.400 -69.700  1212.400 -77.800  1214.000 -77.800  1214.000 -81.200  1212.400 -81.200  1212.400 -99.300  1214.300 -99.300  1214.300 -102.700 ;
            POLYGON 1213.100 61.100  1213.100 72.700  1210.600 72.700  1210.600 107.500  1214.300 107.500  1214.300 104.100  1212.400 104.100  1212.400 86.000  1214.000 86.000  1214.000 82.600  1212.400 82.600  1212.400 74.500  1215.700 74.500  1215.700 61.100 ;
            POLYGON 1253.800 28.000  1253.800 36.500  1256.400 36.500  1256.400 31.400  1257.200 31.400  1257.200 28.000 ;
            POLYGON 1286.200 28.000  1286.200 36.500  1288.800 36.500  1288.800 31.400  1289.600 31.400  1289.600 28.000 ;
            POLYGON 1318.600 28.000  1318.600 36.500  1321.200 36.500  1321.200 31.400  1322.000 31.400  1322.000 28.000 ;
            POLYGON 1351.000 28.000  1351.000 36.500  1353.600 36.500  1353.600 31.400  1354.400 31.400  1354.400 28.000 ;
            POLYGON 1383.400 28.000  1383.400 36.500  1386.000 36.500  1386.000 31.400  1386.800 31.400  1386.800 28.000 ;
            POLYGON 1415.800 28.000  1415.800 36.500  1418.400 36.500  1418.400 31.400  1419.200 31.400  1419.200 28.000 ;
            POLYGON 1448.200 28.000  1448.200 36.500  1450.800 36.500  1450.800 31.400  1451.600 31.400  1451.600 28.000 ;
            POLYGON 1480.600 28.000  1480.600 36.500  1483.200 36.500  1483.200 31.400  1484.000 31.400  1484.000 28.000 ;
            POLYGON 1513.000 28.000  1513.000 36.500  1515.600 36.500  1515.600 31.400  1516.400 31.400  1516.400 28.000 ;
            POLYGON 1518.400 28.000  1518.400 31.400  1519.500 31.400  1519.500 36.500  1522.100 36.500  1522.100 33.900  1521.800 33.900  1521.800 28.000 ;
            POLYGON 1599.400 28.000  1599.400 36.500  1602.000 36.500  1602.000 31.400  1602.800 31.400  1602.800 28.000 ;
            POLYGON 1226.500 6.500  1226.500 9.900  1228.400 9.900  1228.400 28.000  1226.800 28.000  1226.800 31.400  1228.400 31.400  1228.400 39.500  1225.100 39.500  1225.100 52.900  1227.700 52.900  1227.700 41.300  1230.200 41.300  1230.200 6.500 ;
            POLYGON 1258.900 6.500  1258.900 9.900  1260.800 9.900  1260.800 28.000  1259.200 28.000  1259.200 31.400  1260.800 31.400  1260.800 39.500  1257.500 39.500  1257.500 52.900  1260.100 52.900  1260.100 41.300  1262.600 41.300  1262.600 6.500 ;
            POLYGON 1291.300 6.500  1291.300 9.900  1293.200 9.900  1293.200 28.000  1291.600 28.000  1291.600 31.400  1293.200 31.400  1293.200 39.500  1289.900 39.500  1289.900 52.900  1292.500 52.900  1292.500 41.300  1295.000 41.300  1295.000 6.500 ;
            POLYGON 1323.700 6.500  1323.700 9.900  1325.600 9.900  1325.600 28.000  1324.000 28.000  1324.000 31.400  1325.600 31.400  1325.600 39.500  1322.300 39.500  1322.300 52.900  1324.900 52.900  1324.900 41.300  1327.400 41.300  1327.400 6.500 ;
            POLYGON 1356.100 6.500  1356.100 9.900  1358.000 9.900  1358.000 28.000  1356.400 28.000  1356.400 31.400  1358.000 31.400  1358.000 39.500  1354.700 39.500  1354.700 52.900  1357.300 52.900  1357.300 41.300  1359.800 41.300  1359.800 6.500 ;
            POLYGON 1388.500 6.500  1388.500 9.900  1390.400 9.900  1390.400 28.000  1388.800 28.000  1388.800 31.400  1390.400 31.400  1390.400 39.500  1387.100 39.500  1387.100 52.900  1389.700 52.900  1389.700 41.300  1392.200 41.300  1392.200 6.500 ;
            POLYGON 1420.900 6.500  1420.900 9.900  1422.800 9.900  1422.800 28.000  1421.200 28.000  1421.200 31.400  1422.800 31.400  1422.800 39.500  1419.500 39.500  1419.500 52.900  1422.100 52.900  1422.100 41.300  1424.600 41.300  1424.600 6.500 ;
            POLYGON 1453.300 6.500  1453.300 9.900  1455.200 9.900  1455.200 28.000  1453.600 28.000  1453.600 31.400  1455.200 31.400  1455.200 39.500  1451.900 39.500  1451.900 52.900  1454.500 52.900  1454.500 41.300  1457.000 41.300  1457.000 6.500 ;
            POLYGON 1485.700 6.500  1485.700 9.900  1487.600 9.900  1487.600 28.000  1486.000 28.000  1486.000 31.400  1487.600 31.400  1487.600 39.500  1484.300 39.500  1484.300 52.900  1486.900 52.900  1486.900 41.300  1489.400 41.300  1489.400 6.500 ;
            POLYGON 1523.500 16.200  1523.500 19.600  1525.400 19.600  1525.400 38.700  1524.600 38.700  1524.600 39.500  1516.700 39.500  1516.700 52.900  1519.300 52.900  1519.300 41.300  1527.200 41.300  1527.200 16.200 ;
            POLYGON 1528.900 7.700  1528.900 11.100  1530.800 11.100  1530.800 28.000  1529.200 28.000  1529.200 31.400  1530.800 31.400  1530.800 42.700  1524.700 42.700  1524.700 52.900  1527.300 52.900  1527.300 44.600  1532.600 44.600  1532.600 7.700 ;
            POLYGON 1604.500 6.500  1604.500 9.900  1606.400 9.900  1606.400 28.000  1604.800 28.000  1604.800 31.400  1606.400 31.400  1606.400 39.500  1603.100 39.500  1603.100 52.900  1605.700 52.900  1605.700 41.300  1608.200 41.300  1608.200 31.400  1616.600 31.400  1616.600 28.000  1608.200 28.000  1608.200 6.500 ;
            POLYGON 1216.800 77.500  1216.800 82.600  1216.000 82.600  1216.000 86.000  1219.400 86.000  1219.400 77.500 ;
            POLYGON 1249.200 77.500  1249.200 82.600  1248.400 82.600  1248.400 86.000  1251.800 86.000  1251.800 77.500 ;
            POLYGON 1281.600 77.500  1281.600 82.600  1280.800 82.600  1280.800 86.000  1284.200 86.000  1284.200 77.500 ;
            POLYGON 1314.000 77.500  1314.000 82.600  1313.200 82.600  1313.200 86.000  1316.600 86.000  1316.600 77.500 ;
            POLYGON 1346.400 77.500  1346.400 82.600  1345.600 82.600  1345.600 86.000  1349.000 86.000  1349.000 77.500 ;
            POLYGON 1378.800 77.500  1378.800 82.600  1378.000 82.600  1378.000 86.000  1381.400 86.000  1381.400 77.500 ;
            POLYGON 1411.200 77.500  1411.200 82.600  1410.400 82.600  1410.400 86.000  1413.800 86.000  1413.800 77.500 ;
            POLYGON 1443.600 77.500  1443.600 82.600  1442.800 82.600  1442.800 86.000  1446.200 86.000  1446.200 77.500 ;
            POLYGON 1476.000 77.500  1476.000 82.600  1475.200 82.600  1475.200 86.000  1478.600 86.000  1478.600 77.500 ;
            POLYGON 1508.400 77.500  1508.400 82.600  1507.600 82.600  1507.600 86.000  1511.000 86.000  1511.000 77.500 ;
            POLYGON 1540.800 77.500  1540.800 82.600  1540.000 82.600  1540.000 86.000  1543.400 86.000  1543.400 77.500 ;
            POLYGON 1573.200 77.500  1573.200 82.600  1572.400 82.600  1572.400 86.000  1575.800 86.000  1575.800 77.500 ;
            POLYGON 1605.600 77.500  1605.600 82.600  1604.800 82.600  1604.800 86.000  1608.200 86.000  1608.200 77.500 ;
            POLYGON 1221.400 28.000  1221.400 36.500  1224.000 36.500  1224.000 31.400  1224.800 31.400  1224.800 28.000 ;
            POLYGON 1245.500 61.100  1245.500 72.700  1243.000 72.700  1243.000 107.500  1246.700 107.500  1246.700 104.100  1244.800 104.100  1244.800 86.000  1246.400 86.000  1246.400 82.600  1244.800 82.600  1244.800 74.500  1248.100 74.500  1248.100 61.100 ;
            POLYGON 1277.900 61.100  1277.900 72.700  1275.400 72.700  1275.400 107.500  1279.100 107.500  1279.100 104.100  1277.200 104.100  1277.200 86.000  1278.800 86.000  1278.800 82.600  1277.200 82.600  1277.200 74.500  1280.500 74.500  1280.500 61.100 ;
            POLYGON 1310.300 61.100  1310.300 72.700  1307.800 72.700  1307.800 107.500  1311.500 107.500  1311.500 104.100  1309.600 104.100  1309.600 86.000  1311.200 86.000  1311.200 82.600  1309.600 82.600  1309.600 74.500  1312.900 74.500  1312.900 61.100 ;
            POLYGON 1342.700 61.100  1342.700 72.700  1340.200 72.700  1340.200 107.500  1343.900 107.500  1343.900 104.100  1342.000 104.100  1342.000 86.000  1343.600 86.000  1343.600 82.600  1342.000 82.600  1342.000 74.500  1345.300 74.500  1345.300 61.100 ;
            POLYGON 1375.100 61.100  1375.100 72.700  1372.600 72.700  1372.600 107.500  1376.300 107.500  1376.300 104.100  1374.400 104.100  1374.400 86.000  1376.000 86.000  1376.000 82.600  1374.400 82.600  1374.400 74.500  1377.700 74.500  1377.700 61.100 ;
            POLYGON 1407.500 61.100  1407.500 72.700  1405.000 72.700  1405.000 107.500  1408.700 107.500  1408.700 104.100  1406.800 104.100  1406.800 86.000  1408.400 86.000  1408.400 82.600  1406.800 82.600  1406.800 74.500  1410.100 74.500  1410.100 61.100 ;
            POLYGON 1439.900 61.100  1439.900 72.700  1437.400 72.700  1437.400 107.500  1441.100 107.500  1441.100 104.100  1439.200 104.100  1439.200 86.000  1440.800 86.000  1440.800 82.600  1439.200 82.600  1439.200 74.500  1442.500 74.500  1442.500 61.100 ;
            POLYGON 1472.300 61.100  1472.300 72.700  1469.800 72.700  1469.800 107.500  1473.500 107.500  1473.500 104.100  1471.600 104.100  1471.600 86.000  1473.200 86.000  1473.200 82.600  1471.600 82.600  1471.600 74.500  1474.900 74.500  1474.900 61.100 ;
            POLYGON 1504.700 61.100  1504.700 72.700  1502.200 72.700  1502.200 107.500  1505.900 107.500  1505.900 104.100  1504.000 104.100  1504.000 86.000  1505.600 86.000  1505.600 82.600  1504.000 82.600  1504.000 74.500  1507.300 74.500  1507.300 61.100 ;
            POLYGON 1537.100 61.100  1537.100 72.700  1534.600 72.700  1534.600 107.500  1538.300 107.500  1538.300 104.100  1536.400 104.100  1536.400 86.000  1538.000 86.000  1538.000 82.600  1536.400 82.600  1536.400 74.500  1539.700 74.500  1539.700 61.100 ;
            POLYGON 1569.500 61.100  1569.500 72.700  1567.000 72.700  1567.000 107.500  1570.700 107.500  1570.700 104.100  1568.800 104.100  1568.800 86.000  1570.400 86.000  1570.400 82.600  1568.800 82.600  1568.800 74.500  1572.100 74.500  1572.100 61.100 ;
            POLYGON 1601.900 61.100  1601.900 72.700  1599.400 72.700  1599.400 107.500  1603.100 107.500  1603.100 104.100  1601.200 104.100  1601.200 86.000  1602.800 86.000  1602.800 82.600  1601.200 82.600  1601.200 74.500  1604.500 74.500  1604.500 61.100 ;
            POLYGON 892.800 77.500  892.800 82.600  892.000 82.600  892.000 86.000  895.400 86.000  895.400 77.500 ;
            POLYGON 925.200 77.500  925.200 82.600  924.400 82.600  924.400 86.000  927.800 86.000  927.800 77.500 ;
            POLYGON 957.600 77.500  957.600 82.600  956.800 82.600  956.800 86.000  960.200 86.000  960.200 77.500 ;
            POLYGON 990.000 77.500  990.000 82.600  989.200 82.600  989.200 86.000  992.600 86.000  992.600 77.500 ;
            POLYGON 1022.400 77.500  1022.400 82.600  1021.600 82.600  1021.600 86.000  1025.000 86.000  1025.000 77.500 ;
            POLYGON 1054.800 77.500  1054.800 82.600  1054.000 82.600  1054.000 86.000  1057.400 86.000  1057.400 77.500 ;
            POLYGON 1087.200 77.500  1087.200 82.600  1086.400 82.600  1086.400 86.000  1089.800 86.000  1089.800 77.500 ;
            POLYGON 1119.600 77.500  1119.600 82.600  1118.800 82.600  1118.800 86.000  1122.200 86.000  1122.200 77.500 ;
            POLYGON 1152.000 77.500  1152.000 82.600  1151.200 82.600  1151.200 86.000  1154.600 86.000  1154.600 77.500 ;
            POLYGON 1184.400 77.500  1184.400 82.600  1183.600 82.600  1183.600 86.000  1187.000 86.000  1187.000 77.500 ;
            POLYGON 837.700 6.500  837.700 9.900  839.600 9.900  839.600 28.000  838.000 28.000  838.000 31.400  839.600 31.400  839.600 39.500  836.300 39.500  836.300 52.900  838.900 52.900  838.900 41.300  841.400 41.300  841.400 6.500 ;
            POLYGON 870.100 6.500  870.100 9.900  872.000 9.900  872.000 28.000  870.400 28.000  870.400 31.400  872.000 31.400  872.000 39.500  868.700 39.500  868.700 52.900  871.300 52.900  871.300 41.300  873.800 41.300  873.800 6.500 ;
            POLYGON 902.500 6.500  902.500 9.900  904.400 9.900  904.400 28.000  902.800 28.000  902.800 31.400  904.400 31.400  904.400 39.500  901.100 39.500  901.100 52.900  903.700 52.900  903.700 41.300  906.200 41.300  906.200 6.500 ;
            POLYGON 934.900 6.500  934.900 9.900  936.800 9.900  936.800 28.000  935.200 28.000  935.200 31.400  936.800 31.400  936.800 39.500  933.500 39.500  933.500 52.900  936.100 52.900  936.100 41.300  938.600 41.300  938.600 6.500 ;
            POLYGON 967.300 6.500  967.300 9.900  969.200 9.900  969.200 28.000  967.600 28.000  967.600 31.400  969.200 31.400  969.200 39.500  965.900 39.500  965.900 52.900  968.500 52.900  968.500 41.300  971.000 41.300  971.000 6.500 ;
            POLYGON 999.700 6.500  999.700 9.900  1001.600 9.900  1001.600 28.000  1000.000 28.000  1000.000 31.400  1001.600 31.400  1001.600 39.500  998.300 39.500  998.300 52.900  1000.900 52.900  1000.900 41.300  1003.400 41.300  1003.400 6.500 ;
            POLYGON 1032.100 6.500  1032.100 9.900  1034.000 9.900  1034.000 28.000  1032.400 28.000  1032.400 31.400  1034.000 31.400  1034.000 39.500  1030.700 39.500  1030.700 52.900  1033.300 52.900  1033.300 41.300  1035.800 41.300  1035.800 6.500 ;
            POLYGON 1064.500 6.500  1064.500 9.900  1066.400 9.900  1066.400 28.000  1064.800 28.000  1064.800 31.400  1066.400 31.400  1066.400 39.500  1063.100 39.500  1063.100 52.900  1065.700 52.900  1065.700 41.300  1068.200 41.300  1068.200 6.500 ;
            POLYGON 1096.900 6.500  1096.900 9.900  1098.800 9.900  1098.800 28.000  1097.200 28.000  1097.200 31.400  1098.800 31.400  1098.800 39.500  1095.500 39.500  1095.500 52.900  1098.100 52.900  1098.100 41.300  1100.600 41.300  1100.600 6.500 ;
            POLYGON 1129.300 6.500  1129.300 9.900  1131.200 9.900  1131.200 28.000  1129.600 28.000  1129.600 31.400  1131.200 31.400  1131.200 39.500  1127.900 39.500  1127.900 52.900  1130.500 52.900  1130.500 41.300  1133.000 41.300  1133.000 6.500 ;
            POLYGON 1161.700 6.500  1161.700 9.900  1163.600 9.900  1163.600 28.000  1162.000 28.000  1162.000 31.400  1163.600 31.400  1163.600 39.500  1160.300 39.500  1160.300 52.900  1162.900 52.900  1162.900 41.300  1165.400 41.300  1165.400 6.500 ;
            POLYGON 1194.100 6.500  1194.100 9.900  1196.000 9.900  1196.000 28.000  1194.400 28.000  1194.400 31.400  1196.000 31.400  1196.000 39.500  1192.700 39.500  1192.700 52.900  1195.300 52.900  1195.300 41.300  1197.800 41.300  1197.800 6.500 ;
            POLYGON 832.600 28.000  832.600 36.500  835.200 36.500  835.200 31.400  836.000 31.400  836.000 28.000 ;
            POLYGON 824.300 61.100  824.300 72.700  821.800 72.700  821.800 107.500  825.500 107.500  825.500 104.100  823.600 104.100  823.600 86.000  825.200 86.000  825.200 82.600  823.600 82.600  823.600 74.500  826.900 74.500  826.900 61.100 ;
            POLYGON 856.700 61.100  856.700 72.700  854.200 72.700  854.200 107.500  857.900 107.500  857.900 104.100  856.000 104.100  856.000 86.000  857.600 86.000  857.600 82.600  856.000 82.600  856.000 74.500  859.300 74.500  859.300 61.100 ;
            POLYGON 889.100 61.100  889.100 72.700  886.600 72.700  886.600 107.500  890.300 107.500  890.300 104.100  888.400 104.100  888.400 86.000  890.000 86.000  890.000 82.600  888.400 82.600  888.400 74.500  891.700 74.500  891.700 61.100 ;
            POLYGON 921.500 61.100  921.500 72.700  919.000 72.700  919.000 107.500  922.700 107.500  922.700 104.100  920.800 104.100  920.800 86.000  922.400 86.000  922.400 82.600  920.800 82.600  920.800 74.500  924.100 74.500  924.100 61.100 ;
            POLYGON 953.900 61.100  953.900 72.700  951.400 72.700  951.400 107.500  955.100 107.500  955.100 104.100  953.200 104.100  953.200 86.000  954.800 86.000  954.800 82.600  953.200 82.600  953.200 74.500  956.500 74.500  956.500 61.100 ;
            POLYGON 986.300 61.100  986.300 72.700  983.800 72.700  983.800 107.500  987.500 107.500  987.500 104.100  985.600 104.100  985.600 86.000  987.200 86.000  987.200 82.600  985.600 82.600  985.600 74.500  988.900 74.500  988.900 61.100 ;
            POLYGON 1018.700 61.100  1018.700 72.700  1016.200 72.700  1016.200 107.500  1019.900 107.500  1019.900 104.100  1018.000 104.100  1018.000 86.000  1019.600 86.000  1019.600 82.600  1018.000 82.600  1018.000 74.500  1021.300 74.500  1021.300 61.100 ;
            POLYGON 1051.100 61.100  1051.100 72.700  1048.600 72.700  1048.600 107.500  1052.300 107.500  1052.300 104.100  1050.400 104.100  1050.400 86.000  1052.000 86.000  1052.000 82.600  1050.400 82.600  1050.400 74.500  1053.700 74.500  1053.700 61.100 ;
            POLYGON 1083.500 61.100  1083.500 72.700  1081.000 72.700  1081.000 107.500  1084.700 107.500  1084.700 104.100  1082.800 104.100  1082.800 86.000  1084.400 86.000  1084.400 82.600  1082.800 82.600  1082.800 74.500  1086.100 74.500  1086.100 61.100 ;
            POLYGON 1115.900 61.100  1115.900 72.700  1113.400 72.700  1113.400 107.500  1117.100 107.500  1117.100 104.100  1115.200 104.100  1115.200 86.000  1116.800 86.000  1116.800 82.600  1115.200 82.600  1115.200 74.500  1118.500 74.500  1118.500 61.100 ;
            POLYGON 1148.300 61.100  1148.300 72.700  1145.800 72.700  1145.800 107.500  1149.500 107.500  1149.500 104.100  1147.600 104.100  1147.600 86.000  1149.200 86.000  1149.200 82.600  1147.600 82.600  1147.600 74.500  1150.900 74.500  1150.900 61.100 ;
            POLYGON 1180.700 61.100  1180.700 72.700  1178.200 72.700  1178.200 107.500  1181.900 107.500  1181.900 104.100  1180.000 104.100  1180.000 86.000  1181.600 86.000  1181.600 82.600  1180.000 82.600  1180.000 74.500  1183.300 74.500  1183.300 61.100 ;
            POLYGON 865.000 28.000  865.000 36.500  867.600 36.500  867.600 31.400  868.400 31.400  868.400 28.000 ;
            POLYGON 897.400 28.000  897.400 36.500  900.000 36.500  900.000 31.400  900.800 31.400  900.800 28.000 ;
            POLYGON 929.800 28.000  929.800 36.500  932.400 36.500  932.400 31.400  933.200 31.400  933.200 28.000 ;
            POLYGON 962.200 28.000  962.200 36.500  964.800 36.500  964.800 31.400  965.600 31.400  965.600 28.000 ;
            POLYGON 994.600 28.000  994.600 36.500  997.200 36.500  997.200 31.400  998.000 31.400  998.000 28.000 ;
            POLYGON 1027.000 28.000  1027.000 36.500  1029.600 36.500  1029.600 31.400  1030.400 31.400  1030.400 28.000 ;
            POLYGON 1059.400 28.000  1059.400 36.500  1062.000 36.500  1062.000 31.400  1062.800 31.400  1062.800 28.000 ;
            POLYGON 1091.800 28.000  1091.800 36.500  1094.400 36.500  1094.400 31.400  1095.200 31.400  1095.200 28.000 ;
            POLYGON 1124.200 28.000  1124.200 36.500  1126.800 36.500  1126.800 31.400  1127.600 31.400  1127.600 28.000 ;
            POLYGON 1156.600 28.000  1156.600 36.500  1159.200 36.500  1159.200 31.400  1160.000 31.400  1160.000 28.000 ;
            POLYGON 1189.000 28.000  1189.000 36.500  1191.600 36.500  1191.600 31.400  1192.400 31.400  1192.400 28.000 ;
            POLYGON 828.000 77.500  828.000 82.600  827.200 82.600  827.200 86.000  830.600 86.000  830.600 77.500 ;
            POLYGON 860.400 77.500  860.400 82.600  859.600 82.600  859.600 86.000  863.000 86.000  863.000 77.500 ;
            POLYGON 1183.600 -81.200  1183.600 -77.800  1184.400 -77.800  1184.400 -72.700  1187.000 -72.700  1187.000 -81.200 ;
            POLYGON 821.800 -102.700  821.800 -56.300  826.900 -56.300  826.900 -69.700  823.600 -69.700  823.600 -77.800  825.200 -77.800  825.200 -81.200  823.600 -81.200  823.600 -99.300  825.500 -99.300  825.500 -102.700 ;
            POLYGON 854.200 -102.700  854.200 -56.300  859.300 -56.300  859.300 -69.700  856.000 -69.700  856.000 -77.800  857.600 -77.800  857.600 -81.200  856.000 -81.200  856.000 -99.300  857.900 -99.300  857.900 -102.700 ;
            POLYGON 886.600 -102.700  886.600 -56.300  891.700 -56.300  891.700 -69.700  888.400 -69.700  888.400 -77.800  890.000 -77.800  890.000 -81.200  888.400 -81.200  888.400 -99.300  890.300 -99.300  890.300 -102.700 ;
            POLYGON 919.000 -102.700  919.000 -56.300  924.100 -56.300  924.100 -69.700  920.800 -69.700  920.800 -77.800  922.400 -77.800  922.400 -81.200  920.800 -81.200  920.800 -99.300  922.700 -99.300  922.700 -102.700 ;
            POLYGON 951.400 -102.700  951.400 -56.300  956.500 -56.300  956.500 -69.700  953.200 -69.700  953.200 -77.800  954.800 -77.800  954.800 -81.200  953.200 -81.200  953.200 -99.300  955.100 -99.300  955.100 -102.700 ;
            POLYGON 983.800 -102.700  983.800 -56.300  988.900 -56.300  988.900 -69.700  985.600 -69.700  985.600 -77.800  987.200 -77.800  987.200 -81.200  985.600 -81.200  985.600 -99.300  987.500 -99.300  987.500 -102.700 ;
            POLYGON 1016.200 -102.700  1016.200 -56.300  1021.300 -56.300  1021.300 -69.700  1018.000 -69.700  1018.000 -77.800  1019.600 -77.800  1019.600 -81.200  1018.000 -81.200  1018.000 -99.300  1019.900 -99.300  1019.900 -102.700 ;
            POLYGON 1048.600 -102.700  1048.600 -56.300  1053.700 -56.300  1053.700 -69.700  1050.400 -69.700  1050.400 -77.800  1052.000 -77.800  1052.000 -81.200  1050.400 -81.200  1050.400 -99.300  1052.300 -99.300  1052.300 -102.700 ;
            POLYGON 1081.000 -102.700  1081.000 -56.300  1086.100 -56.300  1086.100 -69.700  1082.800 -69.700  1082.800 -77.800  1084.400 -77.800  1084.400 -81.200  1082.800 -81.200  1082.800 -99.300  1084.700 -99.300  1084.700 -102.700 ;
            POLYGON 1113.400 -102.700  1113.400 -56.300  1118.500 -56.300  1118.500 -69.700  1115.200 -69.700  1115.200 -77.800  1116.800 -77.800  1116.800 -81.200  1115.200 -81.200  1115.200 -99.300  1117.100 -99.300  1117.100 -102.700 ;
            POLYGON 1145.800 -102.700  1145.800 -56.300  1150.900 -56.300  1150.900 -69.700  1147.600 -69.700  1147.600 -77.800  1149.200 -77.800  1149.200 -81.200  1147.600 -81.200  1147.600 -99.300  1149.500 -99.300  1149.500 -102.700 ;
            POLYGON 1178.200 -102.700  1178.200 -56.300  1183.300 -56.300  1183.300 -69.700  1180.000 -69.700  1180.000 -77.800  1181.600 -77.800  1181.600 -81.200  1180.000 -81.200  1180.000 -99.300  1181.900 -99.300  1181.900 -102.700 ;
            POLYGON 956.800 -81.200  956.800 -77.800  957.600 -77.800  957.600 -72.700  960.200 -72.700  960.200 -81.200 ;
            POLYGON 832.600 -31.700  832.600 -23.200  836.000 -23.200  836.000 -26.600  835.200 -26.600  835.200 -31.700 ;
            POLYGON 865.000 -31.700  865.000 -23.200  868.400 -23.200  868.400 -26.600  867.600 -26.600  867.600 -31.700 ;
            POLYGON 897.400 -31.700  897.400 -23.200  900.800 -23.200  900.800 -26.600  900.000 -26.600  900.000 -31.700 ;
            POLYGON 929.800 -31.700  929.800 -23.200  933.200 -23.200  933.200 -26.600  932.400 -26.600  932.400 -31.700 ;
            POLYGON 962.200 -31.700  962.200 -23.200  965.600 -23.200  965.600 -26.600  964.800 -26.600  964.800 -31.700 ;
            POLYGON 994.600 -31.700  994.600 -23.200  998.000 -23.200  998.000 -26.600  997.200 -26.600  997.200 -31.700 ;
            POLYGON 1027.000 -31.700  1027.000 -23.200  1030.400 -23.200  1030.400 -26.600  1029.600 -26.600  1029.600 -31.700 ;
            POLYGON 892.000 -81.200  892.000 -77.800  892.800 -77.800  892.800 -72.700  895.400 -72.700  895.400 -81.200 ;
            POLYGON 1059.400 -31.700  1059.400 -23.200  1062.800 -23.200  1062.800 -26.600  1062.000 -26.600  1062.000 -31.700 ;
            POLYGON 1091.800 -31.700  1091.800 -23.200  1095.200 -23.200  1095.200 -26.600  1094.400 -26.600  1094.400 -31.700 ;
            POLYGON 1124.200 -31.700  1124.200 -23.200  1127.600 -23.200  1127.600 -26.600  1126.800 -26.600  1126.800 -31.700 ;
            POLYGON 1156.600 -31.700  1156.600 -23.200  1160.000 -23.200  1160.000 -26.600  1159.200 -26.600  1159.200 -31.700 ;
            POLYGON 1189.000 -31.700  1189.000 -23.200  1192.400 -23.200  1192.400 -26.600  1191.600 -26.600  1191.600 -31.700 ;
            POLYGON 827.200 -81.200  827.200 -77.800  828.000 -77.800  828.000 -72.700  830.600 -72.700  830.600 -81.200 ;
            POLYGON 836.300 -48.100  836.300 -34.700  839.600 -34.700  839.600 -26.600  838.000 -26.600  838.000 -23.200  839.600 -23.200  839.600 -5.100  837.700 -5.100  837.700 -1.700  841.400 -1.700  841.400 -48.100 ;
            POLYGON 868.700 -48.100  868.700 -34.700  872.000 -34.700  872.000 -26.600  870.400 -26.600  870.400 -23.200  872.000 -23.200  872.000 -5.100  870.100 -5.100  870.100 -1.700  873.800 -1.700  873.800 -48.100 ;
            POLYGON 901.100 -48.100  901.100 -34.700  904.400 -34.700  904.400 -26.600  902.800 -26.600  902.800 -23.200  904.400 -23.200  904.400 -5.100  902.500 -5.100  902.500 -1.700  906.200 -1.700  906.200 -48.100 ;
            POLYGON 933.500 -48.100  933.500 -34.700  936.800 -34.700  936.800 -26.600  935.200 -26.600  935.200 -23.200  936.800 -23.200  936.800 -5.100  934.900 -5.100  934.900 -1.700  938.600 -1.700  938.600 -48.100 ;
            POLYGON 965.900 -48.100  965.900 -34.700  969.200 -34.700  969.200 -26.600  967.600 -26.600  967.600 -23.200  969.200 -23.200  969.200 -5.100  967.300 -5.100  967.300 -1.700  971.000 -1.700  971.000 -48.100 ;
            POLYGON 998.300 -48.100  998.300 -34.700  1001.600 -34.700  1001.600 -26.600  1000.000 -26.600  1000.000 -23.200  1001.600 -23.200  1001.600 -5.100  999.700 -5.100  999.700 -1.700  1003.400 -1.700  1003.400 -48.100 ;
            POLYGON 1030.700 -48.100  1030.700 -34.700  1034.000 -34.700  1034.000 -26.600  1032.400 -26.600  1032.400 -23.200  1034.000 -23.200  1034.000 -5.100  1032.100 -5.100  1032.100 -1.700  1035.800 -1.700  1035.800 -48.100 ;
            POLYGON 1063.100 -48.100  1063.100 -34.700  1066.400 -34.700  1066.400 -26.600  1064.800 -26.600  1064.800 -23.200  1066.400 -23.200  1066.400 -5.100  1064.500 -5.100  1064.500 -1.700  1068.200 -1.700  1068.200 -48.100 ;
            POLYGON 1095.500 -48.100  1095.500 -34.700  1098.800 -34.700  1098.800 -26.600  1097.200 -26.600  1097.200 -23.200  1098.800 -23.200  1098.800 -5.100  1096.900 -5.100  1096.900 -1.700  1100.600 -1.700  1100.600 -48.100 ;
            POLYGON 1127.900 -48.100  1127.900 -34.700  1131.200 -34.700  1131.200 -26.600  1129.600 -26.600  1129.600 -23.200  1131.200 -23.200  1131.200 -5.100  1129.300 -5.100  1129.300 -1.700  1133.000 -1.700  1133.000 -48.100 ;
            POLYGON 1160.300 -48.100  1160.300 -34.700  1163.600 -34.700  1163.600 -26.600  1162.000 -26.600  1162.000 -23.200  1163.600 -23.200  1163.600 -5.100  1161.700 -5.100  1161.700 -1.700  1165.400 -1.700  1165.400 -48.100 ;
            POLYGON 1192.700 -48.100  1192.700 -34.700  1196.000 -34.700  1196.000 -26.600  1194.400 -26.600  1194.400 -23.200  1196.000 -23.200  1196.000 -5.100  1194.100 -5.100  1194.100 -1.700  1197.800 -1.700  1197.800 -48.100 ;
            POLYGON 859.600 -81.200  859.600 -77.800  860.400 -77.800  860.400 -72.700  863.000 -72.700  863.000 -81.200 ;
            POLYGON 989.200 -81.200  989.200 -77.800  990.000 -77.800  990.000 -72.700  992.600 -72.700  992.600 -81.200 ;
            POLYGON 1021.600 -81.200  1021.600 -77.800  1022.400 -77.800  1022.400 -72.700  1025.000 -72.700  1025.000 -81.200 ;
            POLYGON 1054.000 -81.200  1054.000 -77.800  1054.800 -77.800  1054.800 -72.700  1057.400 -72.700  1057.400 -81.200 ;
            POLYGON 1086.400 -81.200  1086.400 -77.800  1087.200 -77.800  1087.200 -72.700  1089.800 -72.700  1089.800 -81.200 ;
            POLYGON 1118.800 -81.200  1118.800 -77.800  1119.600 -77.800  1119.600 -72.700  1122.200 -72.700  1122.200 -81.200 ;
            POLYGON 1151.200 -81.200  1151.200 -77.800  1152.000 -77.800  1152.000 -72.700  1154.600 -72.700  1154.600 -81.200 ;
            POLYGON 924.400 -81.200  924.400 -77.800  925.200 -77.800  925.200 -72.700  927.800 -72.700  927.800 -81.200 ;
            POLYGON 1313.200 -81.200  1313.200 -77.800  1314.000 -77.800  1314.000 -72.700  1316.600 -72.700  1316.600 -81.200 ;
            POLYGON 1345.600 -81.200  1345.600 -77.800  1346.400 -77.800  1346.400 -72.700  1349.000 -72.700  1349.000 -81.200 ;
            POLYGON 1378.000 -81.200  1378.000 -77.800  1378.800 -77.800  1378.800 -72.700  1381.400 -72.700  1381.400 -81.200 ;
            POLYGON 1410.400 -81.200  1410.400 -77.800  1411.200 -77.800  1411.200 -72.700  1413.800 -72.700  1413.800 -81.200 ;
            POLYGON 1442.800 -81.200  1442.800 -77.800  1443.600 -77.800  1443.600 -72.700  1446.200 -72.700  1446.200 -81.200 ;
            POLYGON 1475.200 -81.200  1475.200 -77.800  1476.000 -77.800  1476.000 -72.700  1478.600 -72.700  1478.600 -81.200 ;
            POLYGON 1507.600 -81.200  1507.600 -77.800  1508.400 -77.800  1508.400 -72.700  1511.000 -72.700  1511.000 -81.200 ;
            POLYGON 1540.000 -81.200  1540.000 -77.800  1540.800 -77.800  1540.800 -72.700  1543.400 -72.700  1543.400 -81.200 ;
            POLYGON 1572.400 -81.200  1572.400 -77.800  1573.200 -77.800  1573.200 -72.700  1575.800 -72.700  1575.800 -81.200 ;
            POLYGON 1221.400 -31.700  1221.400 -23.200  1224.800 -23.200  1224.800 -26.600  1224.000 -26.600  1224.000 -31.700 ;
            POLYGON 1253.800 -31.700  1253.800 -23.200  1257.200 -23.200  1257.200 -26.600  1256.400 -26.600  1256.400 -31.700 ;
            POLYGON 1286.200 -31.700  1286.200 -23.200  1289.600 -23.200  1289.600 -26.600  1288.800 -26.600  1288.800 -31.700 ;
            POLYGON 1318.600 -31.700  1318.600 -23.200  1322.000 -23.200  1322.000 -26.600  1321.200 -26.600  1321.200 -31.700 ;
            POLYGON 1351.000 -31.700  1351.000 -23.200  1354.400 -23.200  1354.400 -26.600  1353.600 -26.600  1353.600 -31.700 ;
            POLYGON 1383.400 -31.700  1383.400 -23.200  1386.800 -23.200  1386.800 -26.600  1386.000 -26.600  1386.000 -31.700 ;
            POLYGON 1415.800 -31.700  1415.800 -23.200  1419.200 -23.200  1419.200 -26.600  1418.400 -26.600  1418.400 -31.700 ;
            POLYGON 1448.200 -31.700  1448.200 -23.200  1451.600 -23.200  1451.600 -26.600  1450.800 -26.600  1450.800 -31.700 ;
            POLYGON 1480.600 -31.700  1480.600 -23.200  1484.000 -23.200  1484.000 -26.600  1483.200 -26.600  1483.200 -31.700 ;
            POLYGON 1513.000 -31.700  1513.000 -23.200  1516.400 -23.200  1516.400 -26.600  1515.600 -26.600  1515.600 -31.700 ;
            POLYGON 1519.500 -31.700  1519.500 -26.600  1518.400 -26.600  1518.400 -23.200  1521.800 -23.200  1521.800 -29.100  1522.100 -29.100  1522.100 -31.700 ;
            POLYGON 1599.400 -31.700  1599.400 -23.200  1602.800 -23.200  1602.800 -26.600  1602.000 -26.600  1602.000 -31.700 ;
            POLYGON 1604.800 -81.200  1604.800 -77.800  1605.600 -77.800  1605.600 -72.700  1608.200 -72.700  1608.200 -81.200 ;
            POLYGON 1516.700 -48.100  1516.700 -34.700  1524.600 -34.700  1524.600 -33.900  1525.400 -33.900  1525.400 -14.800  1523.500 -14.800  1523.500 -11.400  1527.200 -11.400  1527.200 -36.500  1519.300 -36.500  1519.300 -48.100 ;
            POLYGON 1524.700 -48.100  1524.700 -37.900  1530.800 -37.900  1530.800 -26.600  1529.200 -26.600  1529.200 -23.200  1530.800 -23.200  1530.800 -6.300  1528.900 -6.300  1528.900 -2.900  1532.600 -2.900  1532.600 -39.800  1527.300 -39.800  1527.300 -48.100 ;
            POLYGON 1243.000 -102.700  1243.000 -56.300  1248.100 -56.300  1248.100 -69.700  1244.800 -69.700  1244.800 -77.800  1246.400 -77.800  1246.400 -81.200  1244.800 -81.200  1244.800 -99.300  1246.700 -99.300  1246.700 -102.700 ;
            POLYGON 1275.400 -102.700  1275.400 -56.300  1280.500 -56.300  1280.500 -69.700  1277.200 -69.700  1277.200 -77.800  1278.800 -77.800  1278.800 -81.200  1277.200 -81.200  1277.200 -99.300  1279.100 -99.300  1279.100 -102.700 ;
            POLYGON 1307.800 -102.700  1307.800 -56.300  1312.900 -56.300  1312.900 -69.700  1309.600 -69.700  1309.600 -77.800  1311.200 -77.800  1311.200 -81.200  1309.600 -81.200  1309.600 -99.300  1311.500 -99.300  1311.500 -102.700 ;
            POLYGON 1340.200 -102.700  1340.200 -56.300  1345.300 -56.300  1345.300 -69.700  1342.000 -69.700  1342.000 -77.800  1343.600 -77.800  1343.600 -81.200  1342.000 -81.200  1342.000 -99.300  1343.900 -99.300  1343.900 -102.700 ;
            POLYGON 1372.600 -102.700  1372.600 -56.300  1377.700 -56.300  1377.700 -69.700  1374.400 -69.700  1374.400 -77.800  1376.000 -77.800  1376.000 -81.200  1374.400 -81.200  1374.400 -99.300  1376.300 -99.300  1376.300 -102.700 ;
            POLYGON 1405.000 -102.700  1405.000 -56.300  1410.100 -56.300  1410.100 -69.700  1406.800 -69.700  1406.800 -77.800  1408.400 -77.800  1408.400 -81.200  1406.800 -81.200  1406.800 -99.300  1408.700 -99.300  1408.700 -102.700 ;
            POLYGON 1437.400 -102.700  1437.400 -56.300  1442.500 -56.300  1442.500 -69.700  1439.200 -69.700  1439.200 -77.800  1440.800 -77.800  1440.800 -81.200  1439.200 -81.200  1439.200 -99.300  1441.100 -99.300  1441.100 -102.700 ;
            POLYGON 1469.800 -102.700  1469.800 -56.300  1474.900 -56.300  1474.900 -69.700  1471.600 -69.700  1471.600 -77.800  1473.200 -77.800  1473.200 -81.200  1471.600 -81.200  1471.600 -99.300  1473.500 -99.300  1473.500 -102.700 ;
            POLYGON 1502.200 -102.700  1502.200 -56.300  1507.300 -56.300  1507.300 -69.700  1504.000 -69.700  1504.000 -77.800  1505.600 -77.800  1505.600 -81.200  1504.000 -81.200  1504.000 -99.300  1505.900 -99.300  1505.900 -102.700 ;
            POLYGON 1534.600 -102.700  1534.600 -56.300  1539.700 -56.300  1539.700 -69.700  1536.400 -69.700  1536.400 -77.800  1538.000 -77.800  1538.000 -81.200  1536.400 -81.200  1536.400 -99.300  1538.300 -99.300  1538.300 -102.700 ;
            POLYGON 1567.000 -102.700  1567.000 -56.300  1572.100 -56.300  1572.100 -69.700  1568.800 -69.700  1568.800 -77.800  1570.400 -77.800  1570.400 -81.200  1568.800 -81.200  1568.800 -99.300  1570.700 -99.300  1570.700 -102.700 ;
            POLYGON 1599.400 -102.700  1599.400 -56.300  1604.500 -56.300  1604.500 -69.700  1601.200 -69.700  1601.200 -77.800  1602.800 -77.800  1602.800 -81.200  1601.200 -81.200  1601.200 -99.300  1603.100 -99.300  1603.100 -102.700 ;
            POLYGON 1225.100 -48.100  1225.100 -34.700  1228.400 -34.700  1228.400 -26.600  1226.800 -26.600  1226.800 -23.200  1228.400 -23.200  1228.400 -5.100  1226.500 -5.100  1226.500 -1.700  1230.200 -1.700  1230.200 -48.100 ;
            POLYGON 1257.500 -48.100  1257.500 -34.700  1260.800 -34.700  1260.800 -26.600  1259.200 -26.600  1259.200 -23.200  1260.800 -23.200  1260.800 -5.100  1258.900 -5.100  1258.900 -1.700  1262.600 -1.700  1262.600 -48.100 ;
            POLYGON 1289.900 -48.100  1289.900 -34.700  1293.200 -34.700  1293.200 -26.600  1291.600 -26.600  1291.600 -23.200  1293.200 -23.200  1293.200 -5.100  1291.300 -5.100  1291.300 -1.700  1295.000 -1.700  1295.000 -48.100 ;
            POLYGON 1322.300 -48.100  1322.300 -34.700  1325.600 -34.700  1325.600 -26.600  1324.000 -26.600  1324.000 -23.200  1325.600 -23.200  1325.600 -5.100  1323.700 -5.100  1323.700 -1.700  1327.400 -1.700  1327.400 -48.100 ;
            POLYGON 1354.700 -48.100  1354.700 -34.700  1358.000 -34.700  1358.000 -26.600  1356.400 -26.600  1356.400 -23.200  1358.000 -23.200  1358.000 -5.100  1356.100 -5.100  1356.100 -1.700  1359.800 -1.700  1359.800 -48.100 ;
            POLYGON 1387.100 -48.100  1387.100 -34.700  1390.400 -34.700  1390.400 -26.600  1388.800 -26.600  1388.800 -23.200  1390.400 -23.200  1390.400 -5.100  1388.500 -5.100  1388.500 -1.700  1392.200 -1.700  1392.200 -48.100 ;
            POLYGON 1419.500 -48.100  1419.500 -34.700  1422.800 -34.700  1422.800 -26.600  1421.200 -26.600  1421.200 -23.200  1422.800 -23.200  1422.800 -5.100  1420.900 -5.100  1420.900 -1.700  1424.600 -1.700  1424.600 -48.100 ;
            POLYGON 1451.900 -48.100  1451.900 -34.700  1455.200 -34.700  1455.200 -26.600  1453.600 -26.600  1453.600 -23.200  1455.200 -23.200  1455.200 -5.100  1453.300 -5.100  1453.300 -1.700  1457.000 -1.700  1457.000 -48.100 ;
            POLYGON 1484.300 -48.100  1484.300 -34.700  1487.600 -34.700  1487.600 -26.600  1486.000 -26.600  1486.000 -23.200  1487.600 -23.200  1487.600 -5.100  1485.700 -5.100  1485.700 -1.700  1489.400 -1.700  1489.400 -48.100 ;
            POLYGON 1603.100 -48.100  1603.100 -34.700  1606.400 -34.700  1606.400 -26.600  1604.800 -26.600  1604.800 -23.200  1606.400 -23.200  1606.400 -5.100  1604.500 -5.100  1604.500 -1.700  1608.200 -1.700  1608.200 -23.200  1616.600 -23.200  1616.600 -26.600  1608.200 -26.600  1608.200 -36.500  1605.700 -36.500  1605.700 -48.100 ;
            POLYGON 1216.000 -81.200  1216.000 -77.800  1216.800 -77.800  1216.800 -72.700  1219.400 -72.700  1219.400 -81.200 ;
            POLYGON 1248.400 -81.200  1248.400 -77.800  1249.200 -77.800  1249.200 -72.700  1251.800 -72.700  1251.800 -81.200 ;
            POLYGON 1280.800 -81.200  1280.800 -77.800  1281.600 -77.800  1281.600 -72.700  1284.200 -72.700  1284.200 -81.200 ;
            POLYGON 400.600 -102.700  400.600 -56.300  405.700 -56.300  405.700 -69.700  402.400 -69.700  402.400 -77.800  404.000 -77.800  404.000 -81.200  402.400 -81.200  402.400 -99.300  404.300 -99.300  404.300 -102.700 ;
            POLYGON 403.100 61.100  403.100 72.700  400.600 72.700  400.600 107.500  404.300 107.500  404.300 104.100  402.400 104.100  402.400 86.000  404.000 86.000  404.000 82.600  402.400 82.600  402.400 74.500  405.700 74.500  405.700 61.100 ;
            POLYGON 476.200 28.000  476.200 36.500  478.800 36.500  478.800 31.400  479.600 31.400  479.600 28.000 ;
            POLYGON 508.600 28.000  508.600 36.500  511.200 36.500  511.200 31.400  512.000 31.400  512.000 28.000 ;
            POLYGON 541.000 28.000  541.000 36.500  543.600 36.500  543.600 31.400  544.400 31.400  544.400 28.000 ;
            POLYGON 573.400 28.000  573.400 36.500  576.000 36.500  576.000 31.400  576.800 31.400  576.800 28.000 ;
            POLYGON 605.800 28.000  605.800 36.500  608.400 36.500  608.400 31.400  609.200 31.400  609.200 28.000 ;
            POLYGON 638.200 28.000  638.200 36.500  640.800 36.500  640.800 31.400  641.600 31.400  641.600 28.000 ;
            POLYGON 670.600 28.000  670.600 36.500  673.200 36.500  673.200 31.400  674.000 31.400  674.000 28.000 ;
            POLYGON 703.000 28.000  703.000 36.500  705.600 36.500  705.600 31.400  706.400 31.400  706.400 28.000 ;
            POLYGON 735.400 28.000  735.400 36.500  738.000 36.500  738.000 31.400  738.800 31.400  738.800 28.000 ;
            POLYGON 767.800 28.000  767.800 36.500  770.400 36.500  770.400 31.400  771.200 31.400  771.200 28.000 ;
            POLYGON 800.200 28.000  800.200 36.500  802.800 36.500  802.800 31.400  803.600 31.400  803.600 28.000 ;
            POLYGON 416.500 6.500  416.500 9.900  418.400 9.900  418.400 28.000  416.800 28.000  416.800 31.400  418.400 31.400  418.400 39.500  415.100 39.500  415.100 52.900  417.700 52.900  417.700 41.300  420.200 41.300  420.200 6.500 ;
            POLYGON 448.900 6.500  448.900 9.900  450.800 9.900  450.800 28.000  449.200 28.000  449.200 31.400  450.800 31.400  450.800 39.500  447.500 39.500  447.500 52.900  450.100 52.900  450.100 41.300  452.600 41.300  452.600 6.500 ;
            POLYGON 481.300 6.500  481.300 9.900  483.200 9.900  483.200 28.000  481.600 28.000  481.600 31.400  483.200 31.400  483.200 39.500  479.900 39.500  479.900 52.900  482.500 52.900  482.500 41.300  485.000 41.300  485.000 6.500 ;
            POLYGON 513.700 6.500  513.700 9.900  515.600 9.900  515.600 28.000  514.000 28.000  514.000 31.400  515.600 31.400  515.600 39.500  512.300 39.500  512.300 52.900  514.900 52.900  514.900 41.300  517.400 41.300  517.400 6.500 ;
            POLYGON 546.100 6.500  546.100 9.900  548.000 9.900  548.000 28.000  546.400 28.000  546.400 31.400  548.000 31.400  548.000 39.500  544.700 39.500  544.700 52.900  547.300 52.900  547.300 41.300  549.800 41.300  549.800 6.500 ;
            POLYGON 578.500 6.500  578.500 9.900  580.400 9.900  580.400 28.000  578.800 28.000  578.800 31.400  580.400 31.400  580.400 39.500  577.100 39.500  577.100 52.900  579.700 52.900  579.700 41.300  582.200 41.300  582.200 6.500 ;
            POLYGON 610.900 6.500  610.900 9.900  612.800 9.900  612.800 28.000  611.200 28.000  611.200 31.400  612.800 31.400  612.800 39.500  609.500 39.500  609.500 52.900  612.100 52.900  612.100 41.300  614.600 41.300  614.600 6.500 ;
            POLYGON 643.300 6.500  643.300 9.900  645.200 9.900  645.200 28.000  643.600 28.000  643.600 31.400  645.200 31.400  645.200 39.500  641.900 39.500  641.900 52.900  644.500 52.900  644.500 41.300  647.000 41.300  647.000 6.500 ;
            POLYGON 675.700 6.500  675.700 9.900  677.600 9.900  677.600 28.000  676.000 28.000  676.000 31.400  677.600 31.400  677.600 39.500  674.300 39.500  674.300 52.900  676.900 52.900  676.900 41.300  679.400 41.300  679.400 6.500 ;
            POLYGON 708.100 6.500  708.100 9.900  710.000 9.900  710.000 28.000  708.400 28.000  708.400 31.400  710.000 31.400  710.000 39.500  706.700 39.500  706.700 52.900  709.300 52.900  709.300 41.300  711.800 41.300  711.800 6.500 ;
            POLYGON 740.500 6.500  740.500 9.900  742.400 9.900  742.400 28.000  740.800 28.000  740.800 31.400  742.400 31.400  742.400 39.500  739.100 39.500  739.100 52.900  741.700 52.900  741.700 41.300  744.200 41.300  744.200 6.500 ;
            POLYGON 772.900 6.500  772.900 9.900  774.800 9.900  774.800 28.000  773.200 28.000  773.200 31.400  774.800 31.400  774.800 39.500  771.500 39.500  771.500 52.900  774.100 52.900  774.100 41.300  776.600 41.300  776.600 6.500 ;
            POLYGON 805.300 6.500  805.300 9.900  807.200 9.900  807.200 28.000  805.600 28.000  805.600 31.400  807.200 31.400  807.200 39.500  803.900 39.500  803.900 52.900  806.500 52.900  806.500 41.300  809.000 41.300  809.000 6.500 ;
            POLYGON 411.400 28.000  411.400 36.500  414.000 36.500  414.000 31.400  414.800 31.400  414.800 28.000 ;
            POLYGON 406.800 77.500  406.800 82.600  406.000 82.600  406.000 86.000  409.400 86.000  409.400 77.500 ;
            POLYGON 439.200 77.500  439.200 82.600  438.400 82.600  438.400 86.000  441.800 86.000  441.800 77.500 ;
            POLYGON 471.600 77.500  471.600 82.600  470.800 82.600  470.800 86.000  474.200 86.000  474.200 77.500 ;
            POLYGON 504.000 77.500  504.000 82.600  503.200 82.600  503.200 86.000  506.600 86.000  506.600 77.500 ;
            POLYGON 536.400 77.500  536.400 82.600  535.600 82.600  535.600 86.000  539.000 86.000  539.000 77.500 ;
            POLYGON 568.800 77.500  568.800 82.600  568.000 82.600  568.000 86.000  571.400 86.000  571.400 77.500 ;
            POLYGON 601.200 77.500  601.200 82.600  600.400 82.600  600.400 86.000  603.800 86.000  603.800 77.500 ;
            POLYGON 633.600 77.500  633.600 82.600  632.800 82.600  632.800 86.000  636.200 86.000  636.200 77.500 ;
            POLYGON 666.000 77.500  666.000 82.600  665.200 82.600  665.200 86.000  668.600 86.000  668.600 77.500 ;
            POLYGON 698.400 77.500  698.400 82.600  697.600 82.600  697.600 86.000  701.000 86.000  701.000 77.500 ;
            POLYGON 730.800 77.500  730.800 82.600  730.000 82.600  730.000 86.000  733.400 86.000  733.400 77.500 ;
            POLYGON 763.200 77.500  763.200 82.600  762.400 82.600  762.400 86.000  765.800 86.000  765.800 77.500 ;
            POLYGON 795.600 77.500  795.600 82.600  794.800 82.600  794.800 86.000  798.200 86.000  798.200 77.500 ;
            POLYGON 443.800 28.000  443.800 36.500  446.400 36.500  446.400 31.400  447.200 31.400  447.200 28.000 ;
            POLYGON 435.500 61.100  435.500 72.700  433.000 72.700  433.000 107.500  436.700 107.500  436.700 104.100  434.800 104.100  434.800 86.000  436.400 86.000  436.400 82.600  434.800 82.600  434.800 74.500  438.100 74.500  438.100 61.100 ;
            POLYGON 467.900 61.100  467.900 72.700  465.400 72.700  465.400 107.500  469.100 107.500  469.100 104.100  467.200 104.100  467.200 86.000  468.800 86.000  468.800 82.600  467.200 82.600  467.200 74.500  470.500 74.500  470.500 61.100 ;
            POLYGON 500.300 61.100  500.300 72.700  497.800 72.700  497.800 107.500  501.500 107.500  501.500 104.100  499.600 104.100  499.600 86.000  501.200 86.000  501.200 82.600  499.600 82.600  499.600 74.500  502.900 74.500  502.900 61.100 ;
            POLYGON 532.700 61.100  532.700 72.700  530.200 72.700  530.200 107.500  533.900 107.500  533.900 104.100  532.000 104.100  532.000 86.000  533.600 86.000  533.600 82.600  532.000 82.600  532.000 74.500  535.300 74.500  535.300 61.100 ;
            POLYGON 565.100 61.100  565.100 72.700  562.600 72.700  562.600 107.500  566.300 107.500  566.300 104.100  564.400 104.100  564.400 86.000  566.000 86.000  566.000 82.600  564.400 82.600  564.400 74.500  567.700 74.500  567.700 61.100 ;
            POLYGON 597.500 61.100  597.500 72.700  595.000 72.700  595.000 107.500  598.700 107.500  598.700 104.100  596.800 104.100  596.800 86.000  598.400 86.000  598.400 82.600  596.800 82.600  596.800 74.500  600.100 74.500  600.100 61.100 ;
            POLYGON 629.900 61.100  629.900 72.700  627.400 72.700  627.400 107.500  631.100 107.500  631.100 104.100  629.200 104.100  629.200 86.000  630.800 86.000  630.800 82.600  629.200 82.600  629.200 74.500  632.500 74.500  632.500 61.100 ;
            POLYGON 662.300 61.100  662.300 72.700  659.800 72.700  659.800 107.500  663.500 107.500  663.500 104.100  661.600 104.100  661.600 86.000  663.200 86.000  663.200 82.600  661.600 82.600  661.600 74.500  664.900 74.500  664.900 61.100 ;
            POLYGON 694.700 61.100  694.700 72.700  692.200 72.700  692.200 107.500  695.900 107.500  695.900 104.100  694.000 104.100  694.000 86.000  695.600 86.000  695.600 82.600  694.000 82.600  694.000 74.500  697.300 74.500  697.300 61.100 ;
            POLYGON 727.100 61.100  727.100 72.700  724.600 72.700  724.600 107.500  728.300 107.500  728.300 104.100  726.400 104.100  726.400 86.000  728.000 86.000  728.000 82.600  726.400 82.600  726.400 74.500  729.700 74.500  729.700 61.100 ;
            POLYGON 759.500 61.100  759.500 72.700  757.000 72.700  757.000 107.500  760.700 107.500  760.700 104.100  758.800 104.100  758.800 86.000  760.400 86.000  760.400 82.600  758.800 82.600  758.800 74.500  762.100 74.500  762.100 61.100 ;
            POLYGON 791.900 61.100  791.900 72.700  789.400 72.700  789.400 107.500  793.100 107.500  793.100 104.100  791.200 104.100  791.200 86.000  792.800 86.000  792.800 82.600  791.200 82.600  791.200 74.500  794.500 74.500  794.500 61.100 ;
            POLYGON 180.000 77.500  180.000 82.600  179.200 82.600  179.200 86.000  182.600 86.000  182.600 77.500 ;
            POLYGON 212.400 77.500  212.400 82.600  211.600 82.600  211.600 86.000  215.000 86.000  215.000 77.500 ;
            POLYGON 244.800 77.500  244.800 82.600  244.000 82.600  244.000 86.000  247.400 86.000  247.400 77.500 ;
            POLYGON 277.200 77.500  277.200 82.600  276.400 82.600  276.400 86.000  279.800 86.000  279.800 77.500 ;
            POLYGON 309.600 77.500  309.600 82.600  308.800 82.600  308.800 86.000  312.200 86.000  312.200 77.500 ;
            POLYGON 342.000 77.500  342.000 82.600  341.200 82.600  341.200 86.000  344.600 86.000  344.600 77.500 ;
            POLYGON 374.400 77.500  374.400 82.600  373.600 82.600  373.600 86.000  377.000 86.000  377.000 77.500 ;
            POLYGON 157.300 6.500  157.300 9.900  159.200 9.900  159.200 28.000  157.600 28.000  157.600 31.400  159.200 31.400  159.200 39.500  155.900 39.500  155.900 52.900  158.500 52.900  158.500 41.300  161.000 41.300  161.000 6.500 ;
            POLYGON 189.700 6.500  189.700 9.900  191.600 9.900  191.600 28.000  190.000 28.000  190.000 31.400  191.600 31.400  191.600 39.500  188.300 39.500  188.300 52.900  190.900 52.900  190.900 41.300  193.400 41.300  193.400 6.500 ;
            POLYGON 222.100 6.500  222.100 9.900  224.000 9.900  224.000 28.000  222.400 28.000  222.400 31.400  224.000 31.400  224.000 39.500  220.700 39.500  220.700 52.900  223.300 52.900  223.300 41.300  225.800 41.300  225.800 6.500 ;
            POLYGON 254.500 6.500  254.500 9.900  256.400 9.900  256.400 28.000  254.800 28.000  254.800 31.400  256.400 31.400  256.400 39.500  253.100 39.500  253.100 52.900  255.700 52.900  255.700 41.300  258.200 41.300  258.200 6.500 ;
            POLYGON 286.900 6.500  286.900 9.900  288.800 9.900  288.800 28.000  287.200 28.000  287.200 31.400  288.800 31.400  288.800 39.500  285.500 39.500  285.500 52.900  288.100 52.900  288.100 41.300  290.600 41.300  290.600 6.500 ;
            POLYGON 319.300 6.500  319.300 9.900  321.200 9.900  321.200 28.000  319.600 28.000  319.600 31.400  321.200 31.400  321.200 39.500  317.900 39.500  317.900 52.900  320.500 52.900  320.500 41.300  323.000 41.300  323.000 6.500 ;
            POLYGON 351.700 6.500  351.700 9.900  353.600 9.900  353.600 28.000  352.000 28.000  352.000 31.400  353.600 31.400  353.600 39.500  350.300 39.500  350.300 52.900  352.900 52.900  352.900 41.300  355.400 41.300  355.400 6.500 ;
            POLYGON 384.100 6.500  384.100 9.900  386.000 9.900  386.000 28.000  384.400 28.000  384.400 31.400  386.000 31.400  386.000 39.500  382.700 39.500  382.700 52.900  385.300 52.900  385.300 41.300  387.800 41.300  387.800 6.500 ;
            POLYGON 184.600 28.000  184.600 36.500  187.200 36.500  187.200 31.400  188.000 31.400  188.000 28.000 ;
            POLYGON 217.000 28.000  217.000 36.500  219.600 36.500  219.600 31.400  220.400 31.400  220.400 28.000 ;
            POLYGON 249.400 28.000  249.400 36.500  252.000 36.500  252.000 31.400  252.800 31.400  252.800 28.000 ;
            POLYGON 281.800 28.000  281.800 36.500  284.400 36.500  284.400 31.400  285.200 31.400  285.200 28.000 ;
            POLYGON 314.200 28.000  314.200 36.500  316.800 36.500  316.800 31.400  317.600 31.400  317.600 28.000 ;
            POLYGON 46.700 61.100  46.700 72.700  44.200 72.700  44.200 107.500  47.900 107.500  47.900 104.100  46.000 104.100  46.000 86.000  47.600 86.000  47.600 82.600  46.000 82.600  46.000 74.500  49.300 74.500  49.300 61.100 ;
            POLYGON 79.100 61.100  79.100 72.700  76.600 72.700  76.600 107.500  80.300 107.500  80.300 104.100  78.400 104.100  78.400 86.000  80.000 86.000  80.000 82.600  78.400 82.600  78.400 74.500  81.700 74.500  81.700 61.100 ;
            POLYGON 111.500 61.100  111.500 72.700  109.000 72.700  109.000 107.500  112.700 107.500  112.700 104.100  110.800 104.100  110.800 86.000  112.400 86.000  112.400 82.600  110.800 82.600  110.800 74.500  114.100 74.500  114.100 61.100 ;
            POLYGON 143.900 61.100  143.900 72.700  141.400 72.700  141.400 107.500  145.100 107.500  145.100 104.100  143.200 104.100  143.200 86.000  144.800 86.000  144.800 82.600  143.200 82.600  143.200 74.500  146.500 74.500  146.500 61.100 ;
            POLYGON 176.300 61.100  176.300 72.700  173.800 72.700  173.800 107.500  177.500 107.500  177.500 104.100  175.600 104.100  175.600 86.000  177.200 86.000  177.200 82.600  175.600 82.600  175.600 74.500  178.900 74.500  178.900 61.100 ;
            POLYGON 208.700 61.100  208.700 72.700  206.200 72.700  206.200 107.500  209.900 107.500  209.900 104.100  208.000 104.100  208.000 86.000  209.600 86.000  209.600 82.600  208.000 82.600  208.000 74.500  211.300 74.500  211.300 61.100 ;
            POLYGON 241.100 61.100  241.100 72.700  238.600 72.700  238.600 107.500  242.300 107.500  242.300 104.100  240.400 104.100  240.400 86.000  242.000 86.000  242.000 82.600  240.400 82.600  240.400 74.500  243.700 74.500  243.700 61.100 ;
            POLYGON 273.500 61.100  273.500 72.700  271.000 72.700  271.000 107.500  274.700 107.500  274.700 104.100  272.800 104.100  272.800 86.000  274.400 86.000  274.400 82.600  272.800 82.600  272.800 74.500  276.100 74.500  276.100 61.100 ;
            POLYGON 305.900 61.100  305.900 72.700  303.400 72.700  303.400 107.500  307.100 107.500  307.100 104.100  305.200 104.100  305.200 86.000  306.800 86.000  306.800 82.600  305.200 82.600  305.200 74.500  308.500 74.500  308.500 61.100 ;
            POLYGON 338.300 61.100  338.300 72.700  335.800 72.700  335.800 107.500  339.500 107.500  339.500 104.100  337.600 104.100  337.600 86.000  339.200 86.000  339.200 82.600  337.600 82.600  337.600 74.500  340.900 74.500  340.900 61.100 ;
            POLYGON 370.700 61.100  370.700 72.700  368.200 72.700  368.200 107.500  371.900 107.500  371.900 104.100  370.000 104.100  370.000 86.000  371.600 86.000  371.600 82.600  370.000 82.600  370.000 74.500  373.300 74.500  373.300 61.100 ;
            POLYGON 346.600 28.000  346.600 36.500  349.200 36.500  349.200 31.400  350.000 31.400  350.000 28.000 ;
            POLYGON 379.000 28.000  379.000 36.500  381.600 36.500  381.600 31.400  382.400 31.400  382.400 28.000 ;
            POLYGON 87.400 28.000  87.400 36.500  90.000 36.500  90.000 31.400  90.800 31.400  90.800 28.000 ;
            POLYGON 119.800 28.000  119.800 36.500  122.400 36.500  122.400 31.400  123.200 31.400  123.200 28.000 ;
            POLYGON 152.200 28.000  152.200 36.500  154.800 36.500  154.800 31.400  155.600 31.400  155.600 28.000 ;
            POLYGON 27.700 6.500  27.700 9.900  29.600 9.900  29.600 28.000  28.000 28.000  28.000 31.400  29.600 31.400  29.600 39.500  26.300 39.500  26.300 52.900  28.900 52.900  28.900 41.300  31.400 41.300  31.400 6.500 ;
            POLYGON 60.100 6.500  60.100 9.900  62.000 9.900  62.000 28.000  60.400 28.000  60.400 31.400  62.000 31.400  62.000 39.500  58.700 39.500  58.700 52.900  61.300 52.900  61.300 41.300  63.800 41.300  63.800 6.500 ;
            POLYGON 92.500 6.500  92.500 9.900  94.400 9.900  94.400 28.000  92.800 28.000  92.800 31.400  94.400 31.400  94.400 39.500  91.100 39.500  91.100 52.900  93.700 52.900  93.700 41.300  96.200 41.300  96.200 6.500 ;
            POLYGON 124.900 6.500  124.900 9.900  126.800 9.900  126.800 28.000  125.200 28.000  125.200 31.400  126.800 31.400  126.800 39.500  123.500 39.500  123.500 52.900  126.100 52.900  126.100 41.300  128.600 41.300  128.600 6.500 ;
            POLYGON 50.400 77.500  50.400 82.600  49.600 82.600  49.600 86.000  53.000 86.000  53.000 77.500 ;
            POLYGON 82.800 77.500  82.800 82.600  82.000 82.600  82.000 86.000  85.400 86.000  85.400 77.500 ;
            POLYGON 115.200 77.500  115.200 82.600  114.400 82.600  114.400 86.000  117.800 86.000  117.800 77.500 ;
            POLYGON 147.600 77.500  147.600 82.600  146.800 82.600  146.800 86.000  150.200 86.000  150.200 77.500 ;
            POLYGON 22.600 28.000  22.600 36.500  25.200 36.500  25.200 31.400  26.000 31.400  26.000 28.000 ;
            POLYGON 55.000 28.000  55.000 36.500  57.600 36.500  57.600 31.400  58.400 31.400  58.400 28.000 ;
            POLYGON 91.100 -48.100  91.100 -34.700  94.400 -34.700  94.400 -26.600  92.800 -26.600  92.800 -23.200  94.400 -23.200  94.400 -5.100  92.500 -5.100  92.500 -1.700  96.200 -1.700  96.200 -48.100 ;
            POLYGON 123.500 -48.100  123.500 -34.700  126.800 -34.700  126.800 -26.600  125.200 -26.600  125.200 -23.200  126.800 -23.200  126.800 -5.100  124.900 -5.100  124.900 -1.700  128.600 -1.700  128.600 -48.100 ;
            POLYGON 155.900 -48.100  155.900 -34.700  159.200 -34.700  159.200 -26.600  157.600 -26.600  157.600 -23.200  159.200 -23.200  159.200 -5.100  157.300 -5.100  157.300 -1.700  161.000 -1.700  161.000 -48.100 ;
            POLYGON 188.300 -48.100  188.300 -34.700  191.600 -34.700  191.600 -26.600  190.000 -26.600  190.000 -23.200  191.600 -23.200  191.600 -5.100  189.700 -5.100  189.700 -1.700  193.400 -1.700  193.400 -48.100 ;
            POLYGON 220.700 -48.100  220.700 -34.700  224.000 -34.700  224.000 -26.600  222.400 -26.600  222.400 -23.200  224.000 -23.200  224.000 -5.100  222.100 -5.100  222.100 -1.700  225.800 -1.700  225.800 -48.100 ;
            POLYGON 253.100 -48.100  253.100 -34.700  256.400 -34.700  256.400 -26.600  254.800 -26.600  254.800 -23.200  256.400 -23.200  256.400 -5.100  254.500 -5.100  254.500 -1.700  258.200 -1.700  258.200 -48.100 ;
            POLYGON 285.500 -48.100  285.500 -34.700  288.800 -34.700  288.800 -26.600  287.200 -26.600  287.200 -23.200  288.800 -23.200  288.800 -5.100  286.900 -5.100  286.900 -1.700  290.600 -1.700  290.600 -48.100 ;
            POLYGON 317.900 -48.100  317.900 -34.700  321.200 -34.700  321.200 -26.600  319.600 -26.600  319.600 -23.200  321.200 -23.200  321.200 -5.100  319.300 -5.100  319.300 -1.700  323.000 -1.700  323.000 -48.100 ;
            POLYGON 350.300 -48.100  350.300 -34.700  353.600 -34.700  353.600 -26.600  352.000 -26.600  352.000 -23.200  353.600 -23.200  353.600 -5.100  351.700 -5.100  351.700 -1.700  355.400 -1.700  355.400 -48.100 ;
            POLYGON 382.700 -48.100  382.700 -34.700  386.000 -34.700  386.000 -26.600  384.400 -26.600  384.400 -23.200  386.000 -23.200  386.000 -5.100  384.100 -5.100  384.100 -1.700  387.800 -1.700  387.800 -48.100 ;
            POLYGON 281.800 -31.700  281.800 -23.200  285.200 -23.200  285.200 -26.600  284.400 -26.600  284.400 -31.700 ;
            POLYGON 314.200 -31.700  314.200 -23.200  317.600 -23.200  317.600 -26.600  316.800 -26.600  316.800 -31.700 ;
            POLYGON 346.600 -31.700  346.600 -23.200  350.000 -23.200  350.000 -26.600  349.200 -26.600  349.200 -31.700 ;
            POLYGON 379.000 -31.700  379.000 -23.200  382.400 -23.200  382.400 -26.600  381.600 -26.600  381.600 -31.700 ;
            POLYGON 76.600 -102.700  76.600 -56.300  81.700 -56.300  81.700 -69.700  78.400 -69.700  78.400 -77.800  80.000 -77.800  80.000 -81.200  78.400 -81.200  78.400 -99.300  80.300 -99.300  80.300 -102.700 ;
            POLYGON 87.400 -31.700  87.400 -23.200  90.800 -23.200  90.800 -26.600  90.000 -26.600  90.000 -31.700 ;
            POLYGON 119.800 -31.700  119.800 -23.200  123.200 -23.200  123.200 -26.600  122.400 -26.600  122.400 -31.700 ;
            POLYGON 152.200 -31.700  152.200 -23.200  155.600 -23.200  155.600 -26.600  154.800 -26.600  154.800 -31.700 ;
            POLYGON 109.000 -102.700  109.000 -56.300  114.100 -56.300  114.100 -69.700  110.800 -69.700  110.800 -77.800  112.400 -77.800  112.400 -81.200  110.800 -81.200  110.800 -99.300  112.700 -99.300  112.700 -102.700 ;
            POLYGON 141.400 -102.700  141.400 -56.300  146.500 -56.300  146.500 -69.700  143.200 -69.700  143.200 -77.800  144.800 -77.800  144.800 -81.200  143.200 -81.200  143.200 -99.300  145.100 -99.300  145.100 -102.700 ;
            POLYGON 173.800 -102.700  173.800 -56.300  178.900 -56.300  178.900 -69.700  175.600 -69.700  175.600 -77.800  177.200 -77.800  177.200 -81.200  175.600 -81.200  175.600 -99.300  177.500 -99.300  177.500 -102.700 ;
            POLYGON 206.200 -102.700  206.200 -56.300  211.300 -56.300  211.300 -69.700  208.000 -69.700  208.000 -77.800  209.600 -77.800  209.600 -81.200  208.000 -81.200  208.000 -99.300  209.900 -99.300  209.900 -102.700 ;
            POLYGON 238.600 -102.700  238.600 -56.300  243.700 -56.300  243.700 -69.700  240.400 -69.700  240.400 -77.800  242.000 -77.800  242.000 -81.200  240.400 -81.200  240.400 -99.300  242.300 -99.300  242.300 -102.700 ;
            POLYGON 271.000 -102.700  271.000 -56.300  276.100 -56.300  276.100 -69.700  272.800 -69.700  272.800 -77.800  274.400 -77.800  274.400 -81.200  272.800 -81.200  272.800 -99.300  274.700 -99.300  274.700 -102.700 ;
            POLYGON 303.400 -102.700  303.400 -56.300  308.500 -56.300  308.500 -69.700  305.200 -69.700  305.200 -77.800  306.800 -77.800  306.800 -81.200  305.200 -81.200  305.200 -99.300  307.100 -99.300  307.100 -102.700 ;
            POLYGON 335.800 -102.700  335.800 -56.300  340.900 -56.300  340.900 -69.700  337.600 -69.700  337.600 -77.800  339.200 -77.800  339.200 -81.200  337.600 -81.200  337.600 -99.300  339.500 -99.300  339.500 -102.700 ;
            POLYGON 368.200 -102.700  368.200 -56.300  373.300 -56.300  373.300 -69.700  370.000 -69.700  370.000 -77.800  371.600 -77.800  371.600 -81.200  370.000 -81.200  370.000 -99.300  371.900 -99.300  371.900 -102.700 ;
            POLYGON 184.600 -31.700  184.600 -23.200  188.000 -23.200  188.000 -26.600  187.200 -26.600  187.200 -31.700 ;
            POLYGON 82.000 -81.200  82.000 -77.800  82.800 -77.800  82.800 -72.700  85.400 -72.700  85.400 -81.200 ;
            POLYGON 114.400 -81.200  114.400 -77.800  115.200 -77.800  115.200 -72.700  117.800 -72.700  117.800 -81.200 ;
            POLYGON 217.000 -31.700  217.000 -23.200  220.400 -23.200  220.400 -26.600  219.600 -26.600  219.600 -31.700 ;
            POLYGON 249.400 -31.700  249.400 -23.200  252.800 -23.200  252.800 -26.600  252.000 -26.600  252.000 -31.700 ;
            POLYGON 146.800 -81.200  146.800 -77.800  147.600 -77.800  147.600 -72.700  150.200 -72.700  150.200 -81.200 ;
            POLYGON 179.200 -81.200  179.200 -77.800  180.000 -77.800  180.000 -72.700  182.600 -72.700  182.600 -81.200 ;
            POLYGON 211.600 -81.200  211.600 -77.800  212.400 -77.800  212.400 -72.700  215.000 -72.700  215.000 -81.200 ;
            POLYGON 244.000 -81.200  244.000 -77.800  244.800 -77.800  244.800 -72.700  247.400 -72.700  247.400 -81.200 ;
            POLYGON 276.400 -81.200  276.400 -77.800  277.200 -77.800  277.200 -72.700  279.800 -72.700  279.800 -81.200 ;
            POLYGON 308.800 -81.200  308.800 -77.800  309.600 -77.800  309.600 -72.700  312.200 -72.700  312.200 -81.200 ;
            POLYGON 341.200 -81.200  341.200 -77.800  342.000 -77.800  342.000 -72.700  344.600 -72.700  344.600 -81.200 ;
            POLYGON 373.600 -81.200  373.600 -77.800  374.400 -77.800  374.400 -72.700  377.000 -72.700  377.000 -81.200 ;
            POLYGON 49.600 -81.200  49.600 -77.800  50.400 -77.800  50.400 -72.700  53.000 -72.700  53.000 -81.200 ;
            POLYGON 44.200 -102.700  44.200 -56.300  49.300 -56.300  49.300 -69.700  46.000 -69.700  46.000 -77.800  47.600 -77.800  47.600 -81.200  46.000 -81.200  46.000 -99.300  47.900 -99.300  47.900 -102.700 ;
            POLYGON 22.600 -31.700  22.600 -23.200  26.000 -23.200  26.000 -26.600  25.200 -26.600  25.200 -31.700 ;
            POLYGON 55.000 -31.700  55.000 -23.200  58.400 -23.200  58.400 -26.600  57.600 -26.600  57.600 -31.700 ;
            POLYGON 26.300 -48.100  26.300 -34.700  29.600 -34.700  29.600 -26.600  28.000 -26.600  28.000 -23.200  29.600 -23.200  29.600 -5.100  27.700 -5.100  27.700 -1.700  31.400 -1.700  31.400 -48.100 ;
            POLYGON 58.700 -48.100  58.700 -34.700  62.000 -34.700  62.000 -26.600  60.400 -26.600  60.400 -23.200  62.000 -23.200  62.000 -5.100  60.100 -5.100  60.100 -1.700  63.800 -1.700  63.800 -48.100 ;
            POLYGON 771.500 -48.100  771.500 -34.700  774.800 -34.700  774.800 -26.600  773.200 -26.600  773.200 -23.200  774.800 -23.200  774.800 -5.100  772.900 -5.100  772.900 -1.700  776.600 -1.700  776.600 -48.100 ;
            POLYGON 497.800 -102.700  497.800 -56.300  502.900 -56.300  502.900 -69.700  499.600 -69.700  499.600 -77.800  501.200 -77.800  501.200 -81.200  499.600 -81.200  499.600 -99.300  501.500 -99.300  501.500 -102.700 ;
            POLYGON 530.200 -102.700  530.200 -56.300  535.300 -56.300  535.300 -69.700  532.000 -69.700  532.000 -77.800  533.600 -77.800  533.600 -81.200  532.000 -81.200  532.000 -99.300  533.900 -99.300  533.900 -102.700 ;
            POLYGON 562.600 -102.700  562.600 -56.300  567.700 -56.300  567.700 -69.700  564.400 -69.700  564.400 -77.800  566.000 -77.800  566.000 -81.200  564.400 -81.200  564.400 -99.300  566.300 -99.300  566.300 -102.700 ;
            POLYGON 595.000 -102.700  595.000 -56.300  600.100 -56.300  600.100 -69.700  596.800 -69.700  596.800 -77.800  598.400 -77.800  598.400 -81.200  596.800 -81.200  596.800 -99.300  598.700 -99.300  598.700 -102.700 ;
            POLYGON 627.400 -102.700  627.400 -56.300  632.500 -56.300  632.500 -69.700  629.200 -69.700  629.200 -77.800  630.800 -77.800  630.800 -81.200  629.200 -81.200  629.200 -99.300  631.100 -99.300  631.100 -102.700 ;
            POLYGON 659.800 -102.700  659.800 -56.300  664.900 -56.300  664.900 -69.700  661.600 -69.700  661.600 -77.800  663.200 -77.800  663.200 -81.200  661.600 -81.200  661.600 -99.300  663.500 -99.300  663.500 -102.700 ;
            POLYGON 692.200 -102.700  692.200 -56.300  697.300 -56.300  697.300 -69.700  694.000 -69.700  694.000 -77.800  695.600 -77.800  695.600 -81.200  694.000 -81.200  694.000 -99.300  695.900 -99.300  695.900 -102.700 ;
            POLYGON 724.600 -102.700  724.600 -56.300  729.700 -56.300  729.700 -69.700  726.400 -69.700  726.400 -77.800  728.000 -77.800  728.000 -81.200  726.400 -81.200  726.400 -99.300  728.300 -99.300  728.300 -102.700 ;
            POLYGON 757.000 -102.700  757.000 -56.300  762.100 -56.300  762.100 -69.700  758.800 -69.700  758.800 -77.800  760.400 -77.800  760.400 -81.200  758.800 -81.200  758.800 -99.300  760.700 -99.300  760.700 -102.700 ;
            POLYGON 789.400 -102.700  789.400 -56.300  794.500 -56.300  794.500 -69.700  791.200 -69.700  791.200 -77.800  792.800 -77.800  792.800 -81.200  791.200 -81.200  791.200 -99.300  793.100 -99.300  793.100 -102.700 ;
            POLYGON 735.400 -31.700  735.400 -23.200  738.800 -23.200  738.800 -26.600  738.000 -26.600  738.000 -31.700 ;
            POLYGON 767.800 -31.700  767.800 -23.200  771.200 -23.200  771.200 -26.600  770.400 -26.600  770.400 -31.700 ;
            POLYGON 800.200 -31.700  800.200 -23.200  803.600 -23.200  803.600 -26.600  802.800 -26.600  802.800 -31.700 ;
            POLYGON 411.400 -31.700  411.400 -23.200  414.800 -23.200  414.800 -26.600  414.000 -26.600  414.000 -31.700 ;
            POLYGON 443.800 -31.700  443.800 -23.200  447.200 -23.200  447.200 -26.600  446.400 -26.600  446.400 -31.700 ;
            POLYGON 476.200 -31.700  476.200 -23.200  479.600 -23.200  479.600 -26.600  478.800 -26.600  478.800 -31.700 ;
            POLYGON 508.600 -31.700  508.600 -23.200  512.000 -23.200  512.000 -26.600  511.200 -26.600  511.200 -31.700 ;
            POLYGON 541.000 -31.700  541.000 -23.200  544.400 -23.200  544.400 -26.600  543.600 -26.600  543.600 -31.700 ;
            POLYGON 573.400 -31.700  573.400 -23.200  576.800 -23.200  576.800 -26.600  576.000 -26.600  576.000 -31.700 ;
            POLYGON 605.800 -31.700  605.800 -23.200  609.200 -23.200  609.200 -26.600  608.400 -26.600  608.400 -31.700 ;
            POLYGON 638.200 -31.700  638.200 -23.200  641.600 -23.200  641.600 -26.600  640.800 -26.600  640.800 -31.700 ;
            POLYGON 670.600 -31.700  670.600 -23.200  674.000 -23.200  674.000 -26.600  673.200 -26.600  673.200 -31.700 ;
            POLYGON 703.000 -31.700  703.000 -23.200  706.400 -23.200  706.400 -26.600  705.600 -26.600  705.600 -31.700 ;
            POLYGON 433.000 -102.700  433.000 -56.300  438.100 -56.300  438.100 -69.700  434.800 -69.700  434.800 -77.800  436.400 -77.800  436.400 -81.200  434.800 -81.200  434.800 -99.300  436.700 -99.300  436.700 -102.700 ;
            POLYGON 803.900 -48.100  803.900 -34.700  807.200 -34.700  807.200 -26.600  805.600 -26.600  805.600 -23.200  807.200 -23.200  807.200 -5.100  805.300 -5.100  805.300 -1.700  809.000 -1.700  809.000 -48.100 ;
            POLYGON 465.400 -102.700  465.400 -56.300  470.500 -56.300  470.500 -69.700  467.200 -69.700  467.200 -77.800  468.800 -77.800  468.800 -81.200  467.200 -81.200  467.200 -99.300  469.100 -99.300  469.100 -102.700 ;
            POLYGON 415.100 -48.100  415.100 -34.700  418.400 -34.700  418.400 -26.600  416.800 -26.600  416.800 -23.200  418.400 -23.200  418.400 -5.100  416.500 -5.100  416.500 -1.700  420.200 -1.700  420.200 -48.100 ;
            POLYGON 447.500 -48.100  447.500 -34.700  450.800 -34.700  450.800 -26.600  449.200 -26.600  449.200 -23.200  450.800 -23.200  450.800 -5.100  448.900 -5.100  448.900 -1.700  452.600 -1.700  452.600 -48.100 ;
            POLYGON 479.900 -48.100  479.900 -34.700  483.200 -34.700  483.200 -26.600  481.600 -26.600  481.600 -23.200  483.200 -23.200  483.200 -5.100  481.300 -5.100  481.300 -1.700  485.000 -1.700  485.000 -48.100 ;
            POLYGON 512.300 -48.100  512.300 -34.700  515.600 -34.700  515.600 -26.600  514.000 -26.600  514.000 -23.200  515.600 -23.200  515.600 -5.100  513.700 -5.100  513.700 -1.700  517.400 -1.700  517.400 -48.100 ;
            POLYGON 544.700 -48.100  544.700 -34.700  548.000 -34.700  548.000 -26.600  546.400 -26.600  546.400 -23.200  548.000 -23.200  548.000 -5.100  546.100 -5.100  546.100 -1.700  549.800 -1.700  549.800 -48.100 ;
            POLYGON 406.000 -81.200  406.000 -77.800  406.800 -77.800  406.800 -72.700  409.400 -72.700  409.400 -81.200 ;
            POLYGON 438.400 -81.200  438.400 -77.800  439.200 -77.800  439.200 -72.700  441.800 -72.700  441.800 -81.200 ;
            POLYGON 470.800 -81.200  470.800 -77.800  471.600 -77.800  471.600 -72.700  474.200 -72.700  474.200 -81.200 ;
            POLYGON 503.200 -81.200  503.200 -77.800  504.000 -77.800  504.000 -72.700  506.600 -72.700  506.600 -81.200 ;
            POLYGON 535.600 -81.200  535.600 -77.800  536.400 -77.800  536.400 -72.700  539.000 -72.700  539.000 -81.200 ;
            POLYGON 568.000 -81.200  568.000 -77.800  568.800 -77.800  568.800 -72.700  571.400 -72.700  571.400 -81.200 ;
            POLYGON 600.400 -81.200  600.400 -77.800  601.200 -77.800  601.200 -72.700  603.800 -72.700  603.800 -81.200 ;
            POLYGON 632.800 -81.200  632.800 -77.800  633.600 -77.800  633.600 -72.700  636.200 -72.700  636.200 -81.200 ;
            POLYGON 665.200 -81.200  665.200 -77.800  666.000 -77.800  666.000 -72.700  668.600 -72.700  668.600 -81.200 ;
            POLYGON 697.600 -81.200  697.600 -77.800  698.400 -77.800  698.400 -72.700  701.000 -72.700  701.000 -81.200 ;
            POLYGON 730.000 -81.200  730.000 -77.800  730.800 -77.800  730.800 -72.700  733.400 -72.700  733.400 -81.200 ;
            POLYGON 762.400 -81.200  762.400 -77.800  763.200 -77.800  763.200 -72.700  765.800 -72.700  765.800 -81.200 ;
            POLYGON 794.800 -81.200  794.800 -77.800  795.600 -77.800  795.600 -72.700  798.200 -72.700  798.200 -81.200 ;
            POLYGON 577.100 -48.100  577.100 -34.700  580.400 -34.700  580.400 -26.600  578.800 -26.600  578.800 -23.200  580.400 -23.200  580.400 -5.100  578.500 -5.100  578.500 -1.700  582.200 -1.700  582.200 -48.100 ;
            POLYGON 609.500 -48.100  609.500 -34.700  612.800 -34.700  612.800 -26.600  611.200 -26.600  611.200 -23.200  612.800 -23.200  612.800 -5.100  610.900 -5.100  610.900 -1.700  614.600 -1.700  614.600 -48.100 ;
            POLYGON 641.900 -48.100  641.900 -34.700  645.200 -34.700  645.200 -26.600  643.600 -26.600  643.600 -23.200  645.200 -23.200  645.200 -5.100  643.300 -5.100  643.300 -1.700  647.000 -1.700  647.000 -48.100 ;
            POLYGON 674.300 -48.100  674.300 -34.700  677.600 -34.700  677.600 -26.600  676.000 -26.600  676.000 -23.200  677.600 -23.200  677.600 -5.100  675.700 -5.100  675.700 -1.700  679.400 -1.700  679.400 -48.100 ;
            POLYGON 706.700 -48.100  706.700 -34.700  710.000 -34.700  710.000 -26.600  708.400 -26.600  708.400 -23.200  710.000 -23.200  710.000 -5.100  708.100 -5.100  708.100 -1.700  711.800 -1.700  711.800 -48.100 ;
            POLYGON 739.100 -48.100  739.100 -34.700  742.400 -34.700  742.400 -26.600  740.800 -26.600  740.800 -23.200  742.400 -23.200  742.400 -5.100  740.500 -5.100  740.500 -1.700  744.200 -1.700  744.200 -48.100 ;
        LAYER M2 ;
            POLYGON 794.800 -81.200  794.800 -77.800  825.200 -77.800  825.200 -81.200 ;
            POLYGON 805.600 -26.600  805.600 -23.200  836.000 -23.200  836.000 -26.600 ;
            POLYGON 805.600 28.000  805.600 31.400  836.000 31.400  836.000 28.000 ;
            POLYGON 11.800 -104.700  11.800 4.200  1518.400 4.200  1518.400 31.400  1521.800 31.400  1521.800 -26.600  1518.400 -26.600  1518.400 0.800  15.200 0.800  15.200 -104.700 ;
            POLYGON 794.800 82.600  794.800 86.000  825.200 86.000  825.200 82.600 ;
            POLYGON 956.800 -81.200  956.800 -77.800  987.200 -77.800  987.200 -81.200 ;
            POLYGON 989.200 -81.200  989.200 -77.800  1019.600 -77.800  1019.600 -81.200 ;
            POLYGON 1021.600 -81.200  1021.600 -77.800  1052.000 -77.800  1052.000 -81.200 ;
            POLYGON 1054.000 -81.200  1054.000 -77.800  1084.400 -77.800  1084.400 -81.200 ;
            POLYGON 1086.400 -81.200  1086.400 -77.800  1116.800 -77.800  1116.800 -81.200 ;
            POLYGON 1118.800 -81.200  1118.800 -77.800  1149.200 -77.800  1149.200 -81.200 ;
            POLYGON 1151.200 -81.200  1151.200 -77.800  1181.600 -77.800  1181.600 -81.200 ;
            POLYGON 1183.600 -81.200  1183.600 -77.800  1214.000 -77.800  1214.000 -81.200 ;
            POLYGON 1216.000 -81.200  1216.000 -77.800  1246.400 -77.800  1246.400 -81.200 ;
            POLYGON 1248.400 -81.200  1248.400 -77.800  1278.800 -77.800  1278.800 -81.200 ;
            POLYGON 1280.800 -81.200  1280.800 -77.800  1311.200 -77.800  1311.200 -81.200 ;
            POLYGON 1313.200 -81.200  1313.200 -77.800  1343.600 -77.800  1343.600 -81.200 ;
            POLYGON 1345.600 -81.200  1345.600 -77.800  1376.000 -77.800  1376.000 -81.200 ;
            POLYGON 1378.000 -81.200  1378.000 -77.800  1408.400 -77.800  1408.400 -81.200 ;
            POLYGON 1410.400 -81.200  1410.400 -77.800  1440.800 -77.800  1440.800 -81.200 ;
            POLYGON 1442.800 -81.200  1442.800 -77.800  1473.200 -77.800  1473.200 -81.200 ;
            POLYGON 1475.200 -81.200  1475.200 -77.800  1505.600 -77.800  1505.600 -81.200 ;
            POLYGON 1507.600 -81.200  1507.600 -77.800  1538.000 -77.800  1538.000 -81.200 ;
            POLYGON 1540.000 -81.200  1540.000 -77.800  1570.400 -77.800  1570.400 -81.200 ;
            POLYGON 1572.400 -81.200  1572.400 -77.800  1602.800 -77.800  1602.800 -81.200 ;
            POLYGON 827.200 -81.200  827.200 -77.800  857.600 -77.800  857.600 -81.200 ;
            POLYGON 838.000 -26.600  838.000 -23.200  868.400 -23.200  868.400 -26.600 ;
            POLYGON 870.400 -26.600  870.400 -23.200  900.800 -23.200  900.800 -26.600 ;
            POLYGON 902.800 -26.600  902.800 -23.200  933.200 -23.200  933.200 -26.600 ;
            POLYGON 935.200 -26.600  935.200 -23.200  965.600 -23.200  965.600 -26.600 ;
            POLYGON 967.600 -26.600  967.600 -23.200  998.000 -23.200  998.000 -26.600 ;
            POLYGON 1000.000 -26.600  1000.000 -23.200  1030.400 -23.200  1030.400 -26.600 ;
            POLYGON 1032.400 -26.600  1032.400 -23.200  1062.800 -23.200  1062.800 -26.600 ;
            POLYGON 1064.800 -26.600  1064.800 -23.200  1095.200 -23.200  1095.200 -26.600 ;
            POLYGON 1097.200 -26.600  1097.200 -23.200  1127.600 -23.200  1127.600 -26.600 ;
            POLYGON 1129.600 -26.600  1129.600 -23.200  1160.000 -23.200  1160.000 -26.600 ;
            POLYGON 1162.000 -26.600  1162.000 -23.200  1192.400 -23.200  1192.400 -26.600 ;
            POLYGON 1194.400 -26.600  1194.400 -23.200  1224.800 -23.200  1224.800 -26.600 ;
            POLYGON 1226.800 -26.600  1226.800 -23.200  1257.200 -23.200  1257.200 -26.600 ;
            POLYGON 1259.200 -26.600  1259.200 -23.200  1289.600 -23.200  1289.600 -26.600 ;
            POLYGON 1291.600 -26.600  1291.600 -23.200  1322.000 -23.200  1322.000 -26.600 ;
            POLYGON 1324.000 -26.600  1324.000 -23.200  1354.400 -23.200  1354.400 -26.600 ;
            POLYGON 1356.400 -26.600  1356.400 -23.200  1386.800 -23.200  1386.800 -26.600 ;
            POLYGON 1388.800 -26.600  1388.800 -23.200  1419.200 -23.200  1419.200 -26.600 ;
            POLYGON 1421.200 -26.600  1421.200 -23.200  1451.600 -23.200  1451.600 -26.600 ;
            POLYGON 1453.600 -26.600  1453.600 -23.200  1484.000 -23.200  1484.000 -26.600 ;
            POLYGON 1486.000 -26.600  1486.000 -23.200  1516.400 -23.200  1516.400 -26.600 ;
            POLYGON 1604.800 -81.200  1604.800 -59.300  1599.400 -59.300  1599.400 -26.600  1529.200 -26.600  1529.200 -23.200  1602.800 -23.200  1602.800 -55.900  1608.200 -55.900  1608.200 -81.200 ;
            POLYGON 1604.800 -26.600  1604.800 -23.200  1608.200 -23.200  1608.200 -26.600 ;
            POLYGON 859.600 -81.200  859.600 -77.800  890.000 -77.800  890.000 -81.200 ;
            POLYGON 838.000 28.000  838.000 31.400  868.400 31.400  868.400 28.000 ;
            POLYGON 870.400 28.000  870.400 31.400  900.800 31.400  900.800 28.000 ;
            POLYGON 902.800 28.000  902.800 31.400  933.200 31.400  933.200 28.000 ;
            POLYGON 935.200 28.000  935.200 31.400  965.600 31.400  965.600 28.000 ;
            POLYGON 967.600 28.000  967.600 31.400  998.000 31.400  998.000 28.000 ;
            POLYGON 1000.000 28.000  1000.000 31.400  1030.400 31.400  1030.400 28.000 ;
            POLYGON 1032.400 28.000  1032.400 31.400  1062.800 31.400  1062.800 28.000 ;
            POLYGON 1064.800 28.000  1064.800 31.400  1095.200 31.400  1095.200 28.000 ;
            POLYGON 1097.200 28.000  1097.200 31.400  1127.600 31.400  1127.600 28.000 ;
            POLYGON 1129.600 28.000  1129.600 31.400  1160.000 31.400  1160.000 28.000 ;
            POLYGON 1162.000 28.000  1162.000 31.400  1192.400 31.400  1192.400 28.000 ;
            POLYGON 1194.400 28.000  1194.400 31.400  1224.800 31.400  1224.800 28.000 ;
            POLYGON 1226.800 28.000  1226.800 31.400  1257.200 31.400  1257.200 28.000 ;
            POLYGON 1259.200 28.000  1259.200 31.400  1289.600 31.400  1289.600 28.000 ;
            POLYGON 1291.600 28.000  1291.600 31.400  1322.000 31.400  1322.000 28.000 ;
            POLYGON 1324.000 28.000  1324.000 31.400  1354.400 31.400  1354.400 28.000 ;
            POLYGON 1356.400 28.000  1356.400 31.400  1386.800 31.400  1386.800 28.000 ;
            POLYGON 1388.800 28.000  1388.800 31.400  1419.200 31.400  1419.200 28.000 ;
            POLYGON 1421.200 28.000  1421.200 31.400  1451.600 31.400  1451.600 28.000 ;
            POLYGON 1453.600 28.000  1453.600 31.400  1484.000 31.400  1484.000 28.000 ;
            POLYGON 1486.000 28.000  1486.000 31.400  1516.400 31.400  1516.400 28.000 ;
            POLYGON 892.000 -81.200  892.000 -77.800  922.400 -77.800  922.400 -81.200 ;
            POLYGON 1604.800 28.000  1604.800 31.400  1608.200 31.400  1608.200 28.000 ;
            POLYGON 924.400 -81.200  924.400 -77.800  954.800 -77.800  954.800 -81.200 ;
            POLYGON 827.200 82.600  827.200 86.000  857.600 86.000  857.600 82.600 ;
            POLYGON 859.600 82.600  859.600 86.000  890.000 86.000  890.000 82.600 ;
            POLYGON 892.000 82.600  892.000 86.000  922.400 86.000  922.400 82.600 ;
            POLYGON 924.400 82.600  924.400 86.000  954.800 86.000  954.800 82.600 ;
            POLYGON 956.800 82.600  956.800 86.000  987.200 86.000  987.200 82.600 ;
            POLYGON 989.200 82.600  989.200 86.000  1019.600 86.000  1019.600 82.600 ;
            POLYGON 1021.600 82.600  1021.600 86.000  1052.000 86.000  1052.000 82.600 ;
            POLYGON 1054.000 82.600  1054.000 86.000  1084.400 86.000  1084.400 82.600 ;
            POLYGON 1086.400 82.600  1086.400 86.000  1116.800 86.000  1116.800 82.600 ;
            POLYGON 1118.800 82.600  1118.800 86.000  1149.200 86.000  1149.200 82.600 ;
            POLYGON 1151.200 82.600  1151.200 86.000  1181.600 86.000  1181.600 82.600 ;
            POLYGON 1183.600 82.600  1183.600 86.000  1214.000 86.000  1214.000 82.600 ;
            POLYGON 1216.000 82.600  1216.000 86.000  1246.400 86.000  1246.400 82.600 ;
            POLYGON 1248.400 82.600  1248.400 86.000  1278.800 86.000  1278.800 82.600 ;
            POLYGON 1280.800 82.600  1280.800 86.000  1311.200 86.000  1311.200 82.600 ;
            POLYGON 1313.200 82.600  1313.200 86.000  1343.600 86.000  1343.600 82.600 ;
            POLYGON 1345.600 82.600  1345.600 86.000  1376.000 86.000  1376.000 82.600 ;
            POLYGON 1378.000 82.600  1378.000 86.000  1408.400 86.000  1408.400 82.600 ;
            POLYGON 1410.400 82.600  1410.400 86.000  1440.800 86.000  1440.800 82.600 ;
            POLYGON 1442.800 82.600  1442.800 86.000  1473.200 86.000  1473.200 82.600 ;
            POLYGON 1475.200 82.600  1475.200 86.000  1505.600 86.000  1505.600 82.600 ;
            POLYGON 1507.600 82.600  1507.600 86.000  1538.000 86.000  1538.000 82.600 ;
            POLYGON 1540.000 82.600  1540.000 86.000  1570.400 86.000  1570.400 82.600 ;
            POLYGON 1572.400 82.600  1572.400 86.000  1602.800 86.000  1602.800 82.600 ;
            POLYGON 1529.200 28.000  1529.200 31.400  1599.400 31.400  1599.400 64.100  1604.800 64.100  1604.800 86.000  1608.200 86.000  1608.200 60.700  1602.800 60.700  1602.800 28.000 ;
            POLYGON 1610.200 -108.100  1610.200 112.900  1613.600 112.900  1613.600 -108.100 ;
            POLYGON 1615.600 -108.100  1615.600 112.900  1619.000 112.900  1619.000 -108.100 ;
            POLYGON 157.600 28.000  157.600 31.400  188.000 31.400  188.000 28.000 ;
            POLYGON 190.000 28.000  190.000 31.400  220.400 31.400  220.400 28.000 ;
            POLYGON 222.400 28.000  222.400 31.400  252.800 31.400  252.800 28.000 ;
            POLYGON 254.800 28.000  254.800 31.400  285.200 31.400  285.200 28.000 ;
            POLYGON 287.200 28.000  287.200 31.400  317.600 31.400  317.600 28.000 ;
            POLYGON 319.600 28.000  319.600 31.400  350.000 31.400  350.000 28.000 ;
            POLYGON 352.000 28.000  352.000 31.400  382.400 31.400  382.400 28.000 ;
            POLYGON 384.400 28.000  384.400 31.400  414.800 31.400  414.800 28.000 ;
            POLYGON 416.800 28.000  416.800 31.400  447.200 31.400  447.200 28.000 ;
            POLYGON 449.200 28.000  449.200 31.400  479.600 31.400  479.600 28.000 ;
            POLYGON 481.600 28.000  481.600 31.400  512.000 31.400  512.000 28.000 ;
            POLYGON 514.000 28.000  514.000 31.400  544.400 31.400  544.400 28.000 ;
            POLYGON 546.400 28.000  546.400 31.400  576.800 31.400  576.800 28.000 ;
            POLYGON 578.800 28.000  578.800 31.400  609.200 31.400  609.200 28.000 ;
            POLYGON 611.200 28.000  611.200 31.400  641.600 31.400  641.600 28.000 ;
            POLYGON 643.600 28.000  643.600 31.400  674.000 31.400  674.000 28.000 ;
            POLYGON 676.000 28.000  676.000 31.400  706.400 31.400  706.400 28.000 ;
            POLYGON 708.400 28.000  708.400 31.400  738.800 31.400  738.800 28.000 ;
            POLYGON 740.800 28.000  740.800 31.400  771.200 31.400  771.200 28.000 ;
            POLYGON 773.200 28.000  773.200 31.400  803.600 31.400  803.600 28.000 ;
            POLYGON 28.000 -26.600  28.000 -23.200  58.400 -23.200  58.400 -26.600 ;
            POLYGON 60.400 -26.600  60.400 -23.200  90.800 -23.200  90.800 -26.600 ;
            POLYGON 92.800 -26.600  92.800 -23.200  123.200 -23.200  123.200 -26.600 ;
            POLYGON 125.200 -26.600  125.200 -23.200  155.600 -23.200  155.600 -26.600 ;
            POLYGON 157.600 -26.600  157.600 -23.200  188.000 -23.200  188.000 -26.600 ;
            POLYGON 190.000 -26.600  190.000 -23.200  220.400 -23.200  220.400 -26.600 ;
            POLYGON 222.400 -26.600  222.400 -23.200  252.800 -23.200  252.800 -26.600 ;
            POLYGON 254.800 -26.600  254.800 -23.200  285.200 -23.200  285.200 -26.600 ;
            POLYGON 287.200 -26.600  287.200 -23.200  317.600 -23.200  317.600 -26.600 ;
            POLYGON 319.600 -26.600  319.600 -23.200  350.000 -23.200  350.000 -26.600 ;
            POLYGON 352.000 -26.600  352.000 -23.200  382.400 -23.200  382.400 -26.600 ;
            POLYGON 384.400 -26.600  384.400 -23.200  414.800 -23.200  414.800 -26.600 ;
            POLYGON 416.800 -26.600  416.800 -23.200  447.200 -23.200  447.200 -26.600 ;
            POLYGON 449.200 -26.600  449.200 -23.200  479.600 -23.200  479.600 -26.600 ;
            POLYGON 481.600 -26.600  481.600 -23.200  512.000 -23.200  512.000 -26.600 ;
            POLYGON 514.000 -26.600  514.000 -23.200  544.400 -23.200  544.400 -26.600 ;
            POLYGON 546.400 -26.600  546.400 -23.200  576.800 -23.200  576.800 -26.600 ;
            POLYGON 578.800 -26.600  578.800 -23.200  609.200 -23.200  609.200 -26.600 ;
            POLYGON 611.200 -26.600  611.200 -23.200  641.600 -23.200  641.600 -26.600 ;
            POLYGON 643.600 -26.600  643.600 -23.200  674.000 -23.200  674.000 -26.600 ;
            POLYGON 676.000 -26.600  676.000 -23.200  706.400 -23.200  706.400 -26.600 ;
            POLYGON 708.400 -26.600  708.400 -23.200  738.800 -23.200  738.800 -26.600 ;
            POLYGON 740.800 -26.600  740.800 -23.200  771.200 -23.200  771.200 -26.600 ;
            POLYGON 773.200 -26.600  773.200 -23.200  803.600 -23.200  803.600 -26.600 ;
            POLYGON 22.600 28.000  22.600 82.600  20.600 82.600  20.600 86.000  47.600 86.000  47.600 82.600  26.000 82.600  26.000 28.000 ;
            POLYGON 49.600 82.600  49.600 86.000  80.000 86.000  80.000 82.600 ;
            POLYGON 82.000 82.600  82.000 86.000  112.400 86.000  112.400 82.600 ;
            POLYGON 114.400 82.600  114.400 86.000  144.800 86.000  144.800 82.600 ;
            POLYGON 146.800 82.600  146.800 86.000  177.200 86.000  177.200 82.600 ;
            POLYGON 179.200 82.600  179.200 86.000  209.600 86.000  209.600 82.600 ;
            POLYGON 211.600 82.600  211.600 86.000  242.000 86.000  242.000 82.600 ;
            POLYGON 244.000 82.600  244.000 86.000  274.400 86.000  274.400 82.600 ;
            POLYGON 276.400 82.600  276.400 86.000  306.800 86.000  306.800 82.600 ;
            POLYGON 308.800 82.600  308.800 86.000  339.200 86.000  339.200 82.600 ;
            POLYGON 341.200 82.600  341.200 86.000  371.600 86.000  371.600 82.600 ;
            POLYGON 373.600 82.600  373.600 86.000  404.000 86.000  404.000 82.600 ;
            POLYGON 406.000 82.600  406.000 86.000  436.400 86.000  436.400 82.600 ;
            POLYGON 438.400 82.600  438.400 86.000  468.800 86.000  468.800 82.600 ;
            POLYGON 470.800 82.600  470.800 86.000  501.200 86.000  501.200 82.600 ;
            POLYGON 503.200 82.600  503.200 86.000  533.600 86.000  533.600 82.600 ;
            POLYGON 535.600 82.600  535.600 86.000  566.000 86.000  566.000 82.600 ;
            POLYGON 568.000 82.600  568.000 86.000  598.400 86.000  598.400 82.600 ;
            POLYGON 600.400 82.600  600.400 86.000  630.800 86.000  630.800 82.600 ;
            POLYGON 632.800 82.600  632.800 86.000  663.200 86.000  663.200 82.600 ;
            POLYGON 665.200 82.600  665.200 86.000  695.600 86.000  695.600 82.600 ;
            POLYGON 697.600 82.600  697.600 86.000  728.000 86.000  728.000 82.600 ;
            POLYGON 730.000 82.600  730.000 86.000  760.400 86.000  760.400 82.600 ;
            POLYGON 762.400 82.600  762.400 86.000  792.800 86.000  792.800 82.600 ;
            POLYGON 114.400 -81.200  114.400 -77.800  144.800 -77.800  144.800 -81.200 ;
            POLYGON 146.800 -81.200  146.800 -77.800  177.200 -77.800  177.200 -81.200 ;
            POLYGON 179.200 -81.200  179.200 -77.800  209.600 -77.800  209.600 -81.200 ;
            POLYGON 211.600 -81.200  211.600 -77.800  242.000 -77.800  242.000 -81.200 ;
            POLYGON 244.000 -81.200  244.000 -77.800  274.400 -77.800  274.400 -81.200 ;
            POLYGON 276.400 -81.200  276.400 -77.800  306.800 -77.800  306.800 -81.200 ;
            POLYGON 308.800 -81.200  308.800 -77.800  339.200 -77.800  339.200 -81.200 ;
            POLYGON 341.200 -81.200  341.200 -77.800  371.600 -77.800  371.600 -81.200 ;
            POLYGON 373.600 -81.200  373.600 -77.800  404.000 -77.800  404.000 -81.200 ;
            POLYGON 406.000 -81.200  406.000 -77.800  436.400 -77.800  436.400 -81.200 ;
            POLYGON 438.400 -81.200  438.400 -77.800  468.800 -77.800  468.800 -81.200 ;
            POLYGON 470.800 -81.200  470.800 -77.800  501.200 -77.800  501.200 -81.200 ;
            POLYGON 503.200 -81.200  503.200 -77.800  533.600 -77.800  533.600 -81.200 ;
            POLYGON 535.600 -81.200  535.600 -77.800  566.000 -77.800  566.000 -81.200 ;
            POLYGON 568.000 -81.200  568.000 -77.800  598.400 -77.800  598.400 -81.200 ;
            POLYGON 600.400 -81.200  600.400 -77.800  630.800 -77.800  630.800 -81.200 ;
            POLYGON 632.800 -81.200  632.800 -77.800  663.200 -77.800  663.200 -81.200 ;
            POLYGON 665.200 -81.200  665.200 -77.800  695.600 -77.800  695.600 -81.200 ;
            POLYGON 697.600 -81.200  697.600 -77.800  728.000 -77.800  728.000 -81.200 ;
            POLYGON 730.000 -81.200  730.000 -77.800  760.400 -77.800  760.400 -81.200 ;
            POLYGON 762.400 -81.200  762.400 -77.800  792.800 -77.800  792.800 -81.200 ;
            POLYGON 49.600 -81.200  49.600 -77.800  80.000 -77.800  80.000 -81.200 ;
            POLYGON 82.000 -81.200  82.000 -77.800  112.400 -77.800  112.400 -81.200 ;
            POLYGON 20.600 -81.200  20.600 -77.800  22.600 -77.800  22.600 -23.200  26.000 -23.200  26.000 -77.800  47.600 -77.800  47.600 -81.200 ;
            POLYGON 28.000 28.000  28.000 31.400  58.400 31.400  58.400 28.000 ;
            POLYGON 60.400 28.000  60.400 31.400  90.800 31.400  90.800 28.000 ;
            POLYGON 1.000 -108.100  1.000 112.900  4.400 112.900  4.400 -108.100 ;
            POLYGON 6.400 -108.100  6.400 112.900  9.800 112.900  9.800 -108.100 ;
            POLYGON 92.800 28.000  92.800 31.400  123.200 31.400  123.200 28.000 ;
            POLYGON 125.200 28.000  125.200 31.400  155.600 31.400  155.600 28.000 ;
    END

END RING_OSC
END LIBRARY
